VERSION 5.8 ;
BUSBITCHARS "[]" ;
DIVIDERCHAR "/" ;
UNITS
    DATABASE MICRONS 1000 ;
END UNITS

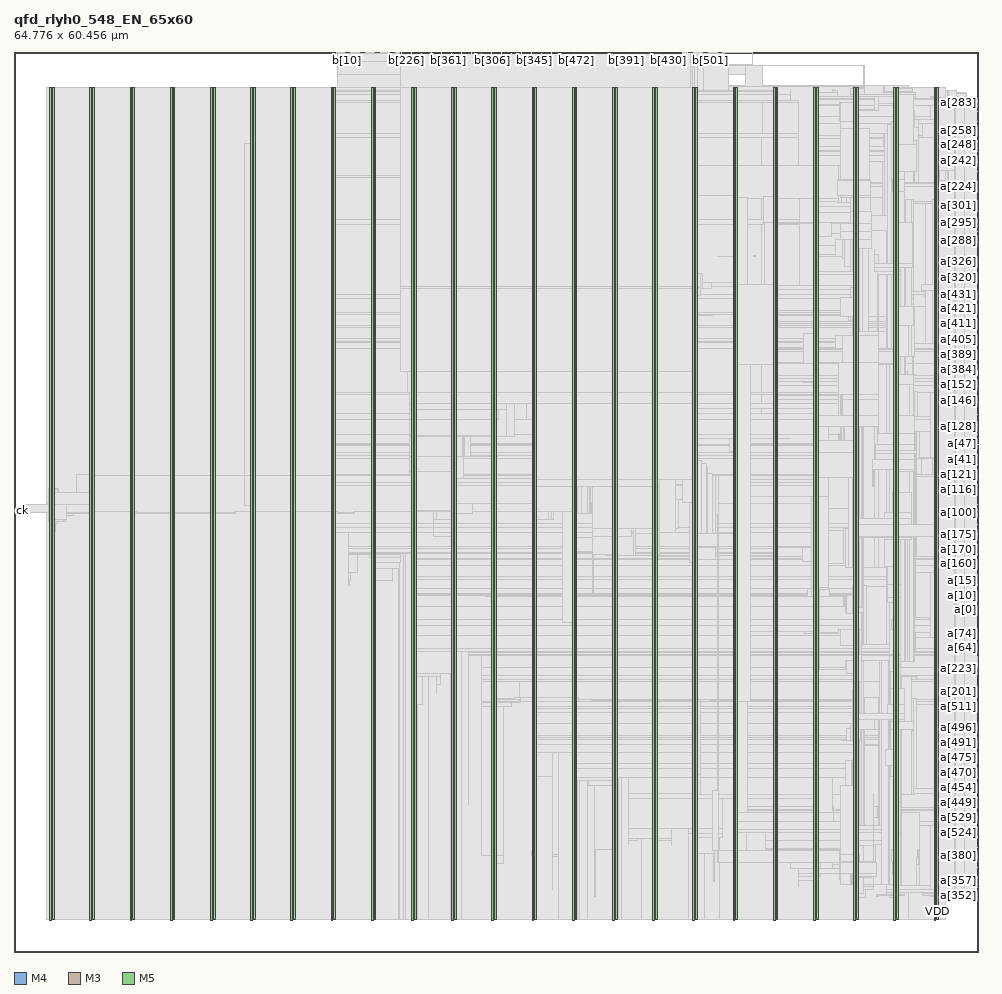
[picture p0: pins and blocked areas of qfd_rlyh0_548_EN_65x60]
MACRO qfd_rlyh0_548_EN_65x60
  FOREIGN qfd_rlyh0_548_EN_65x60 0 0 ;
  CLASS BLOCK ;
  SIZE 64.776 BY 60.456 ;
  PIN a[0]
    DIRECTION INPUT ;
    USE SIGNAL ;
    PORT
      LAYER M4 ;
        RECT  64.692 22.992 64.776 23.016 ;
    END
  END a[0]
  PIN a[100]
    DIRECTION INPUT ;
    USE SIGNAL ;
    PORT
      LAYER M4 ;
        RECT  64.692 29.52 64.776 29.544 ;
    END
  END a[100]
  PIN a[101]
    DIRECTION INPUT ;
    USE SIGNAL ;
    PORT
      LAYER M4 ;
        RECT  64.692 29.616 64.776 29.64 ;
    END
  END a[101]
  PIN a[102]
    DIRECTION INPUT ;
    USE SIGNAL ;
    PORT
      LAYER M4 ;
        RECT  64.692 29.712 64.776 29.736 ;
    END
  END a[102]
  PIN a[103]
    DIRECTION INPUT ;
    USE SIGNAL ;
    PORT
      LAYER M4 ;
        RECT  64.692 29.808 64.776 29.832 ;
    END
  END a[103]
  PIN a[104]
    DIRECTION INPUT ;
    USE SIGNAL ;
    PORT
      LAYER M4 ;
        RECT  64.692 29.904 64.776 29.928 ;
    END
  END a[104]
  PIN a[105]
    DIRECTION INPUT ;
    USE SIGNAL ;
    PORT
      LAYER M4 ;
        RECT  64.692 30 64.776 30.024 ;
    END
  END a[105]
  PIN a[106]
    DIRECTION INPUT ;
    USE SIGNAL ;
    PORT
      LAYER M4 ;
        RECT  64.692 30.096 64.776 30.12 ;
    END
  END a[106]
  PIN a[107]
    DIRECTION INPUT ;
    USE SIGNAL ;
    PORT
      LAYER M4 ;
        RECT  64.692 30.192 64.776 30.216 ;
    END
  END a[107]
  PIN a[108]
    DIRECTION INPUT ;
    USE SIGNAL ;
    PORT
      LAYER M4 ;
        RECT  64.692 30.288 64.776 30.312 ;
    END
  END a[108]
  PIN a[109]
    DIRECTION INPUT ;
    USE SIGNAL ;
    PORT
      LAYER M4 ;
        RECT  64.692 30.384 64.776 30.408 ;
    END
  END a[109]
  PIN a[10]
    DIRECTION INPUT ;
    USE SIGNAL ;
    PORT
      LAYER M4 ;
        RECT  64.692 23.952 64.776 23.976 ;
    END
  END a[10]
  PIN a[110]
    DIRECTION INPUT ;
    USE SIGNAL ;
    PORT
      LAYER M4 ;
        RECT  64.692 30.48 64.776 30.504 ;
    END
  END a[110]
  PIN a[111]
    DIRECTION INPUT ;
    USE SIGNAL ;
    PORT
      LAYER M4 ;
        RECT  64.692 30.576 64.776 30.6 ;
    END
  END a[111]
  PIN a[112]
    DIRECTION INPUT ;
    USE SIGNAL ;
    PORT
      LAYER M4 ;
        RECT  64.692 30.672 64.776 30.696 ;
    END
  END a[112]
  PIN a[113]
    DIRECTION INPUT ;
    USE SIGNAL ;
    PORT
      LAYER M4 ;
        RECT  64.692 30.768 64.776 30.792 ;
    END
  END a[113]
  PIN a[114]
    DIRECTION INPUT ;
    USE SIGNAL ;
    PORT
      LAYER M4 ;
        RECT  64.692 30.864 64.776 30.888 ;
    END
  END a[114]
  PIN a[115]
    DIRECTION INPUT ;
    USE SIGNAL ;
    PORT
      LAYER M4 ;
        RECT  64.692 30.96 64.776 30.984 ;
    END
  END a[115]
  PIN a[116]
    DIRECTION INPUT ;
    USE SIGNAL ;
    PORT
      LAYER M4 ;
        RECT  64.692 31.056 64.776 31.08 ;
    END
  END a[116]
  PIN a[117]
    DIRECTION INPUT ;
    USE SIGNAL ;
    PORT
      LAYER M4 ;
        RECT  64.692 31.152 64.776 31.176 ;
    END
  END a[117]
  PIN a[118]
    DIRECTION INPUT ;
    USE SIGNAL ;
    PORT
      LAYER M4 ;
        RECT  64.692 31.248 64.776 31.272 ;
    END
  END a[118]
  PIN a[119]
    DIRECTION INPUT ;
    USE SIGNAL ;
    PORT
      LAYER M4 ;
        RECT  64.692 31.344 64.776 31.368 ;
    END
  END a[119]
  PIN a[11]
    DIRECTION INPUT ;
    USE SIGNAL ;
    PORT
      LAYER M4 ;
        RECT  64.692 24.048 64.776 24.072 ;
    END
  END a[11]
  PIN a[120]
    DIRECTION INPUT ;
    USE SIGNAL ;
    PORT
      LAYER M4 ;
        RECT  64.692 31.44 64.776 31.464 ;
    END
  END a[120]
  PIN a[121]
    DIRECTION INPUT ;
    USE SIGNAL ;
    PORT
      LAYER M4 ;
        RECT  64.692 31.536 64.776 31.56 ;
    END
  END a[121]
  PIN a[122]
    DIRECTION INPUT ;
    USE SIGNAL ;
    PORT
      LAYER M4 ;
        RECT  64.692 31.632 64.776 31.656 ;
    END
  END a[122]
  PIN a[123]
    DIRECTION INPUT ;
    USE SIGNAL ;
    PORT
      LAYER M4 ;
        RECT  64.692 31.728 64.776 31.752 ;
    END
  END a[123]
  PIN a[124]
    DIRECTION INPUT ;
    USE SIGNAL ;
    PORT
      LAYER M4 ;
        RECT  64.692 31.824 64.776 31.848 ;
    END
  END a[124]
  PIN a[125]
    DIRECTION INPUT ;
    USE SIGNAL ;
    PORT
      LAYER M4 ;
        RECT  64.692 31.92 64.776 31.944 ;
    END
  END a[125]
  PIN a[126]
    DIRECTION INPUT ;
    USE SIGNAL ;
    PORT
      LAYER M4 ;
        RECT  64.692 32.016 64.776 32.04 ;
    END
  END a[126]
  PIN a[127]
    DIRECTION INPUT ;
    USE SIGNAL ;
    PORT
      LAYER M4 ;
        RECT  64.692 32.112 64.776 32.136 ;
    END
  END a[127]
  PIN a[128]
    DIRECTION INPUT ;
    USE SIGNAL ;
    PORT
      LAYER M4 ;
        RECT  64.692 35.28 64.776 35.304 ;
    END
  END a[128]
  PIN a[129]
    DIRECTION INPUT ;
    USE SIGNAL ;
    PORT
      LAYER M4 ;
        RECT  64.692 35.376 64.776 35.4 ;
    END
  END a[129]
  PIN a[12]
    DIRECTION INPUT ;
    USE SIGNAL ;
    PORT
      LAYER M4 ;
        RECT  64.692 24.144 64.776 24.168 ;
    END
  END a[12]
  PIN a[130]
    DIRECTION INPUT ;
    USE SIGNAL ;
    PORT
      LAYER M4 ;
        RECT  64.692 35.472 64.776 35.496 ;
    END
  END a[130]
  PIN a[131]
    DIRECTION INPUT ;
    USE SIGNAL ;
    PORT
      LAYER M4 ;
        RECT  64.692 35.568 64.776 35.592 ;
    END
  END a[131]
  PIN a[132]
    DIRECTION INPUT ;
    USE SIGNAL ;
    PORT
      LAYER M4 ;
        RECT  64.692 35.664 64.776 35.688 ;
    END
  END a[132]
  PIN a[133]
    DIRECTION INPUT ;
    USE SIGNAL ;
    PORT
      LAYER M4 ;
        RECT  64.692 35.76 64.776 35.784 ;
    END
  END a[133]
  PIN a[134]
    DIRECTION INPUT ;
    USE SIGNAL ;
    PORT
      LAYER M4 ;
        RECT  64.692 35.856 64.776 35.88 ;
    END
  END a[134]
  PIN a[135]
    DIRECTION INPUT ;
    USE SIGNAL ;
    PORT
      LAYER M4 ;
        RECT  64.692 35.952 64.776 35.976 ;
    END
  END a[135]
  PIN a[136]
    DIRECTION INPUT ;
    USE SIGNAL ;
    PORT
      LAYER M4 ;
        RECT  64.692 36.048 64.776 36.072 ;
    END
  END a[136]
  PIN a[137]
    DIRECTION INPUT ;
    USE SIGNAL ;
    PORT
      LAYER M4 ;
        RECT  64.692 36.144 64.776 36.168 ;
    END
  END a[137]
  PIN a[138]
    DIRECTION INPUT ;
    USE SIGNAL ;
    PORT
      LAYER M4 ;
        RECT  64.692 36.24 64.776 36.264 ;
    END
  END a[138]
  PIN a[139]
    DIRECTION INPUT ;
    USE SIGNAL ;
    PORT
      LAYER M4 ;
        RECT  64.692 36.336 64.776 36.36 ;
    END
  END a[139]
  PIN a[13]
    DIRECTION INPUT ;
    USE SIGNAL ;
    PORT
      LAYER M4 ;
        RECT  64.692 24.24 64.776 24.264 ;
    END
  END a[13]
  PIN a[140]
    DIRECTION INPUT ;
    USE SIGNAL ;
    PORT
      LAYER M4 ;
        RECT  64.692 36.432 64.776 36.456 ;
    END
  END a[140]
  PIN a[141]
    DIRECTION INPUT ;
    USE SIGNAL ;
    PORT
      LAYER M4 ;
        RECT  64.692 36.528 64.776 36.552 ;
    END
  END a[141]
  PIN a[142]
    DIRECTION INPUT ;
    USE SIGNAL ;
    PORT
      LAYER M4 ;
        RECT  64.692 36.624 64.776 36.648 ;
    END
  END a[142]
  PIN a[143]
    DIRECTION INPUT ;
    USE SIGNAL ;
    PORT
      LAYER M4 ;
        RECT  64.692 36.72 64.776 36.744 ;
    END
  END a[143]
  PIN a[144]
    DIRECTION INPUT ;
    USE SIGNAL ;
    PORT
      LAYER M4 ;
        RECT  64.692 36.816 64.776 36.84 ;
    END
  END a[144]
  PIN a[145]
    DIRECTION INPUT ;
    USE SIGNAL ;
    PORT
      LAYER M4 ;
        RECT  64.692 36.912 64.776 36.936 ;
    END
  END a[145]
  PIN a[146]
    DIRECTION INPUT ;
    USE SIGNAL ;
    PORT
      LAYER M4 ;
        RECT  64.692 37.008 64.776 37.032 ;
    END
  END a[146]
  PIN a[147]
    DIRECTION INPUT ;
    USE SIGNAL ;
    PORT
      LAYER M4 ;
        RECT  64.692 37.104 64.776 37.128 ;
    END
  END a[147]
  PIN a[148]
    DIRECTION INPUT ;
    USE SIGNAL ;
    PORT
      LAYER M4 ;
        RECT  64.692 37.2 64.776 37.224 ;
    END
  END a[148]
  PIN a[149]
    DIRECTION INPUT ;
    USE SIGNAL ;
    PORT
      LAYER M4 ;
        RECT  64.692 37.296 64.776 37.32 ;
    END
  END a[149]
  PIN a[14]
    DIRECTION INPUT ;
    USE SIGNAL ;
    PORT
      LAYER M4 ;
        RECT  64.692 24.336 64.776 24.36 ;
    END
  END a[14]
  PIN a[150]
    DIRECTION INPUT ;
    USE SIGNAL ;
    PORT
      LAYER M4 ;
        RECT  64.692 37.392 64.776 37.416 ;
    END
  END a[150]
  PIN a[151]
    DIRECTION INPUT ;
    USE SIGNAL ;
    PORT
      LAYER M4 ;
        RECT  64.692 37.488 64.776 37.512 ;
    END
  END a[151]
  PIN a[152]
    DIRECTION INPUT ;
    USE SIGNAL ;
    PORT
      LAYER M4 ;
        RECT  64.692 37.584 64.776 37.608 ;
    END
  END a[152]
  PIN a[153]
    DIRECTION INPUT ;
    USE SIGNAL ;
    PORT
      LAYER M4 ;
        RECT  64.692 37.68 64.776 37.704 ;
    END
  END a[153]
  PIN a[154]
    DIRECTION INPUT ;
    USE SIGNAL ;
    PORT
      LAYER M4 ;
        RECT  64.692 37.776 64.776 37.8 ;
    END
  END a[154]
  PIN a[155]
    DIRECTION INPUT ;
    USE SIGNAL ;
    PORT
      LAYER M4 ;
        RECT  64.692 37.872 64.776 37.896 ;
    END
  END a[155]
  PIN a[156]
    DIRECTION INPUT ;
    USE SIGNAL ;
    PORT
      LAYER M4 ;
        RECT  64.692 37.968 64.776 37.992 ;
    END
  END a[156]
  PIN a[157]
    DIRECTION INPUT ;
    USE SIGNAL ;
    PORT
      LAYER M4 ;
        RECT  64.692 38.064 64.776 38.088 ;
    END
  END a[157]
  PIN a[158]
    DIRECTION INPUT ;
    USE SIGNAL ;
    PORT
      LAYER M4 ;
        RECT  64.692 38.16 64.776 38.184 ;
    END
  END a[158]
  PIN a[159]
    DIRECTION INPUT ;
    USE SIGNAL ;
    PORT
      LAYER M4 ;
        RECT  64.692 38.256 64.776 38.28 ;
    END
  END a[159]
  PIN a[15]
    DIRECTION INPUT ;
    USE SIGNAL ;
    PORT
      LAYER M4 ;
        RECT  64.692 24.432 64.776 24.456 ;
    END
  END a[15]
  PIN a[160]
    DIRECTION INPUT ;
    USE SIGNAL ;
    PORT
      LAYER M4 ;
        RECT  64.692 26.064 64.776 26.088 ;
    END
  END a[160]
  PIN a[161]
    DIRECTION INPUT ;
    USE SIGNAL ;
    PORT
      LAYER M4 ;
        RECT  64.692 26.16 64.776 26.184 ;
    END
  END a[161]
  PIN a[162]
    DIRECTION INPUT ;
    USE SIGNAL ;
    PORT
      LAYER M4 ;
        RECT  64.692 26.256 64.776 26.28 ;
    END
  END a[162]
  PIN a[163]
    DIRECTION INPUT ;
    USE SIGNAL ;
    PORT
      LAYER M4 ;
        RECT  64.692 26.352 64.776 26.376 ;
    END
  END a[163]
  PIN a[164]
    DIRECTION INPUT ;
    USE SIGNAL ;
    PORT
      LAYER M4 ;
        RECT  64.692 26.448 64.776 26.472 ;
    END
  END a[164]
  PIN a[165]
    DIRECTION INPUT ;
    USE SIGNAL ;
    PORT
      LAYER M4 ;
        RECT  64.692 26.544 64.776 26.568 ;
    END
  END a[165]
  PIN a[166]
    DIRECTION INPUT ;
    USE SIGNAL ;
    PORT
      LAYER M4 ;
        RECT  64.692 26.64 64.776 26.664 ;
    END
  END a[166]
  PIN a[167]
    DIRECTION INPUT ;
    USE SIGNAL ;
    PORT
      LAYER M4 ;
        RECT  64.692 26.736 64.776 26.76 ;
    END
  END a[167]
  PIN a[168]
    DIRECTION INPUT ;
    USE SIGNAL ;
    PORT
      LAYER M4 ;
        RECT  64.692 26.832 64.776 26.856 ;
    END
  END a[168]
  PIN a[169]
    DIRECTION INPUT ;
    USE SIGNAL ;
    PORT
      LAYER M4 ;
        RECT  64.692 26.928 64.776 26.952 ;
    END
  END a[169]
  PIN a[16]
    DIRECTION INPUT ;
    USE SIGNAL ;
    PORT
      LAYER M4 ;
        RECT  64.692 24.528 64.776 24.552 ;
    END
  END a[16]
  PIN a[170]
    DIRECTION INPUT ;
    USE SIGNAL ;
    PORT
      LAYER M4 ;
        RECT  64.692 27.024 64.776 27.048 ;
    END
  END a[170]
  PIN a[171]
    DIRECTION INPUT ;
    USE SIGNAL ;
    PORT
      LAYER M4 ;
        RECT  64.692 27.12 64.776 27.144 ;
    END
  END a[171]
  PIN a[172]
    DIRECTION INPUT ;
    USE SIGNAL ;
    PORT
      LAYER M4 ;
        RECT  64.692 27.216 64.776 27.24 ;
    END
  END a[172]
  PIN a[173]
    DIRECTION INPUT ;
    USE SIGNAL ;
    PORT
      LAYER M4 ;
        RECT  64.692 27.312 64.776 27.336 ;
    END
  END a[173]
  PIN a[174]
    DIRECTION INPUT ;
    USE SIGNAL ;
    PORT
      LAYER M4 ;
        RECT  64.692 27.408 64.776 27.432 ;
    END
  END a[174]
  PIN a[175]
    DIRECTION INPUT ;
    USE SIGNAL ;
    PORT
      LAYER M4 ;
        RECT  64.692 27.504 64.776 27.528 ;
    END
  END a[175]
  PIN a[176]
    DIRECTION INPUT ;
    USE SIGNAL ;
    PORT
      LAYER M4 ;
        RECT  64.692 27.6 64.776 27.624 ;
    END
  END a[176]
  PIN a[177]
    DIRECTION INPUT ;
    USE SIGNAL ;
    PORT
      LAYER M4 ;
        RECT  64.692 27.696 64.776 27.72 ;
    END
  END a[177]
  PIN a[178]
    DIRECTION INPUT ;
    USE SIGNAL ;
    PORT
      LAYER M4 ;
        RECT  64.692 27.792 64.776 27.816 ;
    END
  END a[178]
  PIN a[179]
    DIRECTION INPUT ;
    USE SIGNAL ;
    PORT
      LAYER M4 ;
        RECT  64.692 27.888 64.776 27.912 ;
    END
  END a[179]
  PIN a[17]
    DIRECTION INPUT ;
    USE SIGNAL ;
    PORT
      LAYER M4 ;
        RECT  64.692 24.624 64.776 24.648 ;
    END
  END a[17]
  PIN a[180]
    DIRECTION INPUT ;
    USE SIGNAL ;
    PORT
      LAYER M4 ;
        RECT  64.692 27.984 64.776 28.008 ;
    END
  END a[180]
  PIN a[181]
    DIRECTION INPUT ;
    USE SIGNAL ;
    PORT
      LAYER M4 ;
        RECT  64.692 28.08 64.776 28.104 ;
    END
  END a[181]
  PIN a[182]
    DIRECTION INPUT ;
    USE SIGNAL ;
    PORT
      LAYER M4 ;
        RECT  64.692 28.176 64.776 28.2 ;
    END
  END a[182]
  PIN a[183]
    DIRECTION INPUT ;
    USE SIGNAL ;
    PORT
      LAYER M4 ;
        RECT  64.692 28.272 64.776 28.296 ;
    END
  END a[183]
  PIN a[184]
    DIRECTION INPUT ;
    USE SIGNAL ;
    PORT
      LAYER M4 ;
        RECT  64.692 28.368 64.776 28.392 ;
    END
  END a[184]
  PIN a[185]
    DIRECTION INPUT ;
    USE SIGNAL ;
    PORT
      LAYER M4 ;
        RECT  64.692 28.464 64.776 28.488 ;
    END
  END a[185]
  PIN a[186]
    DIRECTION INPUT ;
    USE SIGNAL ;
    PORT
      LAYER M4 ;
        RECT  64.692 28.56 64.776 28.584 ;
    END
  END a[186]
  PIN a[187]
    DIRECTION INPUT ;
    USE SIGNAL ;
    PORT
      LAYER M4 ;
        RECT  64.692 28.656 64.776 28.68 ;
    END
  END a[187]
  PIN a[188]
    DIRECTION INPUT ;
    USE SIGNAL ;
    PORT
      LAYER M4 ;
        RECT  64.692 28.752 64.776 28.776 ;
    END
  END a[188]
  PIN a[189]
    DIRECTION INPUT ;
    USE SIGNAL ;
    PORT
      LAYER M4 ;
        RECT  64.692 28.848 64.776 28.872 ;
    END
  END a[189]
  PIN a[18]
    DIRECTION INPUT ;
    USE SIGNAL ;
    PORT
      LAYER M4 ;
        RECT  64.692 24.72 64.776 24.744 ;
    END
  END a[18]
  PIN a[190]
    DIRECTION INPUT ;
    USE SIGNAL ;
    PORT
      LAYER M4 ;
        RECT  64.692 28.944 64.776 28.968 ;
    END
  END a[190]
  PIN a[191]
    DIRECTION INPUT ;
    USE SIGNAL ;
    PORT
      LAYER M4 ;
        RECT  64.692 29.04 64.776 29.064 ;
    END
  END a[191]
  PIN a[192]
    DIRECTION INPUT ;
    USE SIGNAL ;
    PORT
      LAYER M4 ;
        RECT  64.692 16.08 64.776 16.104 ;
    END
  END a[192]
  PIN a[193]
    DIRECTION INPUT ;
    USE SIGNAL ;
    PORT
      LAYER M4 ;
        RECT  64.692 16.176 64.776 16.2 ;
    END
  END a[193]
  PIN a[194]
    DIRECTION INPUT ;
    USE SIGNAL ;
    PORT
      LAYER M4 ;
        RECT  64.692 16.272 64.776 16.296 ;
    END
  END a[194]
  PIN a[195]
    DIRECTION INPUT ;
    USE SIGNAL ;
    PORT
      LAYER M4 ;
        RECT  64.692 16.368 64.776 16.392 ;
    END
  END a[195]
  PIN a[196]
    DIRECTION INPUT ;
    USE SIGNAL ;
    PORT
      LAYER M4 ;
        RECT  64.692 16.464 64.776 16.488 ;
    END
  END a[196]
  PIN a[197]
    DIRECTION INPUT ;
    USE SIGNAL ;
    PORT
      LAYER M4 ;
        RECT  64.692 16.56 64.776 16.584 ;
    END
  END a[197]
  PIN a[198]
    DIRECTION INPUT ;
    USE SIGNAL ;
    PORT
      LAYER M4 ;
        RECT  64.692 16.656 64.776 16.68 ;
    END
  END a[198]
  PIN a[199]
    DIRECTION INPUT ;
    USE SIGNAL ;
    PORT
      LAYER M4 ;
        RECT  64.692 16.752 64.776 16.776 ;
    END
  END a[199]
  PIN a[19]
    DIRECTION INPUT ;
    USE SIGNAL ;
    PORT
      LAYER M4 ;
        RECT  64.692 24.816 64.776 24.84 ;
    END
  END a[19]
  PIN a[1]
    DIRECTION INPUT ;
    USE SIGNAL ;
    PORT
      LAYER M4 ;
        RECT  64.692 23.088 64.776 23.112 ;
    END
  END a[1]
  PIN a[200]
    DIRECTION INPUT ;
    USE SIGNAL ;
    PORT
      LAYER M4 ;
        RECT  64.692 16.848 64.776 16.872 ;
    END
  END a[200]
  PIN a[201]
    DIRECTION INPUT ;
    USE SIGNAL ;
    PORT
      LAYER M4 ;
        RECT  64.692 16.944 64.776 16.968 ;
    END
  END a[201]
  PIN a[202]
    DIRECTION INPUT ;
    USE SIGNAL ;
    PORT
      LAYER M4 ;
        RECT  64.692 17.04 64.776 17.064 ;
    END
  END a[202]
  PIN a[203]
    DIRECTION INPUT ;
    USE SIGNAL ;
    PORT
      LAYER M4 ;
        RECT  64.692 17.136 64.776 17.16 ;
    END
  END a[203]
  PIN a[204]
    DIRECTION INPUT ;
    USE SIGNAL ;
    PORT
      LAYER M4 ;
        RECT  64.692 17.232 64.776 17.256 ;
    END
  END a[204]
  PIN a[205]
    DIRECTION INPUT ;
    USE SIGNAL ;
    PORT
      LAYER M4 ;
        RECT  64.692 17.328 64.776 17.352 ;
    END
  END a[205]
  PIN a[206]
    DIRECTION INPUT ;
    USE SIGNAL ;
    PORT
      LAYER M4 ;
        RECT  64.692 17.424 64.776 17.448 ;
    END
  END a[206]
  PIN a[207]
    DIRECTION INPUT ;
    USE SIGNAL ;
    PORT
      LAYER M4 ;
        RECT  64.692 17.52 64.776 17.544 ;
    END
  END a[207]
  PIN a[208]
    DIRECTION INPUT ;
    USE SIGNAL ;
    PORT
      LAYER M4 ;
        RECT  64.692 17.616 64.776 17.64 ;
    END
  END a[208]
  PIN a[209]
    DIRECTION INPUT ;
    USE SIGNAL ;
    PORT
      LAYER M4 ;
        RECT  64.692 17.712 64.776 17.736 ;
    END
  END a[209]
  PIN a[20]
    DIRECTION INPUT ;
    USE SIGNAL ;
    PORT
      LAYER M4 ;
        RECT  64.692 24.912 64.776 24.936 ;
    END
  END a[20]
  PIN a[210]
    DIRECTION INPUT ;
    USE SIGNAL ;
    PORT
      LAYER M4 ;
        RECT  64.692 17.808 64.776 17.832 ;
    END
  END a[210]
  PIN a[211]
    DIRECTION INPUT ;
    USE SIGNAL ;
    PORT
      LAYER M4 ;
        RECT  64.692 17.904 64.776 17.928 ;
    END
  END a[211]
  PIN a[212]
    DIRECTION INPUT ;
    USE SIGNAL ;
    PORT
      LAYER M4 ;
        RECT  64.692 18 64.776 18.024 ;
    END
  END a[212]
  PIN a[213]
    DIRECTION INPUT ;
    USE SIGNAL ;
    PORT
      LAYER M4 ;
        RECT  64.692 18.096 64.776 18.12 ;
    END
  END a[213]
  PIN a[214]
    DIRECTION INPUT ;
    USE SIGNAL ;
    PORT
      LAYER M4 ;
        RECT  64.692 18.192 64.776 18.216 ;
    END
  END a[214]
  PIN a[215]
    DIRECTION INPUT ;
    USE SIGNAL ;
    PORT
      LAYER M4 ;
        RECT  64.692 18.288 64.776 18.312 ;
    END
  END a[215]
  PIN a[216]
    DIRECTION INPUT ;
    USE SIGNAL ;
    PORT
      LAYER M4 ;
        RECT  64.692 18.384 64.776 18.408 ;
    END
  END a[216]
  PIN a[217]
    DIRECTION INPUT ;
    USE SIGNAL ;
    PORT
      LAYER M4 ;
        RECT  64.692 18.48 64.776 18.504 ;
    END
  END a[217]
  PIN a[218]
    DIRECTION INPUT ;
    USE SIGNAL ;
    PORT
      LAYER M4 ;
        RECT  64.692 18.576 64.776 18.6 ;
    END
  END a[218]
  PIN a[219]
    DIRECTION INPUT ;
    USE SIGNAL ;
    PORT
      LAYER M4 ;
        RECT  64.692 18.672 64.776 18.696 ;
    END
  END a[219]
  PIN a[21]
    DIRECTION INPUT ;
    USE SIGNAL ;
    PORT
      LAYER M4 ;
        RECT  64.692 25.008 64.776 25.032 ;
    END
  END a[21]
  PIN a[220]
    DIRECTION INPUT ;
    USE SIGNAL ;
    PORT
      LAYER M4 ;
        RECT  64.692 18.768 64.776 18.792 ;
    END
  END a[220]
  PIN a[221]
    DIRECTION INPUT ;
    USE SIGNAL ;
    PORT
      LAYER M4 ;
        RECT  64.692 18.864 64.776 18.888 ;
    END
  END a[221]
  PIN a[222]
    DIRECTION INPUT ;
    USE SIGNAL ;
    PORT
      LAYER M4 ;
        RECT  64.692 18.96 64.776 18.984 ;
    END
  END a[222]
  PIN a[223]
    DIRECTION INPUT ;
    USE SIGNAL ;
    PORT
      LAYER M4 ;
        RECT  64.692 19.056 64.776 19.08 ;
    END
  END a[223]
  PIN a[224]
    DIRECTION INPUT ;
    USE SIGNAL ;
    PORT
      LAYER M4 ;
        RECT  64.692 51.408 64.776 51.432 ;
    END
  END a[224]
  PIN a[225]
    DIRECTION INPUT ;
    USE SIGNAL ;
    PORT
      LAYER M4 ;
        RECT  64.692 51.504 64.776 51.528 ;
    END
  END a[225]
  PIN a[226]
    DIRECTION INPUT ;
    USE SIGNAL ;
    PORT
      LAYER M4 ;
        RECT  64.692 51.6 64.776 51.624 ;
    END
  END a[226]
  PIN a[227]
    DIRECTION INPUT ;
    USE SIGNAL ;
    PORT
      LAYER M4 ;
        RECT  64.692 51.696 64.776 51.72 ;
    END
  END a[227]
  PIN a[228]
    DIRECTION INPUT ;
    USE SIGNAL ;
    PORT
      LAYER M4 ;
        RECT  64.692 51.792 64.776 51.816 ;
    END
  END a[228]
  PIN a[229]
    DIRECTION INPUT ;
    USE SIGNAL ;
    PORT
      LAYER M4 ;
        RECT  64.692 51.888 64.776 51.912 ;
    END
  END a[229]
  PIN a[22]
    DIRECTION INPUT ;
    USE SIGNAL ;
    PORT
      LAYER M4 ;
        RECT  64.692 25.104 64.776 25.128 ;
    END
  END a[22]
  PIN a[230]
    DIRECTION INPUT ;
    USE SIGNAL ;
    PORT
      LAYER M4 ;
        RECT  64.692 51.984 64.776 52.008 ;
    END
  END a[230]
  PIN a[231]
    DIRECTION INPUT ;
    USE SIGNAL ;
    PORT
      LAYER M4 ;
        RECT  64.692 52.08 64.776 52.104 ;
    END
  END a[231]
  PIN a[232]
    DIRECTION INPUT ;
    USE SIGNAL ;
    PORT
      LAYER M4 ;
        RECT  64.692 52.176 64.776 52.2 ;
    END
  END a[232]
  PIN a[233]
    DIRECTION INPUT ;
    USE SIGNAL ;
    PORT
      LAYER M4 ;
        RECT  64.692 52.272 64.776 52.296 ;
    END
  END a[233]
  PIN a[234]
    DIRECTION INPUT ;
    USE SIGNAL ;
    PORT
      LAYER M4 ;
        RECT  64.692 52.368 64.776 52.392 ;
    END
  END a[234]
  PIN a[235]
    DIRECTION INPUT ;
    USE SIGNAL ;
    PORT
      LAYER M4 ;
        RECT  64.692 52.464 64.776 52.488 ;
    END
  END a[235]
  PIN a[236]
    DIRECTION INPUT ;
    USE SIGNAL ;
    PORT
      LAYER M4 ;
        RECT  64.692 52.56 64.776 52.584 ;
    END
  END a[236]
  PIN a[237]
    DIRECTION INPUT ;
    USE SIGNAL ;
    PORT
      LAYER M4 ;
        RECT  64.692 52.656 64.776 52.68 ;
    END
  END a[237]
  PIN a[238]
    DIRECTION INPUT ;
    USE SIGNAL ;
    PORT
      LAYER M4 ;
        RECT  64.692 52.752 64.776 52.776 ;
    END
  END a[238]
  PIN a[239]
    DIRECTION INPUT ;
    USE SIGNAL ;
    PORT
      LAYER M4 ;
        RECT  64.692 52.848 64.776 52.872 ;
    END
  END a[239]
  PIN a[23]
    DIRECTION INPUT ;
    USE SIGNAL ;
    PORT
      LAYER M4 ;
        RECT  64.692 25.2 64.776 25.224 ;
    END
  END a[23]
  PIN a[240]
    DIRECTION INPUT ;
    USE SIGNAL ;
    PORT
      LAYER M4 ;
        RECT  64.692 52.944 64.776 52.968 ;
    END
  END a[240]
  PIN a[241]
    DIRECTION INPUT ;
    USE SIGNAL ;
    PORT
      LAYER M4 ;
        RECT  64.692 53.04 64.776 53.064 ;
    END
  END a[241]
  PIN a[242]
    DIRECTION INPUT ;
    USE SIGNAL ;
    PORT
      LAYER M4 ;
        RECT  64.692 53.136 64.776 53.16 ;
    END
  END a[242]
  PIN a[243]
    DIRECTION INPUT ;
    USE SIGNAL ;
    PORT
      LAYER M4 ;
        RECT  64.692 53.232 64.776 53.256 ;
    END
  END a[243]
  PIN a[244]
    DIRECTION INPUT ;
    USE SIGNAL ;
    PORT
      LAYER M4 ;
        RECT  64.692 53.328 64.776 53.352 ;
    END
  END a[244]
  PIN a[245]
    DIRECTION INPUT ;
    USE SIGNAL ;
    PORT
      LAYER M4 ;
        RECT  64.692 53.424 64.776 53.448 ;
    END
  END a[245]
  PIN a[246]
    DIRECTION INPUT ;
    USE SIGNAL ;
    PORT
      LAYER M4 ;
        RECT  64.692 53.52 64.776 53.544 ;
    END
  END a[246]
  PIN a[247]
    DIRECTION INPUT ;
    USE SIGNAL ;
    PORT
      LAYER M4 ;
        RECT  64.692 53.616 64.776 53.64 ;
    END
  END a[247]
  PIN a[248]
    DIRECTION INPUT ;
    USE SIGNAL ;
    PORT
      LAYER M4 ;
        RECT  64.692 53.712 64.776 53.736 ;
    END
  END a[248]
  PIN a[249]
    DIRECTION INPUT ;
    USE SIGNAL ;
    PORT
      LAYER M4 ;
        RECT  64.692 53.808 64.776 53.832 ;
    END
  END a[249]
  PIN a[24]
    DIRECTION INPUT ;
    USE SIGNAL ;
    PORT
      LAYER M4 ;
        RECT  64.692 25.296 64.776 25.32 ;
    END
  END a[24]
  PIN a[250]
    DIRECTION INPUT ;
    USE SIGNAL ;
    PORT
      LAYER M4 ;
        RECT  64.692 53.904 64.776 53.928 ;
    END
  END a[250]
  PIN a[251]
    DIRECTION INPUT ;
    USE SIGNAL ;
    PORT
      LAYER M4 ;
        RECT  64.692 54 64.776 54.024 ;
    END
  END a[251]
  PIN a[252]
    DIRECTION INPUT ;
    USE SIGNAL ;
    PORT
      LAYER M4 ;
        RECT  64.692 54.096 64.776 54.12 ;
    END
  END a[252]
  PIN a[253]
    DIRECTION INPUT ;
    USE SIGNAL ;
    PORT
      LAYER M4 ;
        RECT  64.692 54.192 64.776 54.216 ;
    END
  END a[253]
  PIN a[254]
    DIRECTION INPUT ;
    USE SIGNAL ;
    PORT
      LAYER M4 ;
        RECT  64.692 54.288 64.776 54.312 ;
    END
  END a[254]
  PIN a[255]
    DIRECTION INPUT ;
    USE SIGNAL ;
    PORT
      LAYER M4 ;
        RECT  64.692 54.384 64.776 54.408 ;
    END
  END a[255]
  PIN a[256]
    DIRECTION INPUT ;
    USE SIGNAL ;
    PORT
      LAYER M4 ;
        RECT  64.692 54.48 64.776 54.504 ;
    END
  END a[256]
  PIN a[257]
    DIRECTION INPUT ;
    USE SIGNAL ;
    PORT
      LAYER M4 ;
        RECT  64.692 54.576 64.776 54.6 ;
    END
  END a[257]
  PIN a[258]
    DIRECTION INPUT ;
    USE SIGNAL ;
    PORT
      LAYER M4 ;
        RECT  64.692 54.672 64.776 54.696 ;
    END
  END a[258]
  PIN a[259]
    DIRECTION INPUT ;
    USE SIGNAL ;
    PORT
      LAYER M4 ;
        RECT  64.692 54.768 64.776 54.792 ;
    END
  END a[259]
  PIN a[25]
    DIRECTION INPUT ;
    USE SIGNAL ;
    PORT
      LAYER M4 ;
        RECT  64.692 25.392 64.776 25.416 ;
    END
  END a[25]
  PIN a[260]
    DIRECTION INPUT ;
    USE SIGNAL ;
    PORT
      LAYER M4 ;
        RECT  64.692 54.864 64.776 54.888 ;
    END
  END a[260]
  PIN a[261]
    DIRECTION INPUT ;
    USE SIGNAL ;
    PORT
      LAYER M4 ;
        RECT  64.692 54.96 64.776 54.984 ;
    END
  END a[261]
  PIN a[262]
    DIRECTION INPUT ;
    USE SIGNAL ;
    PORT
      LAYER M4 ;
        RECT  64.692 55.056 64.776 55.08 ;
    END
  END a[262]
  PIN a[263]
    DIRECTION INPUT ;
    USE SIGNAL ;
    PORT
      LAYER M4 ;
        RECT  64.692 55.152 64.776 55.176 ;
    END
  END a[263]
  PIN a[264]
    DIRECTION INPUT ;
    USE SIGNAL ;
    PORT
      LAYER M4 ;
        RECT  64.692 55.248 64.776 55.272 ;
    END
  END a[264]
  PIN a[265]
    DIRECTION INPUT ;
    USE SIGNAL ;
    PORT
      LAYER M4 ;
        RECT  64.692 55.344 64.776 55.368 ;
    END
  END a[265]
  PIN a[266]
    DIRECTION INPUT ;
    USE SIGNAL ;
    PORT
      LAYER M4 ;
        RECT  64.692 55.44 64.776 55.464 ;
    END
  END a[266]
  PIN a[267]
    DIRECTION INPUT ;
    USE SIGNAL ;
    PORT
      LAYER M4 ;
        RECT  64.692 55.536 64.776 55.56 ;
    END
  END a[267]
  PIN a[268]
    DIRECTION INPUT ;
    USE SIGNAL ;
    PORT
      LAYER M4 ;
        RECT  64.692 55.632 64.776 55.656 ;
    END
  END a[268]
  PIN a[269]
    DIRECTION INPUT ;
    USE SIGNAL ;
    PORT
      LAYER M4 ;
        RECT  64.692 55.728 64.776 55.752 ;
    END
  END a[269]
  PIN a[26]
    DIRECTION INPUT ;
    USE SIGNAL ;
    PORT
      LAYER M4 ;
        RECT  64.692 25.488 64.776 25.512 ;
    END
  END a[26]
  PIN a[270]
    DIRECTION INPUT ;
    USE SIGNAL ;
    PORT
      LAYER M4 ;
        RECT  64.692 55.824 64.776 55.848 ;
    END
  END a[270]
  PIN a[271]
    DIRECTION INPUT ;
    USE SIGNAL ;
    PORT
      LAYER M4 ;
        RECT  64.692 55.92 64.776 55.944 ;
    END
  END a[271]
  PIN a[272]
    DIRECTION INPUT ;
    USE SIGNAL ;
    PORT
      LAYER M4 ;
        RECT  64.692 56.016 64.776 56.04 ;
    END
  END a[272]
  PIN a[273]
    DIRECTION INPUT ;
    USE SIGNAL ;
    PORT
      LAYER M4 ;
        RECT  64.692 56.112 64.776 56.136 ;
    END
  END a[273]
  PIN a[274]
    DIRECTION INPUT ;
    USE SIGNAL ;
    PORT
      LAYER M4 ;
        RECT  64.692 56.208 64.776 56.232 ;
    END
  END a[274]
  PIN a[275]
    DIRECTION INPUT ;
    USE SIGNAL ;
    PORT
      LAYER M4 ;
        RECT  64.692 56.304 64.776 56.328 ;
    END
  END a[275]
  PIN a[276]
    DIRECTION INPUT ;
    USE SIGNAL ;
    PORT
      LAYER M4 ;
        RECT  64.692 56.4 64.776 56.424 ;
    END
  END a[276]
  PIN a[277]
    DIRECTION INPUT ;
    USE SIGNAL ;
    PORT
      LAYER M4 ;
        RECT  64.692 56.496 64.776 56.52 ;
    END
  END a[277]
  PIN a[278]
    DIRECTION INPUT ;
    USE SIGNAL ;
    PORT
      LAYER M4 ;
        RECT  64.692 56.592 64.776 56.616 ;
    END
  END a[278]
  PIN a[279]
    DIRECTION INPUT ;
    USE SIGNAL ;
    PORT
      LAYER M4 ;
        RECT  64.692 56.688 64.776 56.712 ;
    END
  END a[279]
  PIN a[27]
    DIRECTION INPUT ;
    USE SIGNAL ;
    PORT
      LAYER M4 ;
        RECT  64.692 25.584 64.776 25.608 ;
    END
  END a[27]
  PIN a[280]
    DIRECTION INPUT ;
    USE SIGNAL ;
    PORT
      LAYER M4 ;
        RECT  64.692 56.784 64.776 56.808 ;
    END
  END a[280]
  PIN a[281]
    DIRECTION INPUT ;
    USE SIGNAL ;
    PORT
      LAYER M4 ;
        RECT  64.692 56.88 64.776 56.904 ;
    END
  END a[281]
  PIN a[282]
    DIRECTION INPUT ;
    USE SIGNAL ;
    PORT
      LAYER M4 ;
        RECT  64.692 56.976 64.776 57 ;
    END
  END a[282]
  PIN a[283]
    DIRECTION INPUT ;
    USE SIGNAL ;
    PORT
      LAYER M4 ;
        RECT  64.692 57.072 64.776 57.096 ;
    END
  END a[283]
  PIN a[284]
    DIRECTION INPUT ;
    USE SIGNAL ;
    PORT
      LAYER M4 ;
        RECT  64.692 57.168 64.776 57.192 ;
    END
  END a[284]
  PIN a[285]
    DIRECTION INPUT ;
    USE SIGNAL ;
    PORT
      LAYER M4 ;
        RECT  64.692 57.264 64.776 57.288 ;
    END
  END a[285]
  PIN a[286]
    DIRECTION INPUT ;
    USE SIGNAL ;
    PORT
      LAYER M4 ;
        RECT  64.692 57.36 64.776 57.384 ;
    END
  END a[286]
  PIN a[287]
    DIRECTION INPUT ;
    USE SIGNAL ;
    PORT
      LAYER M4 ;
        RECT  64.692 57.456 64.776 57.48 ;
    END
  END a[287]
  PIN a[288]
    DIRECTION INPUT ;
    USE SIGNAL ;
    PORT
      LAYER M4 ;
        RECT  64.692 48.336 64.776 48.36 ;
    END
  END a[288]
  PIN a[289]
    DIRECTION INPUT ;
    USE SIGNAL ;
    PORT
      LAYER M4 ;
        RECT  64.692 48.432 64.776 48.456 ;
    END
  END a[289]
  PIN a[28]
    DIRECTION INPUT ;
    USE SIGNAL ;
    PORT
      LAYER M4 ;
        RECT  64.692 25.68 64.776 25.704 ;
    END
  END a[28]
  PIN a[290]
    DIRECTION INPUT ;
    USE SIGNAL ;
    PORT
      LAYER M4 ;
        RECT  64.692 48.528 64.776 48.552 ;
    END
  END a[290]
  PIN a[291]
    DIRECTION INPUT ;
    USE SIGNAL ;
    PORT
      LAYER M4 ;
        RECT  64.692 48.624 64.776 48.648 ;
    END
  END a[291]
  PIN a[292]
    DIRECTION INPUT ;
    USE SIGNAL ;
    PORT
      LAYER M4 ;
        RECT  64.692 48.72 64.776 48.744 ;
    END
  END a[292]
  PIN a[293]
    DIRECTION INPUT ;
    USE SIGNAL ;
    PORT
      LAYER M4 ;
        RECT  64.692 48.816 64.776 48.84 ;
    END
  END a[293]
  PIN a[294]
    DIRECTION INPUT ;
    USE SIGNAL ;
    PORT
      LAYER M4 ;
        RECT  64.692 48.912 64.776 48.936 ;
    END
  END a[294]
  PIN a[295]
    DIRECTION INPUT ;
    USE SIGNAL ;
    PORT
      LAYER M4 ;
        RECT  64.692 49.008 64.776 49.032 ;
    END
  END a[295]
  PIN a[296]
    DIRECTION INPUT ;
    USE SIGNAL ;
    PORT
      LAYER M4 ;
        RECT  64.692 49.104 64.776 49.128 ;
    END
  END a[296]
  PIN a[297]
    DIRECTION INPUT ;
    USE SIGNAL ;
    PORT
      LAYER M4 ;
        RECT  64.692 49.2 64.776 49.224 ;
    END
  END a[297]
  PIN a[298]
    DIRECTION INPUT ;
    USE SIGNAL ;
    PORT
      LAYER M4 ;
        RECT  64.692 49.296 64.776 49.32 ;
    END
  END a[298]
  PIN a[299]
    DIRECTION INPUT ;
    USE SIGNAL ;
    PORT
      LAYER M4 ;
        RECT  64.692 49.392 64.776 49.416 ;
    END
  END a[299]
  PIN a[29]
    DIRECTION INPUT ;
    USE SIGNAL ;
    PORT
      LAYER M4 ;
        RECT  64.692 25.776 64.776 25.8 ;
    END
  END a[29]
  PIN a[2]
    DIRECTION INPUT ;
    USE SIGNAL ;
    PORT
      LAYER M4 ;
        RECT  64.692 23.184 64.776 23.208 ;
    END
  END a[2]
  PIN a[300]
    DIRECTION INPUT ;
    USE SIGNAL ;
    PORT
      LAYER M4 ;
        RECT  64.692 49.488 64.776 49.512 ;
    END
  END a[300]
  PIN a[301]
    DIRECTION INPUT ;
    USE SIGNAL ;
    PORT
      LAYER M4 ;
        RECT  64.692 49.584 64.776 49.608 ;
    END
  END a[301]
  PIN a[302]
    DIRECTION INPUT ;
    USE SIGNAL ;
    PORT
      LAYER M4 ;
        RECT  64.692 49.68 64.776 49.704 ;
    END
  END a[302]
  PIN a[303]
    DIRECTION INPUT ;
    USE SIGNAL ;
    PORT
      LAYER M4 ;
        RECT  64.692 49.776 64.776 49.8 ;
    END
  END a[303]
  PIN a[304]
    DIRECTION INPUT ;
    USE SIGNAL ;
    PORT
      LAYER M4 ;
        RECT  64.692 49.872 64.776 49.896 ;
    END
  END a[304]
  PIN a[305]
    DIRECTION INPUT ;
    USE SIGNAL ;
    PORT
      LAYER M4 ;
        RECT  64.692 49.968 64.776 49.992 ;
    END
  END a[305]
  PIN a[306]
    DIRECTION INPUT ;
    USE SIGNAL ;
    PORT
      LAYER M4 ;
        RECT  64.692 50.064 64.776 50.088 ;
    END
  END a[306]
  PIN a[307]
    DIRECTION INPUT ;
    USE SIGNAL ;
    PORT
      LAYER M4 ;
        RECT  64.692 50.16 64.776 50.184 ;
    END
  END a[307]
  PIN a[308]
    DIRECTION INPUT ;
    USE SIGNAL ;
    PORT
      LAYER M4 ;
        RECT  64.692 50.256 64.776 50.28 ;
    END
  END a[308]
  PIN a[309]
    DIRECTION INPUT ;
    USE SIGNAL ;
    PORT
      LAYER M4 ;
        RECT  64.692 50.352 64.776 50.376 ;
    END
  END a[309]
  PIN a[30]
    DIRECTION INPUT ;
    USE SIGNAL ;
    PORT
      LAYER M4 ;
        RECT  64.692 25.872 64.776 25.896 ;
    END
  END a[30]
  PIN a[310]
    DIRECTION INPUT ;
    USE SIGNAL ;
    PORT
      LAYER M4 ;
        RECT  64.692 50.448 64.776 50.472 ;
    END
  END a[310]
  PIN a[311]
    DIRECTION INPUT ;
    USE SIGNAL ;
    PORT
      LAYER M4 ;
        RECT  64.692 50.544 64.776 50.568 ;
    END
  END a[311]
  PIN a[312]
    DIRECTION INPUT ;
    USE SIGNAL ;
    PORT
      LAYER M4 ;
        RECT  64.692 50.64 64.776 50.664 ;
    END
  END a[312]
  PIN a[313]
    DIRECTION INPUT ;
    USE SIGNAL ;
    PORT
      LAYER M4 ;
        RECT  64.692 50.736 64.776 50.76 ;
    END
  END a[313]
  PIN a[314]
    DIRECTION INPUT ;
    USE SIGNAL ;
    PORT
      LAYER M4 ;
        RECT  64.692 50.832 64.776 50.856 ;
    END
  END a[314]
  PIN a[315]
    DIRECTION INPUT ;
    USE SIGNAL ;
    PORT
      LAYER M4 ;
        RECT  64.692 50.928 64.776 50.952 ;
    END
  END a[315]
  PIN a[316]
    DIRECTION INPUT ;
    USE SIGNAL ;
    PORT
      LAYER M4 ;
        RECT  64.692 51.024 64.776 51.048 ;
    END
  END a[316]
  PIN a[317]
    DIRECTION INPUT ;
    USE SIGNAL ;
    PORT
      LAYER M4 ;
        RECT  64.692 51.12 64.776 51.144 ;
    END
  END a[317]
  PIN a[318]
    DIRECTION INPUT ;
    USE SIGNAL ;
    PORT
      LAYER M4 ;
        RECT  64.692 51.216 64.776 51.24 ;
    END
  END a[318]
  PIN a[319]
    DIRECTION INPUT ;
    USE SIGNAL ;
    PORT
      LAYER M4 ;
        RECT  64.692 51.312 64.776 51.336 ;
    END
  END a[319]
  PIN a[31]
    DIRECTION INPUT ;
    USE SIGNAL ;
    PORT
      LAYER M4 ;
        RECT  64.692 25.968 64.776 25.992 ;
    END
  END a[31]
  PIN a[320]
    DIRECTION INPUT ;
    USE SIGNAL ;
    PORT
      LAYER M4 ;
        RECT  64.692 45.264 64.776 45.288 ;
    END
  END a[320]
  PIN a[321]
    DIRECTION INPUT ;
    USE SIGNAL ;
    PORT
      LAYER M4 ;
        RECT  64.692 45.36 64.776 45.384 ;
    END
  END a[321]
  PIN a[322]
    DIRECTION INPUT ;
    USE SIGNAL ;
    PORT
      LAYER M4 ;
        RECT  64.692 45.456 64.776 45.48 ;
    END
  END a[322]
  PIN a[323]
    DIRECTION INPUT ;
    USE SIGNAL ;
    PORT
      LAYER M4 ;
        RECT  64.692 45.552 64.776 45.576 ;
    END
  END a[323]
  PIN a[324]
    DIRECTION INPUT ;
    USE SIGNAL ;
    PORT
      LAYER M4 ;
        RECT  64.692 45.648 64.776 45.672 ;
    END
  END a[324]
  PIN a[325]
    DIRECTION INPUT ;
    USE SIGNAL ;
    PORT
      LAYER M4 ;
        RECT  64.692 45.744 64.776 45.768 ;
    END
  END a[325]
  PIN a[326]
    DIRECTION INPUT ;
    USE SIGNAL ;
    PORT
      LAYER M4 ;
        RECT  64.692 45.84 64.776 45.864 ;
    END
  END a[326]
  PIN a[327]
    DIRECTION INPUT ;
    USE SIGNAL ;
    PORT
      LAYER M4 ;
        RECT  64.692 45.936 64.776 45.96 ;
    END
  END a[327]
  PIN a[328]
    DIRECTION INPUT ;
    USE SIGNAL ;
    PORT
      LAYER M4 ;
        RECT  64.692 46.032 64.776 46.056 ;
    END
  END a[328]
  PIN a[329]
    DIRECTION INPUT ;
    USE SIGNAL ;
    PORT
      LAYER M4 ;
        RECT  64.692 46.128 64.776 46.152 ;
    END
  END a[329]
  PIN a[32]
    DIRECTION INPUT ;
    USE SIGNAL ;
    PORT
      LAYER M4 ;
        RECT  64.692 32.208 64.776 32.232 ;
    END
  END a[32]
  PIN a[330]
    DIRECTION INPUT ;
    USE SIGNAL ;
    PORT
      LAYER M4 ;
        RECT  64.692 46.224 64.776 46.248 ;
    END
  END a[330]
  PIN a[331]
    DIRECTION INPUT ;
    USE SIGNAL ;
    PORT
      LAYER M4 ;
        RECT  64.692 46.32 64.776 46.344 ;
    END
  END a[331]
  PIN a[332]
    DIRECTION INPUT ;
    USE SIGNAL ;
    PORT
      LAYER M4 ;
        RECT  64.692 46.416 64.776 46.44 ;
    END
  END a[332]
  PIN a[333]
    DIRECTION INPUT ;
    USE SIGNAL ;
    PORT
      LAYER M4 ;
        RECT  64.692 46.512 64.776 46.536 ;
    END
  END a[333]
  PIN a[334]
    DIRECTION INPUT ;
    USE SIGNAL ;
    PORT
      LAYER M4 ;
        RECT  64.692 46.608 64.776 46.632 ;
    END
  END a[334]
  PIN a[335]
    DIRECTION INPUT ;
    USE SIGNAL ;
    PORT
      LAYER M4 ;
        RECT  64.692 46.704 64.776 46.728 ;
    END
  END a[335]
  PIN a[336]
    DIRECTION INPUT ;
    USE SIGNAL ;
    PORT
      LAYER M4 ;
        RECT  64.692 46.8 64.776 46.824 ;
    END
  END a[336]
  PIN a[337]
    DIRECTION INPUT ;
    USE SIGNAL ;
    PORT
      LAYER M4 ;
        RECT  64.692 46.896 64.776 46.92 ;
    END
  END a[337]
  PIN a[338]
    DIRECTION INPUT ;
    USE SIGNAL ;
    PORT
      LAYER M4 ;
        RECT  64.692 46.992 64.776 47.016 ;
    END
  END a[338]
  PIN a[339]
    DIRECTION INPUT ;
    USE SIGNAL ;
    PORT
      LAYER M4 ;
        RECT  64.692 47.088 64.776 47.112 ;
    END
  END a[339]
  PIN a[33]
    DIRECTION INPUT ;
    USE SIGNAL ;
    PORT
      LAYER M4 ;
        RECT  64.692 32.304 64.776 32.328 ;
    END
  END a[33]
  PIN a[340]
    DIRECTION INPUT ;
    USE SIGNAL ;
    PORT
      LAYER M4 ;
        RECT  64.692 47.184 64.776 47.208 ;
    END
  END a[340]
  PIN a[341]
    DIRECTION INPUT ;
    USE SIGNAL ;
    PORT
      LAYER M4 ;
        RECT  64.692 47.28 64.776 47.304 ;
    END
  END a[341]
  PIN a[342]
    DIRECTION INPUT ;
    USE SIGNAL ;
    PORT
      LAYER M4 ;
        RECT  64.692 47.376 64.776 47.4 ;
    END
  END a[342]
  PIN a[343]
    DIRECTION INPUT ;
    USE SIGNAL ;
    PORT
      LAYER M4 ;
        RECT  64.692 47.472 64.776 47.496 ;
    END
  END a[343]
  PIN a[344]
    DIRECTION INPUT ;
    USE SIGNAL ;
    PORT
      LAYER M4 ;
        RECT  64.692 47.568 64.776 47.592 ;
    END
  END a[344]
  PIN a[345]
    DIRECTION INPUT ;
    USE SIGNAL ;
    PORT
      LAYER M4 ;
        RECT  64.692 47.664 64.776 47.688 ;
    END
  END a[345]
  PIN a[346]
    DIRECTION INPUT ;
    USE SIGNAL ;
    PORT
      LAYER M4 ;
        RECT  64.692 47.76 64.776 47.784 ;
    END
  END a[346]
  PIN a[347]
    DIRECTION INPUT ;
    USE SIGNAL ;
    PORT
      LAYER M4 ;
        RECT  64.692 47.856 64.776 47.88 ;
    END
  END a[347]
  PIN a[348]
    DIRECTION INPUT ;
    USE SIGNAL ;
    PORT
      LAYER M4 ;
        RECT  64.692 47.952 64.776 47.976 ;
    END
  END a[348]
  PIN a[349]
    DIRECTION INPUT ;
    USE SIGNAL ;
    PORT
      LAYER M4 ;
        RECT  64.692 48.048 64.776 48.072 ;
    END
  END a[349]
  PIN a[34]
    DIRECTION INPUT ;
    USE SIGNAL ;
    PORT
      LAYER M4 ;
        RECT  64.692 32.4 64.776 32.424 ;
    END
  END a[34]
  PIN a[350]
    DIRECTION INPUT ;
    USE SIGNAL ;
    PORT
      LAYER M4 ;
        RECT  64.692 48.144 64.776 48.168 ;
    END
  END a[350]
  PIN a[351]
    DIRECTION INPUT ;
    USE SIGNAL ;
    PORT
      LAYER M4 ;
        RECT  64.692 48.24 64.776 48.264 ;
    END
  END a[351]
  PIN a[352]
    DIRECTION INPUT ;
    USE SIGNAL ;
    PORT
      LAYER M4 ;
        RECT  64.692 3.792 64.776 3.816 ;
    END
  END a[352]
  PIN a[353]
    DIRECTION INPUT ;
    USE SIGNAL ;
    PORT
      LAYER M4 ;
        RECT  64.692 3.888 64.776 3.912 ;
    END
  END a[353]
  PIN a[354]
    DIRECTION INPUT ;
    USE SIGNAL ;
    PORT
      LAYER M4 ;
        RECT  64.692 3.984 64.776 4.008 ;
    END
  END a[354]
  PIN a[355]
    DIRECTION INPUT ;
    USE SIGNAL ;
    PORT
      LAYER M4 ;
        RECT  64.692 4.08 64.776 4.104 ;
    END
  END a[355]
  PIN a[356]
    DIRECTION INPUT ;
    USE SIGNAL ;
    PORT
      LAYER M4 ;
        RECT  64.692 4.176 64.776 4.2 ;
    END
  END a[356]
  PIN a[357]
    DIRECTION INPUT ;
    USE SIGNAL ;
    PORT
      LAYER M4 ;
        RECT  64.692 4.272 64.776 4.296 ;
    END
  END a[357]
  PIN a[358]
    DIRECTION INPUT ;
    USE SIGNAL ;
    PORT
      LAYER M4 ;
        RECT  64.692 4.368 64.776 4.392 ;
    END
  END a[358]
  PIN a[359]
    DIRECTION INPUT ;
    USE SIGNAL ;
    PORT
      LAYER M4 ;
        RECT  64.692 4.464 64.776 4.488 ;
    END
  END a[359]
  PIN a[35]
    DIRECTION INPUT ;
    USE SIGNAL ;
    PORT
      LAYER M4 ;
        RECT  64.692 32.496 64.776 32.52 ;
    END
  END a[35]
  PIN a[360]
    DIRECTION INPUT ;
    USE SIGNAL ;
    PORT
      LAYER M4 ;
        RECT  64.692 4.56 64.776 4.584 ;
    END
  END a[360]
  PIN a[361]
    DIRECTION INPUT ;
    USE SIGNAL ;
    PORT
      LAYER M4 ;
        RECT  64.692 4.656 64.776 4.68 ;
    END
  END a[361]
  PIN a[362]
    DIRECTION INPUT ;
    USE SIGNAL ;
    PORT
      LAYER M4 ;
        RECT  64.692 4.752 64.776 4.776 ;
    END
  END a[362]
  PIN a[363]
    DIRECTION INPUT ;
    USE SIGNAL ;
    PORT
      LAYER M4 ;
        RECT  64.692 4.848 64.776 4.872 ;
    END
  END a[363]
  PIN a[364]
    DIRECTION INPUT ;
    USE SIGNAL ;
    PORT
      LAYER M4 ;
        RECT  64.692 4.944 64.776 4.968 ;
    END
  END a[364]
  PIN a[365]
    DIRECTION INPUT ;
    USE SIGNAL ;
    PORT
      LAYER M4 ;
        RECT  64.692 5.04 64.776 5.064 ;
    END
  END a[365]
  PIN a[366]
    DIRECTION INPUT ;
    USE SIGNAL ;
    PORT
      LAYER M4 ;
        RECT  64.692 5.136 64.776 5.16 ;
    END
  END a[366]
  PIN a[367]
    DIRECTION INPUT ;
    USE SIGNAL ;
    PORT
      LAYER M4 ;
        RECT  64.692 5.232 64.776 5.256 ;
    END
  END a[367]
  PIN a[368]
    DIRECTION INPUT ;
    USE SIGNAL ;
    PORT
      LAYER M4 ;
        RECT  64.692 5.328 64.776 5.352 ;
    END
  END a[368]
  PIN a[369]
    DIRECTION INPUT ;
    USE SIGNAL ;
    PORT
      LAYER M4 ;
        RECT  64.692 5.424 64.776 5.448 ;
    END
  END a[369]
  PIN a[36]
    DIRECTION INPUT ;
    USE SIGNAL ;
    PORT
      LAYER M4 ;
        RECT  64.692 32.592 64.776 32.616 ;
    END
  END a[36]
  PIN a[370]
    DIRECTION INPUT ;
    USE SIGNAL ;
    PORT
      LAYER M4 ;
        RECT  64.692 5.52 64.776 5.544 ;
    END
  END a[370]
  PIN a[371]
    DIRECTION INPUT ;
    USE SIGNAL ;
    PORT
      LAYER M4 ;
        RECT  64.692 5.616 64.776 5.64 ;
    END
  END a[371]
  PIN a[372]
    DIRECTION INPUT ;
    USE SIGNAL ;
    PORT
      LAYER M4 ;
        RECT  64.692 5.712 64.776 5.736 ;
    END
  END a[372]
  PIN a[373]
    DIRECTION INPUT ;
    USE SIGNAL ;
    PORT
      LAYER M4 ;
        RECT  64.692 5.808 64.776 5.832 ;
    END
  END a[373]
  PIN a[374]
    DIRECTION INPUT ;
    USE SIGNAL ;
    PORT
      LAYER M4 ;
        RECT  64.692 5.904 64.776 5.928 ;
    END
  END a[374]
  PIN a[375]
    DIRECTION INPUT ;
    USE SIGNAL ;
    PORT
      LAYER M4 ;
        RECT  64.692 6 64.776 6.024 ;
    END
  END a[375]
  PIN a[376]
    DIRECTION INPUT ;
    USE SIGNAL ;
    PORT
      LAYER M4 ;
        RECT  64.692 6.096 64.776 6.12 ;
    END
  END a[376]
  PIN a[377]
    DIRECTION INPUT ;
    USE SIGNAL ;
    PORT
      LAYER M4 ;
        RECT  64.692 6.192 64.776 6.216 ;
    END
  END a[377]
  PIN a[378]
    DIRECTION INPUT ;
    USE SIGNAL ;
    PORT
      LAYER M4 ;
        RECT  64.692 6.288 64.776 6.312 ;
    END
  END a[378]
  PIN a[379]
    DIRECTION INPUT ;
    USE SIGNAL ;
    PORT
      LAYER M4 ;
        RECT  64.692 6.384 64.776 6.408 ;
    END
  END a[379]
  PIN a[37]
    DIRECTION INPUT ;
    USE SIGNAL ;
    PORT
      LAYER M4 ;
        RECT  64.692 32.688 64.776 32.712 ;
    END
  END a[37]
  PIN a[380]
    DIRECTION INPUT ;
    USE SIGNAL ;
    PORT
      LAYER M4 ;
        RECT  64.692 6.48 64.776 6.504 ;
    END
  END a[380]
  PIN a[381]
    DIRECTION INPUT ;
    USE SIGNAL ;
    PORT
      LAYER M4 ;
        RECT  64.692 6.576 64.776 6.6 ;
    END
  END a[381]
  PIN a[382]
    DIRECTION INPUT ;
    USE SIGNAL ;
    PORT
      LAYER M4 ;
        RECT  64.692 6.672 64.776 6.696 ;
    END
  END a[382]
  PIN a[383]
    DIRECTION INPUT ;
    USE SIGNAL ;
    PORT
      LAYER M4 ;
        RECT  64.692 6.768 64.776 6.792 ;
    END
  END a[383]
  PIN a[384]
    DIRECTION INPUT ;
    USE SIGNAL ;
    PORT
      LAYER M4 ;
        RECT  64.692 39.12 64.776 39.144 ;
    END
  END a[384]
  PIN a[385]
    DIRECTION INPUT ;
    USE SIGNAL ;
    PORT
      LAYER M4 ;
        RECT  64.692 39.216 64.776 39.24 ;
    END
  END a[385]
  PIN a[386]
    DIRECTION INPUT ;
    USE SIGNAL ;
    PORT
      LAYER M4 ;
        RECT  64.692 39.312 64.776 39.336 ;
    END
  END a[386]
  PIN a[387]
    DIRECTION INPUT ;
    USE SIGNAL ;
    PORT
      LAYER M4 ;
        RECT  64.692 39.408 64.776 39.432 ;
    END
  END a[387]
  PIN a[388]
    DIRECTION INPUT ;
    USE SIGNAL ;
    PORT
      LAYER M4 ;
        RECT  64.692 39.504 64.776 39.528 ;
    END
  END a[388]
  PIN a[389]
    DIRECTION INPUT ;
    USE SIGNAL ;
    PORT
      LAYER M4 ;
        RECT  64.692 39.6 64.776 39.624 ;
    END
  END a[389]
  PIN a[38]
    DIRECTION INPUT ;
    USE SIGNAL ;
    PORT
      LAYER M4 ;
        RECT  64.692 32.784 64.776 32.808 ;
    END
  END a[38]
  PIN a[390]
    DIRECTION INPUT ;
    USE SIGNAL ;
    PORT
      LAYER M4 ;
        RECT  64.692 39.696 64.776 39.72 ;
    END
  END a[390]
  PIN a[391]
    DIRECTION INPUT ;
    USE SIGNAL ;
    PORT
      LAYER M4 ;
        RECT  64.692 39.792 64.776 39.816 ;
    END
  END a[391]
  PIN a[392]
    DIRECTION INPUT ;
    USE SIGNAL ;
    PORT
      LAYER M4 ;
        RECT  64.692 39.888 64.776 39.912 ;
    END
  END a[392]
  PIN a[393]
    DIRECTION INPUT ;
    USE SIGNAL ;
    PORT
      LAYER M4 ;
        RECT  64.692 39.984 64.776 40.008 ;
    END
  END a[393]
  PIN a[394]
    DIRECTION INPUT ;
    USE SIGNAL ;
    PORT
      LAYER M4 ;
        RECT  64.692 40.08 64.776 40.104 ;
    END
  END a[394]
  PIN a[395]
    DIRECTION INPUT ;
    USE SIGNAL ;
    PORT
      LAYER M4 ;
        RECT  64.692 40.176 64.776 40.2 ;
    END
  END a[395]
  PIN a[396]
    DIRECTION INPUT ;
    USE SIGNAL ;
    PORT
      LAYER M4 ;
        RECT  64.692 40.272 64.776 40.296 ;
    END
  END a[396]
  PIN a[397]
    DIRECTION INPUT ;
    USE SIGNAL ;
    PORT
      LAYER M4 ;
        RECT  64.692 40.368 64.776 40.392 ;
    END
  END a[397]
  PIN a[398]
    DIRECTION INPUT ;
    USE SIGNAL ;
    PORT
      LAYER M4 ;
        RECT  64.692 40.464 64.776 40.488 ;
    END
  END a[398]
  PIN a[399]
    DIRECTION INPUT ;
    USE SIGNAL ;
    PORT
      LAYER M4 ;
        RECT  64.692 40.56 64.776 40.584 ;
    END
  END a[399]
  PIN a[39]
    DIRECTION INPUT ;
    USE SIGNAL ;
    PORT
      LAYER M4 ;
        RECT  64.692 32.88 64.776 32.904 ;
    END
  END a[39]
  PIN a[3]
    DIRECTION INPUT ;
    USE SIGNAL ;
    PORT
      LAYER M4 ;
        RECT  64.692 23.28 64.776 23.304 ;
    END
  END a[3]
  PIN a[400]
    DIRECTION INPUT ;
    USE SIGNAL ;
    PORT
      LAYER M4 ;
        RECT  64.692 40.656 64.776 40.68 ;
    END
  END a[400]
  PIN a[401]
    DIRECTION INPUT ;
    USE SIGNAL ;
    PORT
      LAYER M4 ;
        RECT  64.692 40.752 64.776 40.776 ;
    END
  END a[401]
  PIN a[402]
    DIRECTION INPUT ;
    USE SIGNAL ;
    PORT
      LAYER M4 ;
        RECT  64.692 40.848 64.776 40.872 ;
    END
  END a[402]
  PIN a[403]
    DIRECTION INPUT ;
    USE SIGNAL ;
    PORT
      LAYER M4 ;
        RECT  64.692 40.944 64.776 40.968 ;
    END
  END a[403]
  PIN a[404]
    DIRECTION INPUT ;
    USE SIGNAL ;
    PORT
      LAYER M4 ;
        RECT  64.692 41.04 64.776 41.064 ;
    END
  END a[404]
  PIN a[405]
    DIRECTION INPUT ;
    USE SIGNAL ;
    PORT
      LAYER M4 ;
        RECT  64.692 41.136 64.776 41.16 ;
    END
  END a[405]
  PIN a[406]
    DIRECTION INPUT ;
    USE SIGNAL ;
    PORT
      LAYER M4 ;
        RECT  64.692 41.232 64.776 41.256 ;
    END
  END a[406]
  PIN a[407]
    DIRECTION INPUT ;
    USE SIGNAL ;
    PORT
      LAYER M4 ;
        RECT  64.692 41.328 64.776 41.352 ;
    END
  END a[407]
  PIN a[408]
    DIRECTION INPUT ;
    USE SIGNAL ;
    PORT
      LAYER M4 ;
        RECT  64.692 41.424 64.776 41.448 ;
    END
  END a[408]
  PIN a[409]
    DIRECTION INPUT ;
    USE SIGNAL ;
    PORT
      LAYER M4 ;
        RECT  64.692 41.52 64.776 41.544 ;
    END
  END a[409]
  PIN a[40]
    DIRECTION INPUT ;
    USE SIGNAL ;
    PORT
      LAYER M4 ;
        RECT  64.692 32.976 64.776 33 ;
    END
  END a[40]
  PIN a[410]
    DIRECTION INPUT ;
    USE SIGNAL ;
    PORT
      LAYER M4 ;
        RECT  64.692 41.616 64.776 41.64 ;
    END
  END a[410]
  PIN a[411]
    DIRECTION INPUT ;
    USE SIGNAL ;
    PORT
      LAYER M4 ;
        RECT  64.692 41.712 64.776 41.736 ;
    END
  END a[411]
  PIN a[412]
    DIRECTION INPUT ;
    USE SIGNAL ;
    PORT
      LAYER M4 ;
        RECT  64.692 41.808 64.776 41.832 ;
    END
  END a[412]
  PIN a[413]
    DIRECTION INPUT ;
    USE SIGNAL ;
    PORT
      LAYER M4 ;
        RECT  64.692 41.904 64.776 41.928 ;
    END
  END a[413]
  PIN a[414]
    DIRECTION INPUT ;
    USE SIGNAL ;
    PORT
      LAYER M4 ;
        RECT  64.692 42 64.776 42.024 ;
    END
  END a[414]
  PIN a[415]
    DIRECTION INPUT ;
    USE SIGNAL ;
    PORT
      LAYER M4 ;
        RECT  64.692 42.096 64.776 42.12 ;
    END
  END a[415]
  PIN a[416]
    DIRECTION INPUT ;
    USE SIGNAL ;
    PORT
      LAYER M4 ;
        RECT  64.692 42.192 64.776 42.216 ;
    END
  END a[416]
  PIN a[417]
    DIRECTION INPUT ;
    USE SIGNAL ;
    PORT
      LAYER M4 ;
        RECT  64.692 42.288 64.776 42.312 ;
    END
  END a[417]
  PIN a[418]
    DIRECTION INPUT ;
    USE SIGNAL ;
    PORT
      LAYER M4 ;
        RECT  64.692 42.384 64.776 42.408 ;
    END
  END a[418]
  PIN a[419]
    DIRECTION INPUT ;
    USE SIGNAL ;
    PORT
      LAYER M4 ;
        RECT  64.692 42.48 64.776 42.504 ;
    END
  END a[419]
  PIN a[41]
    DIRECTION INPUT ;
    USE SIGNAL ;
    PORT
      LAYER M4 ;
        RECT  64.692 33.072 64.776 33.096 ;
    END
  END a[41]
  PIN a[420]
    DIRECTION INPUT ;
    USE SIGNAL ;
    PORT
      LAYER M4 ;
        RECT  64.692 42.576 64.776 42.6 ;
    END
  END a[420]
  PIN a[421]
    DIRECTION INPUT ;
    USE SIGNAL ;
    PORT
      LAYER M4 ;
        RECT  64.692 42.672 64.776 42.696 ;
    END
  END a[421]
  PIN a[422]
    DIRECTION INPUT ;
    USE SIGNAL ;
    PORT
      LAYER M4 ;
        RECT  64.692 42.768 64.776 42.792 ;
    END
  END a[422]
  PIN a[423]
    DIRECTION INPUT ;
    USE SIGNAL ;
    PORT
      LAYER M4 ;
        RECT  64.692 42.864 64.776 42.888 ;
    END
  END a[423]
  PIN a[424]
    DIRECTION INPUT ;
    USE SIGNAL ;
    PORT
      LAYER M4 ;
        RECT  64.692 42.96 64.776 42.984 ;
    END
  END a[424]
  PIN a[425]
    DIRECTION INPUT ;
    USE SIGNAL ;
    PORT
      LAYER M4 ;
        RECT  64.692 43.056 64.776 43.08 ;
    END
  END a[425]
  PIN a[426]
    DIRECTION INPUT ;
    USE SIGNAL ;
    PORT
      LAYER M4 ;
        RECT  64.692 43.152 64.776 43.176 ;
    END
  END a[426]
  PIN a[427]
    DIRECTION INPUT ;
    USE SIGNAL ;
    PORT
      LAYER M4 ;
        RECT  64.692 43.248 64.776 43.272 ;
    END
  END a[427]
  PIN a[428]
    DIRECTION INPUT ;
    USE SIGNAL ;
    PORT
      LAYER M4 ;
        RECT  64.692 43.344 64.776 43.368 ;
    END
  END a[428]
  PIN a[429]
    DIRECTION INPUT ;
    USE SIGNAL ;
    PORT
      LAYER M4 ;
        RECT  64.692 43.44 64.776 43.464 ;
    END
  END a[429]
  PIN a[42]
    DIRECTION INPUT ;
    USE SIGNAL ;
    PORT
      LAYER M4 ;
        RECT  64.692 33.168 64.776 33.192 ;
    END
  END a[42]
  PIN a[430]
    DIRECTION INPUT ;
    USE SIGNAL ;
    PORT
      LAYER M4 ;
        RECT  64.692 43.536 64.776 43.56 ;
    END
  END a[430]
  PIN a[431]
    DIRECTION INPUT ;
    USE SIGNAL ;
    PORT
      LAYER M4 ;
        RECT  64.692 43.632 64.776 43.656 ;
    END
  END a[431]
  PIN a[432]
    DIRECTION INPUT ;
    USE SIGNAL ;
    PORT
      LAYER M4 ;
        RECT  64.692 43.728 64.776 43.752 ;
    END
  END a[432]
  PIN a[433]
    DIRECTION INPUT ;
    USE SIGNAL ;
    PORT
      LAYER M4 ;
        RECT  64.692 43.824 64.776 43.848 ;
    END
  END a[433]
  PIN a[434]
    DIRECTION INPUT ;
    USE SIGNAL ;
    PORT
      LAYER M4 ;
        RECT  64.692 43.92 64.776 43.944 ;
    END
  END a[434]
  PIN a[435]
    DIRECTION INPUT ;
    USE SIGNAL ;
    PORT
      LAYER M4 ;
        RECT  64.692 44.016 64.776 44.04 ;
    END
  END a[435]
  PIN a[436]
    DIRECTION INPUT ;
    USE SIGNAL ;
    PORT
      LAYER M4 ;
        RECT  64.692 44.112 64.776 44.136 ;
    END
  END a[436]
  PIN a[437]
    DIRECTION INPUT ;
    USE SIGNAL ;
    PORT
      LAYER M4 ;
        RECT  64.692 44.208 64.776 44.232 ;
    END
  END a[437]
  PIN a[438]
    DIRECTION INPUT ;
    USE SIGNAL ;
    PORT
      LAYER M4 ;
        RECT  64.692 44.304 64.776 44.328 ;
    END
  END a[438]
  PIN a[439]
    DIRECTION INPUT ;
    USE SIGNAL ;
    PORT
      LAYER M4 ;
        RECT  64.692 44.4 64.776 44.424 ;
    END
  END a[439]
  PIN a[43]
    DIRECTION INPUT ;
    USE SIGNAL ;
    PORT
      LAYER M4 ;
        RECT  64.692 33.264 64.776 33.288 ;
    END
  END a[43]
  PIN a[440]
    DIRECTION INPUT ;
    USE SIGNAL ;
    PORT
      LAYER M4 ;
        RECT  64.692 44.496 64.776 44.52 ;
    END
  END a[440]
  PIN a[441]
    DIRECTION INPUT ;
    USE SIGNAL ;
    PORT
      LAYER M4 ;
        RECT  64.692 44.592 64.776 44.616 ;
    END
  END a[441]
  PIN a[442]
    DIRECTION INPUT ;
    USE SIGNAL ;
    PORT
      LAYER M4 ;
        RECT  64.692 44.688 64.776 44.712 ;
    END
  END a[442]
  PIN a[443]
    DIRECTION INPUT ;
    USE SIGNAL ;
    PORT
      LAYER M4 ;
        RECT  64.692 44.784 64.776 44.808 ;
    END
  END a[443]
  PIN a[444]
    DIRECTION INPUT ;
    USE SIGNAL ;
    PORT
      LAYER M4 ;
        RECT  64.692 44.88 64.776 44.904 ;
    END
  END a[444]
  PIN a[445]
    DIRECTION INPUT ;
    USE SIGNAL ;
    PORT
      LAYER M4 ;
        RECT  64.692 44.976 64.776 45 ;
    END
  END a[445]
  PIN a[446]
    DIRECTION INPUT ;
    USE SIGNAL ;
    PORT
      LAYER M4 ;
        RECT  64.692 45.072 64.776 45.096 ;
    END
  END a[446]
  PIN a[447]
    DIRECTION INPUT ;
    USE SIGNAL ;
    PORT
      LAYER M4 ;
        RECT  64.692 45.168 64.776 45.192 ;
    END
  END a[447]
  PIN a[448]
    DIRECTION INPUT ;
    USE SIGNAL ;
    PORT
      LAYER M4 ;
        RECT  64.692 9.936 64.776 9.96 ;
    END
  END a[448]
  PIN a[449]
    DIRECTION INPUT ;
    USE SIGNAL ;
    PORT
      LAYER M4 ;
        RECT  64.692 10.032 64.776 10.056 ;
    END
  END a[449]
  PIN a[44]
    DIRECTION INPUT ;
    USE SIGNAL ;
    PORT
      LAYER M4 ;
        RECT  64.692 33.36 64.776 33.384 ;
    END
  END a[44]
  PIN a[450]
    DIRECTION INPUT ;
    USE SIGNAL ;
    PORT
      LAYER M4 ;
        RECT  64.692 10.128 64.776 10.152 ;
    END
  END a[450]
  PIN a[451]
    DIRECTION INPUT ;
    USE SIGNAL ;
    PORT
      LAYER M4 ;
        RECT  64.692 10.224 64.776 10.248 ;
    END
  END a[451]
  PIN a[452]
    DIRECTION INPUT ;
    USE SIGNAL ;
    PORT
      LAYER M4 ;
        RECT  64.692 10.32 64.776 10.344 ;
    END
  END a[452]
  PIN a[453]
    DIRECTION INPUT ;
    USE SIGNAL ;
    PORT
      LAYER M4 ;
        RECT  64.692 10.416 64.776 10.44 ;
    END
  END a[453]
  PIN a[454]
    DIRECTION INPUT ;
    USE SIGNAL ;
    PORT
      LAYER M4 ;
        RECT  64.692 10.512 64.776 10.536 ;
    END
  END a[454]
  PIN a[455]
    DIRECTION INPUT ;
    USE SIGNAL ;
    PORT
      LAYER M4 ;
        RECT  64.692 10.608 64.776 10.632 ;
    END
  END a[455]
  PIN a[456]
    DIRECTION INPUT ;
    USE SIGNAL ;
    PORT
      LAYER M4 ;
        RECT  64.692 10.704 64.776 10.728 ;
    END
  END a[456]
  PIN a[457]
    DIRECTION INPUT ;
    USE SIGNAL ;
    PORT
      LAYER M4 ;
        RECT  64.692 10.8 64.776 10.824 ;
    END
  END a[457]
  PIN a[458]
    DIRECTION INPUT ;
    USE SIGNAL ;
    PORT
      LAYER M4 ;
        RECT  64.692 10.896 64.776 10.92 ;
    END
  END a[458]
  PIN a[459]
    DIRECTION INPUT ;
    USE SIGNAL ;
    PORT
      LAYER M4 ;
        RECT  64.692 10.992 64.776 11.016 ;
    END
  END a[459]
  PIN a[45]
    DIRECTION INPUT ;
    USE SIGNAL ;
    PORT
      LAYER M4 ;
        RECT  64.692 33.456 64.776 33.48 ;
    END
  END a[45]
  PIN a[460]
    DIRECTION INPUT ;
    USE SIGNAL ;
    PORT
      LAYER M4 ;
        RECT  64.692 11.088 64.776 11.112 ;
    END
  END a[460]
  PIN a[461]
    DIRECTION INPUT ;
    USE SIGNAL ;
    PORT
      LAYER M4 ;
        RECT  64.692 11.184 64.776 11.208 ;
    END
  END a[461]
  PIN a[462]
    DIRECTION INPUT ;
    USE SIGNAL ;
    PORT
      LAYER M4 ;
        RECT  64.692 11.28 64.776 11.304 ;
    END
  END a[462]
  PIN a[463]
    DIRECTION INPUT ;
    USE SIGNAL ;
    PORT
      LAYER M4 ;
        RECT  64.692 11.376 64.776 11.4 ;
    END
  END a[463]
  PIN a[464]
    DIRECTION INPUT ;
    USE SIGNAL ;
    PORT
      LAYER M4 ;
        RECT  64.692 11.472 64.776 11.496 ;
    END
  END a[464]
  PIN a[465]
    DIRECTION INPUT ;
    USE SIGNAL ;
    PORT
      LAYER M4 ;
        RECT  64.692 11.568 64.776 11.592 ;
    END
  END a[465]
  PIN a[466]
    DIRECTION INPUT ;
    USE SIGNAL ;
    PORT
      LAYER M4 ;
        RECT  64.692 11.664 64.776 11.688 ;
    END
  END a[466]
  PIN a[467]
    DIRECTION INPUT ;
    USE SIGNAL ;
    PORT
      LAYER M4 ;
        RECT  64.692 11.76 64.776 11.784 ;
    END
  END a[467]
  PIN a[468]
    DIRECTION INPUT ;
    USE SIGNAL ;
    PORT
      LAYER M4 ;
        RECT  64.692 11.856 64.776 11.88 ;
    END
  END a[468]
  PIN a[469]
    DIRECTION INPUT ;
    USE SIGNAL ;
    PORT
      LAYER M4 ;
        RECT  64.692 11.952 64.776 11.976 ;
    END
  END a[469]
  PIN a[46]
    DIRECTION INPUT ;
    USE SIGNAL ;
    PORT
      LAYER M4 ;
        RECT  64.692 33.552 64.776 33.576 ;
    END
  END a[46]
  PIN a[470]
    DIRECTION INPUT ;
    USE SIGNAL ;
    PORT
      LAYER M4 ;
        RECT  64.692 12.048 64.776 12.072 ;
    END
  END a[470]
  PIN a[471]
    DIRECTION INPUT ;
    USE SIGNAL ;
    PORT
      LAYER M4 ;
        RECT  64.692 12.144 64.776 12.168 ;
    END
  END a[471]
  PIN a[472]
    DIRECTION INPUT ;
    USE SIGNAL ;
    PORT
      LAYER M4 ;
        RECT  64.692 12.24 64.776 12.264 ;
    END
  END a[472]
  PIN a[473]
    DIRECTION INPUT ;
    USE SIGNAL ;
    PORT
      LAYER M4 ;
        RECT  64.692 12.336 64.776 12.36 ;
    END
  END a[473]
  PIN a[474]
    DIRECTION INPUT ;
    USE SIGNAL ;
    PORT
      LAYER M4 ;
        RECT  64.692 12.432 64.776 12.456 ;
    END
  END a[474]
  PIN a[475]
    DIRECTION INPUT ;
    USE SIGNAL ;
    PORT
      LAYER M4 ;
        RECT  64.692 12.528 64.776 12.552 ;
    END
  END a[475]
  PIN a[476]
    DIRECTION INPUT ;
    USE SIGNAL ;
    PORT
      LAYER M4 ;
        RECT  64.692 12.624 64.776 12.648 ;
    END
  END a[476]
  PIN a[477]
    DIRECTION INPUT ;
    USE SIGNAL ;
    PORT
      LAYER M4 ;
        RECT  64.692 12.72 64.776 12.744 ;
    END
  END a[477]
  PIN a[478]
    DIRECTION INPUT ;
    USE SIGNAL ;
    PORT
      LAYER M4 ;
        RECT  64.692 12.816 64.776 12.84 ;
    END
  END a[478]
  PIN a[479]
    DIRECTION INPUT ;
    USE SIGNAL ;
    PORT
      LAYER M4 ;
        RECT  64.692 12.912 64.776 12.936 ;
    END
  END a[479]
  PIN a[47]
    DIRECTION INPUT ;
    USE SIGNAL ;
    PORT
      LAYER M4 ;
        RECT  64.692 33.648 64.776 33.672 ;
    END
  END a[47]
  PIN a[480]
    DIRECTION INPUT ;
    USE SIGNAL ;
    PORT
      LAYER M4 ;
        RECT  64.692 13.008 64.776 13.032 ;
    END
  END a[480]
  PIN a[481]
    DIRECTION INPUT ;
    USE SIGNAL ;
    PORT
      LAYER M4 ;
        RECT  64.692 13.104 64.776 13.128 ;
    END
  END a[481]
  PIN a[482]
    DIRECTION INPUT ;
    USE SIGNAL ;
    PORT
      LAYER M4 ;
        RECT  64.692 13.2 64.776 13.224 ;
    END
  END a[482]
  PIN a[483]
    DIRECTION INPUT ;
    USE SIGNAL ;
    PORT
      LAYER M4 ;
        RECT  64.692 13.296 64.776 13.32 ;
    END
  END a[483]
  PIN a[484]
    DIRECTION INPUT ;
    USE SIGNAL ;
    PORT
      LAYER M4 ;
        RECT  64.692 13.392 64.776 13.416 ;
    END
  END a[484]
  PIN a[485]
    DIRECTION INPUT ;
    USE SIGNAL ;
    PORT
      LAYER M4 ;
        RECT  64.692 13.488 64.776 13.512 ;
    END
  END a[485]
  PIN a[486]
    DIRECTION INPUT ;
    USE SIGNAL ;
    PORT
      LAYER M4 ;
        RECT  64.692 13.584 64.776 13.608 ;
    END
  END a[486]
  PIN a[487]
    DIRECTION INPUT ;
    USE SIGNAL ;
    PORT
      LAYER M4 ;
        RECT  64.692 13.68 64.776 13.704 ;
    END
  END a[487]
  PIN a[488]
    DIRECTION INPUT ;
    USE SIGNAL ;
    PORT
      LAYER M4 ;
        RECT  64.692 13.776 64.776 13.8 ;
    END
  END a[488]
  PIN a[489]
    DIRECTION INPUT ;
    USE SIGNAL ;
    PORT
      LAYER M4 ;
        RECT  64.692 13.872 64.776 13.896 ;
    END
  END a[489]
  PIN a[48]
    DIRECTION INPUT ;
    USE SIGNAL ;
    PORT
      LAYER M4 ;
        RECT  64.692 33.744 64.776 33.768 ;
    END
  END a[48]
  PIN a[490]
    DIRECTION INPUT ;
    USE SIGNAL ;
    PORT
      LAYER M4 ;
        RECT  64.692 13.968 64.776 13.992 ;
    END
  END a[490]
  PIN a[491]
    DIRECTION INPUT ;
    USE SIGNAL ;
    PORT
      LAYER M4 ;
        RECT  64.692 14.064 64.776 14.088 ;
    END
  END a[491]
  PIN a[492]
    DIRECTION INPUT ;
    USE SIGNAL ;
    PORT
      LAYER M4 ;
        RECT  64.692 14.16 64.776 14.184 ;
    END
  END a[492]
  PIN a[493]
    DIRECTION INPUT ;
    USE SIGNAL ;
    PORT
      LAYER M4 ;
        RECT  64.692 14.256 64.776 14.28 ;
    END
  END a[493]
  PIN a[494]
    DIRECTION INPUT ;
    USE SIGNAL ;
    PORT
      LAYER M4 ;
        RECT  64.692 14.352 64.776 14.376 ;
    END
  END a[494]
  PIN a[495]
    DIRECTION INPUT ;
    USE SIGNAL ;
    PORT
      LAYER M4 ;
        RECT  64.692 14.448 64.776 14.472 ;
    END
  END a[495]
  PIN a[496]
    DIRECTION INPUT ;
    USE SIGNAL ;
    PORT
      LAYER M4 ;
        RECT  64.692 14.544 64.776 14.568 ;
    END
  END a[496]
  PIN a[497]
    DIRECTION INPUT ;
    USE SIGNAL ;
    PORT
      LAYER M4 ;
        RECT  64.692 14.64 64.776 14.664 ;
    END
  END a[497]
  PIN a[498]
    DIRECTION INPUT ;
    USE SIGNAL ;
    PORT
      LAYER M4 ;
        RECT  64.692 14.736 64.776 14.76 ;
    END
  END a[498]
  PIN a[499]
    DIRECTION INPUT ;
    USE SIGNAL ;
    PORT
      LAYER M4 ;
        RECT  64.692 14.832 64.776 14.856 ;
    END
  END a[499]
  PIN a[49]
    DIRECTION INPUT ;
    USE SIGNAL ;
    PORT
      LAYER M4 ;
        RECT  64.692 33.84 64.776 33.864 ;
    END
  END a[49]
  PIN a[4]
    DIRECTION INPUT ;
    USE SIGNAL ;
    PORT
      LAYER M4 ;
        RECT  64.692 23.376 64.776 23.4 ;
    END
  END a[4]
  PIN a[500]
    DIRECTION INPUT ;
    USE SIGNAL ;
    PORT
      LAYER M4 ;
        RECT  64.692 14.928 64.776 14.952 ;
    END
  END a[500]
  PIN a[501]
    DIRECTION INPUT ;
    USE SIGNAL ;
    PORT
      LAYER M4 ;
        RECT  64.692 15.024 64.776 15.048 ;
    END
  END a[501]
  PIN a[502]
    DIRECTION INPUT ;
    USE SIGNAL ;
    PORT
      LAYER M4 ;
        RECT  64.692 15.12 64.776 15.144 ;
    END
  END a[502]
  PIN a[503]
    DIRECTION INPUT ;
    USE SIGNAL ;
    PORT
      LAYER M4 ;
        RECT  64.692 15.216 64.776 15.24 ;
    END
  END a[503]
  PIN a[504]
    DIRECTION INPUT ;
    USE SIGNAL ;
    PORT
      LAYER M4 ;
        RECT  64.692 15.312 64.776 15.336 ;
    END
  END a[504]
  PIN a[505]
    DIRECTION INPUT ;
    USE SIGNAL ;
    PORT
      LAYER M4 ;
        RECT  64.692 15.408 64.776 15.432 ;
    END
  END a[505]
  PIN a[506]
    DIRECTION INPUT ;
    USE SIGNAL ;
    PORT
      LAYER M4 ;
        RECT  64.692 15.504 64.776 15.528 ;
    END
  END a[506]
  PIN a[507]
    DIRECTION INPUT ;
    USE SIGNAL ;
    PORT
      LAYER M4 ;
        RECT  64.692 15.6 64.776 15.624 ;
    END
  END a[507]
  PIN a[508]
    DIRECTION INPUT ;
    USE SIGNAL ;
    PORT
      LAYER M4 ;
        RECT  64.692 15.696 64.776 15.72 ;
    END
  END a[508]
  PIN a[509]
    DIRECTION INPUT ;
    USE SIGNAL ;
    PORT
      LAYER M4 ;
        RECT  64.692 15.792 64.776 15.816 ;
    END
  END a[509]
  PIN a[50]
    DIRECTION INPUT ;
    USE SIGNAL ;
    PORT
      LAYER M4 ;
        RECT  64.692 33.936 64.776 33.96 ;
    END
  END a[50]
  PIN a[510]
    DIRECTION INPUT ;
    USE SIGNAL ;
    PORT
      LAYER M4 ;
        RECT  64.692 15.888 64.776 15.912 ;
    END
  END a[510]
  PIN a[511]
    DIRECTION INPUT ;
    USE SIGNAL ;
    PORT
      LAYER M4 ;
        RECT  64.692 15.984 64.776 16.008 ;
    END
  END a[511]
  PIN a[512]
    DIRECTION INPUT ;
    USE SIGNAL ;
    PORT
      LAYER M4 ;
        RECT  64.692 6.864 64.776 6.888 ;
    END
  END a[512]
  PIN a[513]
    DIRECTION INPUT ;
    USE SIGNAL ;
    PORT
      LAYER M4 ;
        RECT  64.692 6.96 64.776 6.984 ;
    END
  END a[513]
  PIN a[514]
    DIRECTION INPUT ;
    USE SIGNAL ;
    PORT
      LAYER M4 ;
        RECT  64.692 7.056 64.776 7.08 ;
    END
  END a[514]
  PIN a[515]
    DIRECTION INPUT ;
    USE SIGNAL ;
    PORT
      LAYER M4 ;
        RECT  64.692 7.152 64.776 7.176 ;
    END
  END a[515]
  PIN a[516]
    DIRECTION INPUT ;
    USE SIGNAL ;
    PORT
      LAYER M4 ;
        RECT  64.692 7.248 64.776 7.272 ;
    END
  END a[516]
  PIN a[517]
    DIRECTION INPUT ;
    USE SIGNAL ;
    PORT
      LAYER M4 ;
        RECT  64.692 7.344 64.776 7.368 ;
    END
  END a[517]
  PIN a[518]
    DIRECTION INPUT ;
    USE SIGNAL ;
    PORT
      LAYER M4 ;
        RECT  64.692 7.44 64.776 7.464 ;
    END
  END a[518]
  PIN a[519]
    DIRECTION INPUT ;
    USE SIGNAL ;
    PORT
      LAYER M4 ;
        RECT  64.692 7.536 64.776 7.56 ;
    END
  END a[519]
  PIN a[51]
    DIRECTION INPUT ;
    USE SIGNAL ;
    PORT
      LAYER M4 ;
        RECT  64.692 34.032 64.776 34.056 ;
    END
  END a[51]
  PIN a[520]
    DIRECTION INPUT ;
    USE SIGNAL ;
    PORT
      LAYER M4 ;
        RECT  64.692 7.632 64.776 7.656 ;
    END
  END a[520]
  PIN a[521]
    DIRECTION INPUT ;
    USE SIGNAL ;
    PORT
      LAYER M4 ;
        RECT  64.692 7.728 64.776 7.752 ;
    END
  END a[521]
  PIN a[522]
    DIRECTION INPUT ;
    USE SIGNAL ;
    PORT
      LAYER M4 ;
        RECT  64.692 7.824 64.776 7.848 ;
    END
  END a[522]
  PIN a[523]
    DIRECTION INPUT ;
    USE SIGNAL ;
    PORT
      LAYER M4 ;
        RECT  64.692 7.92 64.776 7.944 ;
    END
  END a[523]
  PIN a[524]
    DIRECTION INPUT ;
    USE SIGNAL ;
    PORT
      LAYER M4 ;
        RECT  64.692 8.016 64.776 8.04 ;
    END
  END a[524]
  PIN a[525]
    DIRECTION INPUT ;
    USE SIGNAL ;
    PORT
      LAYER M4 ;
        RECT  64.692 8.112 64.776 8.136 ;
    END
  END a[525]
  PIN a[526]
    DIRECTION INPUT ;
    USE SIGNAL ;
    PORT
      LAYER M4 ;
        RECT  64.692 8.208 64.776 8.232 ;
    END
  END a[526]
  PIN a[527]
    DIRECTION INPUT ;
    USE SIGNAL ;
    PORT
      LAYER M4 ;
        RECT  64.692 8.304 64.776 8.328 ;
    END
  END a[527]
  PIN a[528]
    DIRECTION INPUT ;
    USE SIGNAL ;
    PORT
      LAYER M4 ;
        RECT  64.692 8.4 64.776 8.424 ;
    END
  END a[528]
  PIN a[529]
    DIRECTION INPUT ;
    USE SIGNAL ;
    PORT
      LAYER M4 ;
        RECT  64.692 8.496 64.776 8.52 ;
    END
  END a[529]
  PIN a[52]
    DIRECTION INPUT ;
    USE SIGNAL ;
    PORT
      LAYER M4 ;
        RECT  64.692 34.128 64.776 34.152 ;
    END
  END a[52]
  PIN a[530]
    DIRECTION INPUT ;
    USE SIGNAL ;
    PORT
      LAYER M4 ;
        RECT  64.692 8.592 64.776 8.616 ;
    END
  END a[530]
  PIN a[531]
    DIRECTION INPUT ;
    USE SIGNAL ;
    PORT
      LAYER M4 ;
        RECT  64.692 8.688 64.776 8.712 ;
    END
  END a[531]
  PIN a[532]
    DIRECTION INPUT ;
    USE SIGNAL ;
    PORT
      LAYER M4 ;
        RECT  64.692 8.784 64.776 8.808 ;
    END
  END a[532]
  PIN a[533]
    DIRECTION INPUT ;
    USE SIGNAL ;
    PORT
      LAYER M4 ;
        RECT  64.692 8.88 64.776 8.904 ;
    END
  END a[533]
  PIN a[534]
    DIRECTION INPUT ;
    USE SIGNAL ;
    PORT
      LAYER M4 ;
        RECT  64.692 8.976 64.776 9 ;
    END
  END a[534]
  PIN a[535]
    DIRECTION INPUT ;
    USE SIGNAL ;
    PORT
      LAYER M4 ;
        RECT  64.692 9.072 64.776 9.096 ;
    END
  END a[535]
  PIN a[536]
    DIRECTION INPUT ;
    USE SIGNAL ;
    PORT
      LAYER M4 ;
        RECT  64.692 9.168 64.776 9.192 ;
    END
  END a[536]
  PIN a[537]
    DIRECTION INPUT ;
    USE SIGNAL ;
    PORT
      LAYER M4 ;
        RECT  64.692 9.264 64.776 9.288 ;
    END
  END a[537]
  PIN a[538]
    DIRECTION INPUT ;
    USE SIGNAL ;
    PORT
      LAYER M4 ;
        RECT  64.692 9.36 64.776 9.384 ;
    END
  END a[538]
  PIN a[539]
    DIRECTION INPUT ;
    USE SIGNAL ;
    PORT
      LAYER M4 ;
        RECT  64.692 9.456 64.776 9.48 ;
    END
  END a[539]
  PIN a[53]
    DIRECTION INPUT ;
    USE SIGNAL ;
    PORT
      LAYER M4 ;
        RECT  64.692 34.224 64.776 34.248 ;
    END
  END a[53]
  PIN a[540]
    DIRECTION INPUT ;
    USE SIGNAL ;
    PORT
      LAYER M4 ;
        RECT  64.692 9.552 64.776 9.576 ;
    END
  END a[540]
  PIN a[541]
    DIRECTION INPUT ;
    USE SIGNAL ;
    PORT
      LAYER M4 ;
        RECT  64.692 9.648 64.776 9.672 ;
    END
  END a[541]
  PIN a[542]
    DIRECTION INPUT ;
    USE SIGNAL ;
    PORT
      LAYER M4 ;
        RECT  64.692 9.744 64.776 9.768 ;
    END
  END a[542]
  PIN a[543]
    DIRECTION INPUT ;
    USE SIGNAL ;
    PORT
      LAYER M4 ;
        RECT  64.692 9.84 64.776 9.864 ;
    END
  END a[543]
  PIN a[544]
    DIRECTION INPUT ;
    USE SIGNAL ;
    PORT
      LAYER M4 ;
        RECT  64.692 38.352 64.776 38.376 ;
    END
  END a[544]
  PIN a[545]
    DIRECTION INPUT ;
    USE SIGNAL ;
    PORT
      LAYER M4 ;
        RECT  64.692 38.448 64.776 38.472 ;
    END
  END a[545]
  PIN a[546]
    DIRECTION INPUT ;
    USE SIGNAL ;
    PORT
      LAYER M4 ;
        RECT  64.692 38.544 64.776 38.568 ;
    END
  END a[546]
  PIN a[547]
    DIRECTION INPUT ;
    USE SIGNAL ;
    PORT
      LAYER M4 ;
        RECT  64.692 38.64 64.776 38.664 ;
    END
  END a[547]
  PIN a[54]
    DIRECTION INPUT ;
    USE SIGNAL ;
    PORT
      LAYER M4 ;
        RECT  64.692 34.32 64.776 34.344 ;
    END
  END a[54]
  PIN a[55]
    DIRECTION INPUT ;
    USE SIGNAL ;
    PORT
      LAYER M4 ;
        RECT  64.692 34.416 64.776 34.44 ;
    END
  END a[55]
  PIN a[56]
    DIRECTION INPUT ;
    USE SIGNAL ;
    PORT
      LAYER M4 ;
        RECT  64.692 34.512 64.776 34.536 ;
    END
  END a[56]
  PIN a[57]
    DIRECTION INPUT ;
    USE SIGNAL ;
    PORT
      LAYER M4 ;
        RECT  64.692 34.608 64.776 34.632 ;
    END
  END a[57]
  PIN a[58]
    DIRECTION INPUT ;
    USE SIGNAL ;
    PORT
      LAYER M4 ;
        RECT  64.692 34.704 64.776 34.728 ;
    END
  END a[58]
  PIN a[59]
    DIRECTION INPUT ;
    USE SIGNAL ;
    PORT
      LAYER M4 ;
        RECT  64.692 34.8 64.776 34.824 ;
    END
  END a[59]
  PIN a[5]
    DIRECTION INPUT ;
    USE SIGNAL ;
    PORT
      LAYER M4 ;
        RECT  64.692 23.472 64.776 23.496 ;
    END
  END a[5]
  PIN a[60]
    DIRECTION INPUT ;
    USE SIGNAL ;
    PORT
      LAYER M4 ;
        RECT  64.692 34.896 64.776 34.92 ;
    END
  END a[60]
  PIN a[61]
    DIRECTION INPUT ;
    USE SIGNAL ;
    PORT
      LAYER M4 ;
        RECT  64.692 34.992 64.776 35.016 ;
    END
  END a[61]
  PIN a[62]
    DIRECTION INPUT ;
    USE SIGNAL ;
    PORT
      LAYER M4 ;
        RECT  64.692 35.088 64.776 35.112 ;
    END
  END a[62]
  PIN a[63]
    DIRECTION INPUT ;
    USE SIGNAL ;
    PORT
      LAYER M4 ;
        RECT  64.692 35.184 64.776 35.208 ;
    END
  END a[63]
  PIN a[64]
    DIRECTION INPUT ;
    USE SIGNAL ;
    PORT
      LAYER M4 ;
        RECT  64.692 19.92 64.776 19.944 ;
    END
  END a[64]
  PIN a[65]
    DIRECTION INPUT ;
    USE SIGNAL ;
    PORT
      LAYER M4 ;
        RECT  64.692 20.016 64.776 20.04 ;
    END
  END a[65]
  PIN a[66]
    DIRECTION INPUT ;
    USE SIGNAL ;
    PORT
      LAYER M4 ;
        RECT  64.692 20.112 64.776 20.136 ;
    END
  END a[66]
  PIN a[67]
    DIRECTION INPUT ;
    USE SIGNAL ;
    PORT
      LAYER M4 ;
        RECT  64.692 20.208 64.776 20.232 ;
    END
  END a[67]
  PIN a[68]
    DIRECTION INPUT ;
    USE SIGNAL ;
    PORT
      LAYER M4 ;
        RECT  64.692 20.304 64.776 20.328 ;
    END
  END a[68]
  PIN a[69]
    DIRECTION INPUT ;
    USE SIGNAL ;
    PORT
      LAYER M4 ;
        RECT  64.692 20.4 64.776 20.424 ;
    END
  END a[69]
  PIN a[6]
    DIRECTION INPUT ;
    USE SIGNAL ;
    PORT
      LAYER M4 ;
        RECT  64.692 23.568 64.776 23.592 ;
    END
  END a[6]
  PIN a[70]
    DIRECTION INPUT ;
    USE SIGNAL ;
    PORT
      LAYER M4 ;
        RECT  64.692 20.496 64.776 20.52 ;
    END
  END a[70]
  PIN a[71]
    DIRECTION INPUT ;
    USE SIGNAL ;
    PORT
      LAYER M4 ;
        RECT  64.692 20.592 64.776 20.616 ;
    END
  END a[71]
  PIN a[72]
    DIRECTION INPUT ;
    USE SIGNAL ;
    PORT
      LAYER M4 ;
        RECT  64.692 20.688 64.776 20.712 ;
    END
  END a[72]
  PIN a[73]
    DIRECTION INPUT ;
    USE SIGNAL ;
    PORT
      LAYER M4 ;
        RECT  64.692 20.784 64.776 20.808 ;
    END
  END a[73]
  PIN a[74]
    DIRECTION INPUT ;
    USE SIGNAL ;
    PORT
      LAYER M4 ;
        RECT  64.692 20.88 64.776 20.904 ;
    END
  END a[74]
  PIN a[75]
    DIRECTION INPUT ;
    USE SIGNAL ;
    PORT
      LAYER M4 ;
        RECT  64.692 20.976 64.776 21 ;
    END
  END a[75]
  PIN a[76]
    DIRECTION INPUT ;
    USE SIGNAL ;
    PORT
      LAYER M4 ;
        RECT  64.692 21.072 64.776 21.096 ;
    END
  END a[76]
  PIN a[77]
    DIRECTION INPUT ;
    USE SIGNAL ;
    PORT
      LAYER M4 ;
        RECT  64.692 21.168 64.776 21.192 ;
    END
  END a[77]
  PIN a[78]
    DIRECTION INPUT ;
    USE SIGNAL ;
    PORT
      LAYER M4 ;
        RECT  64.692 21.264 64.776 21.288 ;
    END
  END a[78]
  PIN a[79]
    DIRECTION INPUT ;
    USE SIGNAL ;
    PORT
      LAYER M4 ;
        RECT  64.692 21.36 64.776 21.384 ;
    END
  END a[79]
  PIN a[7]
    DIRECTION INPUT ;
    USE SIGNAL ;
    PORT
      LAYER M4 ;
        RECT  64.692 23.664 64.776 23.688 ;
    END
  END a[7]
  PIN a[80]
    DIRECTION INPUT ;
    USE SIGNAL ;
    PORT
      LAYER M4 ;
        RECT  64.692 21.456 64.776 21.48 ;
    END
  END a[80]
  PIN a[81]
    DIRECTION INPUT ;
    USE SIGNAL ;
    PORT
      LAYER M4 ;
        RECT  64.692 21.552 64.776 21.576 ;
    END
  END a[81]
  PIN a[82]
    DIRECTION INPUT ;
    USE SIGNAL ;
    PORT
      LAYER M4 ;
        RECT  64.692 21.648 64.776 21.672 ;
    END
  END a[82]
  PIN a[83]
    DIRECTION INPUT ;
    USE SIGNAL ;
    PORT
      LAYER M4 ;
        RECT  64.692 21.744 64.776 21.768 ;
    END
  END a[83]
  PIN a[84]
    DIRECTION INPUT ;
    USE SIGNAL ;
    PORT
      LAYER M4 ;
        RECT  64.692 21.84 64.776 21.864 ;
    END
  END a[84]
  PIN a[85]
    DIRECTION INPUT ;
    USE SIGNAL ;
    PORT
      LAYER M4 ;
        RECT  64.692 21.936 64.776 21.96 ;
    END
  END a[85]
  PIN a[86]
    DIRECTION INPUT ;
    USE SIGNAL ;
    PORT
      LAYER M4 ;
        RECT  64.692 22.032 64.776 22.056 ;
    END
  END a[86]
  PIN a[87]
    DIRECTION INPUT ;
    USE SIGNAL ;
    PORT
      LAYER M4 ;
        RECT  64.692 22.128 64.776 22.152 ;
    END
  END a[87]
  PIN a[88]
    DIRECTION INPUT ;
    USE SIGNAL ;
    PORT
      LAYER M4 ;
        RECT  64.692 22.224 64.776 22.248 ;
    END
  END a[88]
  PIN a[89]
    DIRECTION INPUT ;
    USE SIGNAL ;
    PORT
      LAYER M4 ;
        RECT  64.692 22.32 64.776 22.344 ;
    END
  END a[89]
  PIN a[8]
    DIRECTION INPUT ;
    USE SIGNAL ;
    PORT
      LAYER M4 ;
        RECT  64.692 23.76 64.776 23.784 ;
    END
  END a[8]
  PIN a[90]
    DIRECTION INPUT ;
    USE SIGNAL ;
    PORT
      LAYER M4 ;
        RECT  64.692 22.416 64.776 22.44 ;
    END
  END a[90]
  PIN a[91]
    DIRECTION INPUT ;
    USE SIGNAL ;
    PORT
      LAYER M4 ;
        RECT  64.692 22.512 64.776 22.536 ;
    END
  END a[91]
  PIN a[92]
    DIRECTION INPUT ;
    USE SIGNAL ;
    PORT
      LAYER M4 ;
        RECT  64.692 22.608 64.776 22.632 ;
    END
  END a[92]
  PIN a[93]
    DIRECTION INPUT ;
    USE SIGNAL ;
    PORT
      LAYER M4 ;
        RECT  64.692 22.704 64.776 22.728 ;
    END
  END a[93]
  PIN a[94]
    DIRECTION INPUT ;
    USE SIGNAL ;
    PORT
      LAYER M4 ;
        RECT  64.692 22.8 64.776 22.824 ;
    END
  END a[94]
  PIN a[95]
    DIRECTION INPUT ;
    USE SIGNAL ;
    PORT
      LAYER M4 ;
        RECT  64.692 22.896 64.776 22.92 ;
    END
  END a[95]
  PIN a[96]
    DIRECTION INPUT ;
    USE SIGNAL ;
    PORT
      LAYER M4 ;
        RECT  64.692 29.136 64.776 29.16 ;
    END
  END a[96]
  PIN a[97]
    DIRECTION INPUT ;
    USE SIGNAL ;
    PORT
      LAYER M4 ;
        RECT  64.692 29.232 64.776 29.256 ;
    END
  END a[97]
  PIN a[98]
    DIRECTION INPUT ;
    USE SIGNAL ;
    PORT
      LAYER M4 ;
        RECT  64.692 29.328 64.776 29.352 ;
    END
  END a[98]
  PIN a[99]
    DIRECTION INPUT ;
    USE SIGNAL ;
    PORT
      LAYER M4 ;
        RECT  64.692 29.424 64.776 29.448 ;
    END
  END a[99]
  PIN a[9]
    DIRECTION INPUT ;
    USE SIGNAL ;
    PORT
      LAYER M4 ;
        RECT  64.692 23.856 64.776 23.88 ;
    END
  END a[9]
  PIN b[0]
    DIRECTION OUTPUT ;
    USE SIGNAL ;
    PORT
      LAYER M3 ;
        RECT  21.636 60.419 21.654 60.456 ;
    END
  END b[0]
  PIN b[100]
    DIRECTION OUTPUT ;
    USE SIGNAL ;
    PORT
      LAYER M5 ;
        RECT  42.192 60.372 42.216 60.456 ;
    END
  END b[100]
  PIN b[101]
    DIRECTION OUTPUT ;
    USE SIGNAL ;
    PORT
      LAYER M5 ;
        RECT  42.288 60.372 42.312 60.456 ;
    END
  END b[101]
  PIN b[102]
    DIRECTION OUTPUT ;
    USE SIGNAL ;
    PORT
      LAYER M5 ;
        RECT  42.384 60.372 42.408 60.456 ;
    END
  END b[102]
  PIN b[103]
    DIRECTION OUTPUT ;
    USE SIGNAL ;
    PORT
      LAYER M5 ;
        RECT  42.48 60.372 42.504 60.456 ;
    END
  END b[103]
  PIN b[104]
    DIRECTION OUTPUT ;
    USE SIGNAL ;
    PORT
      LAYER M5 ;
        RECT  42.576 60.372 42.6 60.456 ;
    END
  END b[104]
  PIN b[105]
    DIRECTION OUTPUT ;
    USE SIGNAL ;
    PORT
      LAYER M5 ;
        RECT  42.672 60.372 42.696 60.456 ;
    END
  END b[105]
  PIN b[106]
    DIRECTION OUTPUT ;
    USE SIGNAL ;
    PORT
      LAYER M5 ;
        RECT  42.768 60.372 42.792 60.456 ;
    END
  END b[106]
  PIN b[107]
    DIRECTION OUTPUT ;
    USE SIGNAL ;
    PORT
      LAYER M5 ;
        RECT  42.864 60.372 42.888 60.456 ;
    END
  END b[107]
  PIN b[108]
    DIRECTION OUTPUT ;
    USE SIGNAL ;
    PORT
      LAYER M5 ;
        RECT  42.96 60.372 42.984 60.456 ;
    END
  END b[108]
  PIN b[109]
    DIRECTION OUTPUT ;
    USE SIGNAL ;
    PORT
      LAYER M5 ;
        RECT  43.056 60.372 43.08 60.456 ;
    END
  END b[109]
  PIN b[10]
    DIRECTION OUTPUT ;
    USE SIGNAL ;
    PORT
      LAYER M3 ;
        RECT  22.356 60.419 22.374 60.456 ;
    END
  END b[10]
  PIN b[110]
    DIRECTION OUTPUT ;
    USE SIGNAL ;
    PORT
      LAYER M5 ;
        RECT  43.152 60.372 43.176 60.456 ;
    END
  END b[110]
  PIN b[111]
    DIRECTION OUTPUT ;
    USE SIGNAL ;
    PORT
      LAYER M5 ;
        RECT  43.248 60.372 43.272 60.456 ;
    END
  END b[111]
  PIN b[112]
    DIRECTION OUTPUT ;
    USE SIGNAL ;
    PORT
      LAYER M5 ;
        RECT  43.344 60.372 43.368 60.456 ;
    END
  END b[112]
  PIN b[113]
    DIRECTION OUTPUT ;
    USE SIGNAL ;
    PORT
      LAYER M5 ;
        RECT  43.44 60.372 43.464 60.456 ;
    END
  END b[113]
  PIN b[114]
    DIRECTION OUTPUT ;
    USE SIGNAL ;
    PORT
      LAYER M5 ;
        RECT  43.536 60.372 43.56 60.456 ;
    END
  END b[114]
  PIN b[115]
    DIRECTION OUTPUT ;
    USE SIGNAL ;
    PORT
      LAYER M5 ;
        RECT  43.632 60.372 43.656 60.456 ;
    END
  END b[115]
  PIN b[116]
    DIRECTION OUTPUT ;
    USE SIGNAL ;
    PORT
      LAYER M5 ;
        RECT  43.728 60.372 43.752 60.456 ;
    END
  END b[116]
  PIN b[117]
    DIRECTION OUTPUT ;
    USE SIGNAL ;
    PORT
      LAYER M5 ;
        RECT  43.824 60.372 43.848 60.456 ;
    END
  END b[117]
  PIN b[118]
    DIRECTION OUTPUT ;
    USE SIGNAL ;
    PORT
      LAYER M5 ;
        RECT  43.92 60.372 43.944 60.456 ;
    END
  END b[118]
  PIN b[119]
    DIRECTION OUTPUT ;
    USE SIGNAL ;
    PORT
      LAYER M5 ;
        RECT  44.016 60.372 44.04 60.456 ;
    END
  END b[119]
  PIN b[11]
    DIRECTION OUTPUT ;
    USE SIGNAL ;
    PORT
      LAYER M3 ;
        RECT  22.428 60.419 22.446 60.456 ;
    END
  END b[11]
  PIN b[120]
    DIRECTION OUTPUT ;
    USE SIGNAL ;
    PORT
      LAYER M5 ;
        RECT  44.112 60.372 44.136 60.456 ;
    END
  END b[120]
  PIN b[121]
    DIRECTION OUTPUT ;
    USE SIGNAL ;
    PORT
      LAYER M5 ;
        RECT  44.208 60.372 44.232 60.456 ;
    END
  END b[121]
  PIN b[122]
    DIRECTION OUTPUT ;
    USE SIGNAL ;
    PORT
      LAYER M5 ;
        RECT  44.304 60.372 44.328 60.456 ;
    END
  END b[122]
  PIN b[123]
    DIRECTION OUTPUT ;
    USE SIGNAL ;
    PORT
      LAYER M5 ;
        RECT  44.4 60.372 44.424 60.456 ;
    END
  END b[123]
  PIN b[124]
    DIRECTION OUTPUT ;
    USE SIGNAL ;
    PORT
      LAYER M5 ;
        RECT  44.496 60.372 44.52 60.456 ;
    END
  END b[124]
  PIN b[125]
    DIRECTION OUTPUT ;
    USE SIGNAL ;
    PORT
      LAYER M5 ;
        RECT  44.592 60.372 44.616 60.456 ;
    END
  END b[125]
  PIN b[126]
    DIRECTION OUTPUT ;
    USE SIGNAL ;
    PORT
      LAYER M5 ;
        RECT  44.688 60.372 44.712 60.456 ;
    END
  END b[126]
  PIN b[127]
    DIRECTION OUTPUT ;
    USE SIGNAL ;
    PORT
      LAYER M5 ;
        RECT  44.784 60.372 44.808 60.456 ;
    END
  END b[127]
  PIN b[128]
    DIRECTION OUTPUT ;
    USE SIGNAL ;
    PORT
      LAYER M5 ;
        RECT  32.592 60.372 32.616 60.456 ;
    END
  END b[128]
  PIN b[129]
    DIRECTION OUTPUT ;
    USE SIGNAL ;
    PORT
      LAYER M5 ;
        RECT  32.688 60.372 32.712 60.456 ;
    END
  END b[129]
  PIN b[12]
    DIRECTION OUTPUT ;
    USE SIGNAL ;
    PORT
      LAYER M3 ;
        RECT  22.5 60.419 22.518 60.456 ;
    END
  END b[12]
  PIN b[130]
    DIRECTION OUTPUT ;
    USE SIGNAL ;
    PORT
      LAYER M5 ;
        RECT  32.784 60.372 32.808 60.456 ;
    END
  END b[130]
  PIN b[131]
    DIRECTION OUTPUT ;
    USE SIGNAL ;
    PORT
      LAYER M5 ;
        RECT  32.88 60.372 32.904 60.456 ;
    END
  END b[131]
  PIN b[132]
    DIRECTION OUTPUT ;
    USE SIGNAL ;
    PORT
      LAYER M5 ;
        RECT  32.976 60.372 33 60.456 ;
    END
  END b[132]
  PIN b[133]
    DIRECTION OUTPUT ;
    USE SIGNAL ;
    PORT
      LAYER M5 ;
        RECT  33.072 60.372 33.096 60.456 ;
    END
  END b[133]
  PIN b[134]
    DIRECTION OUTPUT ;
    USE SIGNAL ;
    PORT
      LAYER M5 ;
        RECT  33.168 60.372 33.192 60.456 ;
    END
  END b[134]
  PIN b[135]
    DIRECTION OUTPUT ;
    USE SIGNAL ;
    PORT
      LAYER M5 ;
        RECT  33.264 60.372 33.288 60.456 ;
    END
  END b[135]
  PIN b[136]
    DIRECTION OUTPUT ;
    USE SIGNAL ;
    PORT
      LAYER M5 ;
        RECT  33.36 60.372 33.384 60.456 ;
    END
  END b[136]
  PIN b[137]
    DIRECTION OUTPUT ;
    USE SIGNAL ;
    PORT
      LAYER M5 ;
        RECT  33.456 60.372 33.48 60.456 ;
    END
  END b[137]
  PIN b[138]
    DIRECTION OUTPUT ;
    USE SIGNAL ;
    PORT
      LAYER M5 ;
        RECT  33.552 60.372 33.576 60.456 ;
    END
  END b[138]
  PIN b[139]
    DIRECTION OUTPUT ;
    USE SIGNAL ;
    PORT
      LAYER M5 ;
        RECT  33.648 60.372 33.672 60.456 ;
    END
  END b[139]
  PIN b[13]
    DIRECTION OUTPUT ;
    USE SIGNAL ;
    PORT
      LAYER M3 ;
        RECT  22.572 60.419 22.59 60.456 ;
    END
  END b[13]
  PIN b[140]
    DIRECTION OUTPUT ;
    USE SIGNAL ;
    PORT
      LAYER M5 ;
        RECT  33.744 60.372 33.768 60.456 ;
    END
  END b[140]
  PIN b[141]
    DIRECTION OUTPUT ;
    USE SIGNAL ;
    PORT
      LAYER M5 ;
        RECT  33.84 60.372 33.864 60.456 ;
    END
  END b[141]
  PIN b[142]
    DIRECTION OUTPUT ;
    USE SIGNAL ;
    PORT
      LAYER M5 ;
        RECT  33.936 60.372 33.96 60.456 ;
    END
  END b[142]
  PIN b[143]
    DIRECTION OUTPUT ;
    USE SIGNAL ;
    PORT
      LAYER M5 ;
        RECT  34.032 60.372 34.056 60.456 ;
    END
  END b[143]
  PIN b[144]
    DIRECTION OUTPUT ;
    USE SIGNAL ;
    PORT
      LAYER M5 ;
        RECT  34.128 60.372 34.152 60.456 ;
    END
  END b[144]
  PIN b[145]
    DIRECTION OUTPUT ;
    USE SIGNAL ;
    PORT
      LAYER M5 ;
        RECT  34.224 60.372 34.248 60.456 ;
    END
  END b[145]
  PIN b[146]
    DIRECTION OUTPUT ;
    USE SIGNAL ;
    PORT
      LAYER M5 ;
        RECT  34.32 60.372 34.344 60.456 ;
    END
  END b[146]
  PIN b[147]
    DIRECTION OUTPUT ;
    USE SIGNAL ;
    PORT
      LAYER M5 ;
        RECT  34.416 60.372 34.44 60.456 ;
    END
  END b[147]
  PIN b[148]
    DIRECTION OUTPUT ;
    USE SIGNAL ;
    PORT
      LAYER M5 ;
        RECT  34.512 60.372 34.536 60.456 ;
    END
  END b[148]
  PIN b[149]
    DIRECTION OUTPUT ;
    USE SIGNAL ;
    PORT
      LAYER M5 ;
        RECT  34.608 60.372 34.632 60.456 ;
    END
  END b[149]
  PIN b[14]
    DIRECTION OUTPUT ;
    USE SIGNAL ;
    PORT
      LAYER M3 ;
        RECT  22.644 60.419 22.662 60.456 ;
    END
  END b[14]
  PIN b[150]
    DIRECTION OUTPUT ;
    USE SIGNAL ;
    PORT
      LAYER M5 ;
        RECT  34.704 60.372 34.728 60.456 ;
    END
  END b[150]
  PIN b[151]
    DIRECTION OUTPUT ;
    USE SIGNAL ;
    PORT
      LAYER M5 ;
        RECT  34.8 60.372 34.824 60.456 ;
    END
  END b[151]
  PIN b[152]
    DIRECTION OUTPUT ;
    USE SIGNAL ;
    PORT
      LAYER M5 ;
        RECT  34.896 60.372 34.92 60.456 ;
    END
  END b[152]
  PIN b[153]
    DIRECTION OUTPUT ;
    USE SIGNAL ;
    PORT
      LAYER M5 ;
        RECT  34.992 60.372 35.016 60.456 ;
    END
  END b[153]
  PIN b[154]
    DIRECTION OUTPUT ;
    USE SIGNAL ;
    PORT
      LAYER M5 ;
        RECT  35.088 60.372 35.112 60.456 ;
    END
  END b[154]
  PIN b[155]
    DIRECTION OUTPUT ;
    USE SIGNAL ;
    PORT
      LAYER M5 ;
        RECT  35.184 60.372 35.208 60.456 ;
    END
  END b[155]
  PIN b[156]
    DIRECTION OUTPUT ;
    USE SIGNAL ;
    PORT
      LAYER M5 ;
        RECT  35.28 60.372 35.304 60.456 ;
    END
  END b[156]
  PIN b[157]
    DIRECTION OUTPUT ;
    USE SIGNAL ;
    PORT
      LAYER M5 ;
        RECT  35.376 60.372 35.4 60.456 ;
    END
  END b[157]
  PIN b[158]
    DIRECTION OUTPUT ;
    USE SIGNAL ;
    PORT
      LAYER M5 ;
        RECT  35.472 60.372 35.496 60.456 ;
    END
  END b[158]
  PIN b[159]
    DIRECTION OUTPUT ;
    USE SIGNAL ;
    PORT
      LAYER M5 ;
        RECT  35.568 60.372 35.592 60.456 ;
    END
  END b[159]
  PIN b[15]
    DIRECTION OUTPUT ;
    USE SIGNAL ;
    PORT
      LAYER M3 ;
        RECT  22.716 60.419 22.734 60.456 ;
    END
  END b[15]
  PIN b[160]
    DIRECTION OUTPUT ;
    USE SIGNAL ;
    PORT
      LAYER M5 ;
        RECT  38.736 60.372 38.76 60.456 ;
    END
  END b[160]
  PIN b[161]
    DIRECTION OUTPUT ;
    USE SIGNAL ;
    PORT
      LAYER M5 ;
        RECT  38.832 60.372 38.856 60.456 ;
    END
  END b[161]
  PIN b[162]
    DIRECTION OUTPUT ;
    USE SIGNAL ;
    PORT
      LAYER M5 ;
        RECT  38.928 60.372 38.952 60.456 ;
    END
  END b[162]
  PIN b[163]
    DIRECTION OUTPUT ;
    USE SIGNAL ;
    PORT
      LAYER M5 ;
        RECT  39.024 60.372 39.048 60.456 ;
    END
  END b[163]
  PIN b[164]
    DIRECTION OUTPUT ;
    USE SIGNAL ;
    PORT
      LAYER M5 ;
        RECT  39.12 60.372 39.144 60.456 ;
    END
  END b[164]
  PIN b[165]
    DIRECTION OUTPUT ;
    USE SIGNAL ;
    PORT
      LAYER M5 ;
        RECT  39.216 60.372 39.24 60.456 ;
    END
  END b[165]
  PIN b[166]
    DIRECTION OUTPUT ;
    USE SIGNAL ;
    PORT
      LAYER M5 ;
        RECT  39.312 60.372 39.336 60.456 ;
    END
  END b[166]
  PIN b[167]
    DIRECTION OUTPUT ;
    USE SIGNAL ;
    PORT
      LAYER M5 ;
        RECT  39.408 60.372 39.432 60.456 ;
    END
  END b[167]
  PIN b[168]
    DIRECTION OUTPUT ;
    USE SIGNAL ;
    PORT
      LAYER M5 ;
        RECT  39.504 60.372 39.528 60.456 ;
    END
  END b[168]
  PIN b[169]
    DIRECTION OUTPUT ;
    USE SIGNAL ;
    PORT
      LAYER M5 ;
        RECT  39.6 60.372 39.624 60.456 ;
    END
  END b[169]
  PIN b[16]
    DIRECTION OUTPUT ;
    USE SIGNAL ;
    PORT
      LAYER M3 ;
        RECT  22.788 60.419 22.806 60.456 ;
    END
  END b[16]
  PIN b[170]
    DIRECTION OUTPUT ;
    USE SIGNAL ;
    PORT
      LAYER M5 ;
        RECT  39.696 60.372 39.72 60.456 ;
    END
  END b[170]
  PIN b[171]
    DIRECTION OUTPUT ;
    USE SIGNAL ;
    PORT
      LAYER M5 ;
        RECT  39.792 60.372 39.816 60.456 ;
    END
  END b[171]
  PIN b[172]
    DIRECTION OUTPUT ;
    USE SIGNAL ;
    PORT
      LAYER M5 ;
        RECT  39.888 60.372 39.912 60.456 ;
    END
  END b[172]
  PIN b[173]
    DIRECTION OUTPUT ;
    USE SIGNAL ;
    PORT
      LAYER M5 ;
        RECT  39.984 60.372 40.008 60.456 ;
    END
  END b[173]
  PIN b[174]
    DIRECTION OUTPUT ;
    USE SIGNAL ;
    PORT
      LAYER M5 ;
        RECT  40.08 60.372 40.104 60.456 ;
    END
  END b[174]
  PIN b[175]
    DIRECTION OUTPUT ;
    USE SIGNAL ;
    PORT
      LAYER M5 ;
        RECT  40.176 60.372 40.2 60.456 ;
    END
  END b[175]
  PIN b[176]
    DIRECTION OUTPUT ;
    USE SIGNAL ;
    PORT
      LAYER M5 ;
        RECT  40.272 60.372 40.296 60.456 ;
    END
  END b[176]
  PIN b[177]
    DIRECTION OUTPUT ;
    USE SIGNAL ;
    PORT
      LAYER M5 ;
        RECT  40.368 60.372 40.392 60.456 ;
    END
  END b[177]
  PIN b[178]
    DIRECTION OUTPUT ;
    USE SIGNAL ;
    PORT
      LAYER M5 ;
        RECT  40.464 60.372 40.488 60.456 ;
    END
  END b[178]
  PIN b[179]
    DIRECTION OUTPUT ;
    USE SIGNAL ;
    PORT
      LAYER M5 ;
        RECT  40.56 60.372 40.584 60.456 ;
    END
  END b[179]
  PIN b[17]
    DIRECTION OUTPUT ;
    USE SIGNAL ;
    PORT
      LAYER M3 ;
        RECT  22.86 60.419 22.878 60.456 ;
    END
  END b[17]
  PIN b[180]
    DIRECTION OUTPUT ;
    USE SIGNAL ;
    PORT
      LAYER M5 ;
        RECT  40.656 60.372 40.68 60.456 ;
    END
  END b[180]
  PIN b[181]
    DIRECTION OUTPUT ;
    USE SIGNAL ;
    PORT
      LAYER M5 ;
        RECT  40.752 60.372 40.776 60.456 ;
    END
  END b[181]
  PIN b[182]
    DIRECTION OUTPUT ;
    USE SIGNAL ;
    PORT
      LAYER M5 ;
        RECT  40.848 60.372 40.872 60.456 ;
    END
  END b[182]
  PIN b[183]
    DIRECTION OUTPUT ;
    USE SIGNAL ;
    PORT
      LAYER M5 ;
        RECT  40.944 60.372 40.968 60.456 ;
    END
  END b[183]
  PIN b[184]
    DIRECTION OUTPUT ;
    USE SIGNAL ;
    PORT
      LAYER M5 ;
        RECT  41.04 60.372 41.064 60.456 ;
    END
  END b[184]
  PIN b[185]
    DIRECTION OUTPUT ;
    USE SIGNAL ;
    PORT
      LAYER M5 ;
        RECT  41.136 60.372 41.16 60.456 ;
    END
  END b[185]
  PIN b[186]
    DIRECTION OUTPUT ;
    USE SIGNAL ;
    PORT
      LAYER M5 ;
        RECT  41.232 60.372 41.256 60.456 ;
    END
  END b[186]
  PIN b[187]
    DIRECTION OUTPUT ;
    USE SIGNAL ;
    PORT
      LAYER M5 ;
        RECT  41.328 60.372 41.352 60.456 ;
    END
  END b[187]
  PIN b[188]
    DIRECTION OUTPUT ;
    USE SIGNAL ;
    PORT
      LAYER M5 ;
        RECT  41.424 60.372 41.448 60.456 ;
    END
  END b[188]
  PIN b[189]
    DIRECTION OUTPUT ;
    USE SIGNAL ;
    PORT
      LAYER M5 ;
        RECT  41.52 60.372 41.544 60.456 ;
    END
  END b[189]
  PIN b[18]
    DIRECTION OUTPUT ;
    USE SIGNAL ;
    PORT
      LAYER M3 ;
        RECT  22.932 60.419 22.95 60.456 ;
    END
  END b[18]
  PIN b[190]
    DIRECTION OUTPUT ;
    USE SIGNAL ;
    PORT
      LAYER M5 ;
        RECT  41.616 60.372 41.64 60.456 ;
    END
  END b[190]
  PIN b[191]
    DIRECTION OUTPUT ;
    USE SIGNAL ;
    PORT
      LAYER M5 ;
        RECT  41.712 60.372 41.736 60.456 ;
    END
  END b[191]
  PIN b[192]
    DIRECTION OUTPUT ;
    USE SIGNAL ;
    PORT
      LAYER M5 ;
        RECT  26.448 60.372 26.472 60.456 ;
    END
  END b[192]
  PIN b[193]
    DIRECTION OUTPUT ;
    USE SIGNAL ;
    PORT
      LAYER M5 ;
        RECT  26.544 60.372 26.568 60.456 ;
    END
  END b[193]
  PIN b[194]
    DIRECTION OUTPUT ;
    USE SIGNAL ;
    PORT
      LAYER M5 ;
        RECT  26.64 60.372 26.664 60.456 ;
    END
  END b[194]
  PIN b[195]
    DIRECTION OUTPUT ;
    USE SIGNAL ;
    PORT
      LAYER M5 ;
        RECT  26.736 60.372 26.76 60.456 ;
    END
  END b[195]
  PIN b[196]
    DIRECTION OUTPUT ;
    USE SIGNAL ;
    PORT
      LAYER M5 ;
        RECT  26.832 60.372 26.856 60.456 ;
    END
  END b[196]
  PIN b[197]
    DIRECTION OUTPUT ;
    USE SIGNAL ;
    PORT
      LAYER M5 ;
        RECT  26.928 60.372 26.952 60.456 ;
    END
  END b[197]
  PIN b[198]
    DIRECTION OUTPUT ;
    USE SIGNAL ;
    PORT
      LAYER M5 ;
        RECT  27.024 60.372 27.048 60.456 ;
    END
  END b[198]
  PIN b[199]
    DIRECTION OUTPUT ;
    USE SIGNAL ;
    PORT
      LAYER M5 ;
        RECT  27.12 60.372 27.144 60.456 ;
    END
  END b[199]
  PIN b[19]
    DIRECTION OUTPUT ;
    USE SIGNAL ;
    PORT
      LAYER M3 ;
        RECT  23.004 60.419 23.022 60.456 ;
    END
  END b[19]
  PIN b[1]
    DIRECTION OUTPUT ;
    USE SIGNAL ;
    PORT
      LAYER M3 ;
        RECT  21.708 60.419 21.726 60.456 ;
    END
  END b[1]
  PIN b[200]
    DIRECTION OUTPUT ;
    USE SIGNAL ;
    PORT
      LAYER M5 ;
        RECT  27.216 60.372 27.24 60.456 ;
    END
  END b[200]
  PIN b[201]
    DIRECTION OUTPUT ;
    USE SIGNAL ;
    PORT
      LAYER M5 ;
        RECT  27.312 60.372 27.336 60.456 ;
    END
  END b[201]
  PIN b[202]
    DIRECTION OUTPUT ;
    USE SIGNAL ;
    PORT
      LAYER M5 ;
        RECT  27.408 60.372 27.432 60.456 ;
    END
  END b[202]
  PIN b[203]
    DIRECTION OUTPUT ;
    USE SIGNAL ;
    PORT
      LAYER M5 ;
        RECT  27.504 60.372 27.528 60.456 ;
    END
  END b[203]
  PIN b[204]
    DIRECTION OUTPUT ;
    USE SIGNAL ;
    PORT
      LAYER M5 ;
        RECT  27.6 60.372 27.624 60.456 ;
    END
  END b[204]
  PIN b[205]
    DIRECTION OUTPUT ;
    USE SIGNAL ;
    PORT
      LAYER M5 ;
        RECT  27.696 60.372 27.72 60.456 ;
    END
  END b[205]
  PIN b[206]
    DIRECTION OUTPUT ;
    USE SIGNAL ;
    PORT
      LAYER M5 ;
        RECT  27.792 60.372 27.816 60.456 ;
    END
  END b[206]
  PIN b[207]
    DIRECTION OUTPUT ;
    USE SIGNAL ;
    PORT
      LAYER M5 ;
        RECT  27.888 60.372 27.912 60.456 ;
    END
  END b[207]
  PIN b[208]
    DIRECTION OUTPUT ;
    USE SIGNAL ;
    PORT
      LAYER M5 ;
        RECT  27.984 60.372 28.008 60.456 ;
    END
  END b[208]
  PIN b[209]
    DIRECTION OUTPUT ;
    USE SIGNAL ;
    PORT
      LAYER M5 ;
        RECT  28.08 60.372 28.104 60.456 ;
    END
  END b[209]
  PIN b[20]
    DIRECTION OUTPUT ;
    USE SIGNAL ;
    PORT
      LAYER M3 ;
        RECT  23.076 60.419 23.094 60.456 ;
    END
  END b[20]
  PIN b[210]
    DIRECTION OUTPUT ;
    USE SIGNAL ;
    PORT
      LAYER M5 ;
        RECT  28.176 60.372 28.2 60.456 ;
    END
  END b[210]
  PIN b[211]
    DIRECTION OUTPUT ;
    USE SIGNAL ;
    PORT
      LAYER M5 ;
        RECT  28.272 60.372 28.296 60.456 ;
    END
  END b[211]
  PIN b[212]
    DIRECTION OUTPUT ;
    USE SIGNAL ;
    PORT
      LAYER M5 ;
        RECT  28.368 60.372 28.392 60.456 ;
    END
  END b[212]
  PIN b[213]
    DIRECTION OUTPUT ;
    USE SIGNAL ;
    PORT
      LAYER M5 ;
        RECT  28.464 60.372 28.488 60.456 ;
    END
  END b[213]
  PIN b[214]
    DIRECTION OUTPUT ;
    USE SIGNAL ;
    PORT
      LAYER M5 ;
        RECT  28.56 60.372 28.584 60.456 ;
    END
  END b[214]
  PIN b[215]
    DIRECTION OUTPUT ;
    USE SIGNAL ;
    PORT
      LAYER M5 ;
        RECT  28.656 60.372 28.68 60.456 ;
    END
  END b[215]
  PIN b[216]
    DIRECTION OUTPUT ;
    USE SIGNAL ;
    PORT
      LAYER M5 ;
        RECT  28.752 60.372 28.776 60.456 ;
    END
  END b[216]
  PIN b[217]
    DIRECTION OUTPUT ;
    USE SIGNAL ;
    PORT
      LAYER M5 ;
        RECT  28.848 60.372 28.872 60.456 ;
    END
  END b[217]
  PIN b[218]
    DIRECTION OUTPUT ;
    USE SIGNAL ;
    PORT
      LAYER M5 ;
        RECT  28.944 60.372 28.968 60.456 ;
    END
  END b[218]
  PIN b[219]
    DIRECTION OUTPUT ;
    USE SIGNAL ;
    PORT
      LAYER M5 ;
        RECT  29.04 60.372 29.064 60.456 ;
    END
  END b[219]
  PIN b[21]
    DIRECTION OUTPUT ;
    USE SIGNAL ;
    PORT
      LAYER M3 ;
        RECT  23.148 60.419 23.166 60.456 ;
    END
  END b[21]
  PIN b[220]
    DIRECTION OUTPUT ;
    USE SIGNAL ;
    PORT
      LAYER M5 ;
        RECT  29.136 60.372 29.16 60.456 ;
    END
  END b[220]
  PIN b[221]
    DIRECTION OUTPUT ;
    USE SIGNAL ;
    PORT
      LAYER M5 ;
        RECT  29.232 60.372 29.256 60.456 ;
    END
  END b[221]
  PIN b[222]
    DIRECTION OUTPUT ;
    USE SIGNAL ;
    PORT
      LAYER M5 ;
        RECT  29.328 60.372 29.352 60.456 ;
    END
  END b[222]
  PIN b[223]
    DIRECTION OUTPUT ;
    USE SIGNAL ;
    PORT
      LAYER M5 ;
        RECT  29.424 60.372 29.448 60.456 ;
    END
  END b[223]
  PIN b[224]
    DIRECTION OUTPUT ;
    USE SIGNAL ;
    PORT
      LAYER M3 ;
        RECT  26.244 60.419 26.262 60.456 ;
    END
  END b[224]
  PIN b[225]
    DIRECTION OUTPUT ;
    USE SIGNAL ;
    PORT
      LAYER M3 ;
        RECT  26.316 60.419 26.334 60.456 ;
    END
  END b[225]
  PIN b[226]
    DIRECTION OUTPUT ;
    USE SIGNAL ;
    PORT
      LAYER M3 ;
        RECT  26.388 60.419 26.406 60.456 ;
    END
  END b[226]
  PIN b[227]
    DIRECTION OUTPUT ;
    USE SIGNAL ;
    PORT
      LAYER M3 ;
        RECT  26.46 60.419 26.478 60.456 ;
    END
  END b[227]
  PIN b[228]
    DIRECTION OUTPUT ;
    USE SIGNAL ;
    PORT
      LAYER M3 ;
        RECT  26.532 60.419 26.55 60.456 ;
    END
  END b[228]
  PIN b[229]
    DIRECTION OUTPUT ;
    USE SIGNAL ;
    PORT
      LAYER M3 ;
        RECT  26.604 60.419 26.622 60.456 ;
    END
  END b[229]
  PIN b[22]
    DIRECTION OUTPUT ;
    USE SIGNAL ;
    PORT
      LAYER M3 ;
        RECT  23.22 60.419 23.238 60.456 ;
    END
  END b[22]
  PIN b[230]
    DIRECTION OUTPUT ;
    USE SIGNAL ;
    PORT
      LAYER M3 ;
        RECT  26.676 60.419 26.694 60.456 ;
    END
  END b[230]
  PIN b[231]
    DIRECTION OUTPUT ;
    USE SIGNAL ;
    PORT
      LAYER M3 ;
        RECT  26.748 60.419 26.766 60.456 ;
    END
  END b[231]
  PIN b[232]
    DIRECTION OUTPUT ;
    USE SIGNAL ;
    PORT
      LAYER M3 ;
        RECT  26.82 60.419 26.838 60.456 ;
    END
  END b[232]
  PIN b[233]
    DIRECTION OUTPUT ;
    USE SIGNAL ;
    PORT
      LAYER M3 ;
        RECT  26.892 60.419 26.91 60.456 ;
    END
  END b[233]
  PIN b[234]
    DIRECTION OUTPUT ;
    USE SIGNAL ;
    PORT
      LAYER M3 ;
        RECT  26.964 60.419 26.982 60.456 ;
    END
  END b[234]
  PIN b[235]
    DIRECTION OUTPUT ;
    USE SIGNAL ;
    PORT
      LAYER M3 ;
        RECT  27.036 60.419 27.054 60.456 ;
    END
  END b[235]
  PIN b[236]
    DIRECTION OUTPUT ;
    USE SIGNAL ;
    PORT
      LAYER M3 ;
        RECT  27.108 60.419 27.126 60.456 ;
    END
  END b[236]
  PIN b[237]
    DIRECTION OUTPUT ;
    USE SIGNAL ;
    PORT
      LAYER M3 ;
        RECT  27.18 60.419 27.198 60.456 ;
    END
  END b[237]
  PIN b[238]
    DIRECTION OUTPUT ;
    USE SIGNAL ;
    PORT
      LAYER M3 ;
        RECT  27.252 60.419 27.27 60.456 ;
    END
  END b[238]
  PIN b[239]
    DIRECTION OUTPUT ;
    USE SIGNAL ;
    PORT
      LAYER M3 ;
        RECT  27.324 60.419 27.342 60.456 ;
    END
  END b[239]
  PIN b[23]
    DIRECTION OUTPUT ;
    USE SIGNAL ;
    PORT
      LAYER M3 ;
        RECT  23.292 60.419 23.31 60.456 ;
    END
  END b[23]
  PIN b[240]
    DIRECTION OUTPUT ;
    USE SIGNAL ;
    PORT
      LAYER M3 ;
        RECT  27.396 60.419 27.414 60.456 ;
    END
  END b[240]
  PIN b[241]
    DIRECTION OUTPUT ;
    USE SIGNAL ;
    PORT
      LAYER M3 ;
        RECT  27.468 60.419 27.486 60.456 ;
    END
  END b[241]
  PIN b[242]
    DIRECTION OUTPUT ;
    USE SIGNAL ;
    PORT
      LAYER M3 ;
        RECT  27.54 60.419 27.558 60.456 ;
    END
  END b[242]
  PIN b[243]
    DIRECTION OUTPUT ;
    USE SIGNAL ;
    PORT
      LAYER M3 ;
        RECT  27.612 60.419 27.63 60.456 ;
    END
  END b[243]
  PIN b[244]
    DIRECTION OUTPUT ;
    USE SIGNAL ;
    PORT
      LAYER M3 ;
        RECT  27.684 60.419 27.702 60.456 ;
    END
  END b[244]
  PIN b[245]
    DIRECTION OUTPUT ;
    USE SIGNAL ;
    PORT
      LAYER M3 ;
        RECT  27.756 60.419 27.774 60.456 ;
    END
  END b[245]
  PIN b[246]
    DIRECTION OUTPUT ;
    USE SIGNAL ;
    PORT
      LAYER M3 ;
        RECT  27.828 60.419 27.846 60.456 ;
    END
  END b[246]
  PIN b[247]
    DIRECTION OUTPUT ;
    USE SIGNAL ;
    PORT
      LAYER M3 ;
        RECT  27.9 60.419 27.918 60.456 ;
    END
  END b[247]
  PIN b[248]
    DIRECTION OUTPUT ;
    USE SIGNAL ;
    PORT
      LAYER M3 ;
        RECT  27.972 60.419 27.99 60.456 ;
    END
  END b[248]
  PIN b[249]
    DIRECTION OUTPUT ;
    USE SIGNAL ;
    PORT
      LAYER M3 ;
        RECT  28.044 60.419 28.062 60.456 ;
    END
  END b[249]
  PIN b[24]
    DIRECTION OUTPUT ;
    USE SIGNAL ;
    PORT
      LAYER M3 ;
        RECT  23.364 60.419 23.382 60.456 ;
    END
  END b[24]
  PIN b[250]
    DIRECTION OUTPUT ;
    USE SIGNAL ;
    PORT
      LAYER M3 ;
        RECT  28.116 60.419 28.134 60.456 ;
    END
  END b[250]
  PIN b[251]
    DIRECTION OUTPUT ;
    USE SIGNAL ;
    PORT
      LAYER M3 ;
        RECT  28.188 60.419 28.206 60.456 ;
    END
  END b[251]
  PIN b[252]
    DIRECTION OUTPUT ;
    USE SIGNAL ;
    PORT
      LAYER M3 ;
        RECT  28.26 60.419 28.278 60.456 ;
    END
  END b[252]
  PIN b[253]
    DIRECTION OUTPUT ;
    USE SIGNAL ;
    PORT
      LAYER M3 ;
        RECT  28.332 60.419 28.35 60.456 ;
    END
  END b[253]
  PIN b[254]
    DIRECTION OUTPUT ;
    USE SIGNAL ;
    PORT
      LAYER M3 ;
        RECT  28.404 60.419 28.422 60.456 ;
    END
  END b[254]
  PIN b[255]
    DIRECTION OUTPUT ;
    USE SIGNAL ;
    PORT
      LAYER M3 ;
        RECT  28.476 60.419 28.494 60.456 ;
    END
  END b[255]
  PIN b[256]
    DIRECTION OUTPUT ;
    USE SIGNAL ;
    PORT
      LAYER M3 ;
        RECT  23.94 60.419 23.958 60.456 ;
    END
  END b[256]
  PIN b[257]
    DIRECTION OUTPUT ;
    USE SIGNAL ;
    PORT
      LAYER M3 ;
        RECT  24.012 60.419 24.03 60.456 ;
    END
  END b[257]
  PIN b[258]
    DIRECTION OUTPUT ;
    USE SIGNAL ;
    PORT
      LAYER M3 ;
        RECT  24.084 60.419 24.102 60.456 ;
    END
  END b[258]
  PIN b[259]
    DIRECTION OUTPUT ;
    USE SIGNAL ;
    PORT
      LAYER M3 ;
        RECT  24.156 60.419 24.174 60.456 ;
    END
  END b[259]
  PIN b[25]
    DIRECTION OUTPUT ;
    USE SIGNAL ;
    PORT
      LAYER M3 ;
        RECT  23.436 60.419 23.454 60.456 ;
    END
  END b[25]
  PIN b[260]
    DIRECTION OUTPUT ;
    USE SIGNAL ;
    PORT
      LAYER M3 ;
        RECT  24.228 60.419 24.246 60.456 ;
    END
  END b[260]
  PIN b[261]
    DIRECTION OUTPUT ;
    USE SIGNAL ;
    PORT
      LAYER M3 ;
        RECT  24.3 60.419 24.318 60.456 ;
    END
  END b[261]
  PIN b[262]
    DIRECTION OUTPUT ;
    USE SIGNAL ;
    PORT
      LAYER M3 ;
        RECT  24.372 60.419 24.39 60.456 ;
    END
  END b[262]
  PIN b[263]
    DIRECTION OUTPUT ;
    USE SIGNAL ;
    PORT
      LAYER M3 ;
        RECT  24.444 60.419 24.462 60.456 ;
    END
  END b[263]
  PIN b[264]
    DIRECTION OUTPUT ;
    USE SIGNAL ;
    PORT
      LAYER M3 ;
        RECT  24.516 60.419 24.534 60.456 ;
    END
  END b[264]
  PIN b[265]
    DIRECTION OUTPUT ;
    USE SIGNAL ;
    PORT
      LAYER M3 ;
        RECT  24.588 60.419 24.606 60.456 ;
    END
  END b[265]
  PIN b[266]
    DIRECTION OUTPUT ;
    USE SIGNAL ;
    PORT
      LAYER M3 ;
        RECT  24.66 60.419 24.678 60.456 ;
    END
  END b[266]
  PIN b[267]
    DIRECTION OUTPUT ;
    USE SIGNAL ;
    PORT
      LAYER M3 ;
        RECT  24.732 60.419 24.75 60.456 ;
    END
  END b[267]
  PIN b[268]
    DIRECTION OUTPUT ;
    USE SIGNAL ;
    PORT
      LAYER M3 ;
        RECT  24.804 60.419 24.822 60.456 ;
    END
  END b[268]
  PIN b[269]
    DIRECTION OUTPUT ;
    USE SIGNAL ;
    PORT
      LAYER M3 ;
        RECT  24.876 60.419 24.894 60.456 ;
    END
  END b[269]
  PIN b[26]
    DIRECTION OUTPUT ;
    USE SIGNAL ;
    PORT
      LAYER M3 ;
        RECT  23.508 60.419 23.526 60.456 ;
    END
  END b[26]
  PIN b[270]
    DIRECTION OUTPUT ;
    USE SIGNAL ;
    PORT
      LAYER M3 ;
        RECT  24.948 60.419 24.966 60.456 ;
    END
  END b[270]
  PIN b[271]
    DIRECTION OUTPUT ;
    USE SIGNAL ;
    PORT
      LAYER M3 ;
        RECT  25.02 60.419 25.038 60.456 ;
    END
  END b[271]
  PIN b[272]
    DIRECTION OUTPUT ;
    USE SIGNAL ;
    PORT
      LAYER M3 ;
        RECT  25.092 60.419 25.11 60.456 ;
    END
  END b[272]
  PIN b[273]
    DIRECTION OUTPUT ;
    USE SIGNAL ;
    PORT
      LAYER M3 ;
        RECT  25.164 60.419 25.182 60.456 ;
    END
  END b[273]
  PIN b[274]
    DIRECTION OUTPUT ;
    USE SIGNAL ;
    PORT
      LAYER M3 ;
        RECT  25.236 60.419 25.254 60.456 ;
    END
  END b[274]
  PIN b[275]
    DIRECTION OUTPUT ;
    USE SIGNAL ;
    PORT
      LAYER M3 ;
        RECT  25.308 60.419 25.326 60.456 ;
    END
  END b[275]
  PIN b[276]
    DIRECTION OUTPUT ;
    USE SIGNAL ;
    PORT
      LAYER M3 ;
        RECT  25.38 60.419 25.398 60.456 ;
    END
  END b[276]
  PIN b[277]
    DIRECTION OUTPUT ;
    USE SIGNAL ;
    PORT
      LAYER M3 ;
        RECT  25.452 60.419 25.47 60.456 ;
    END
  END b[277]
  PIN b[278]
    DIRECTION OUTPUT ;
    USE SIGNAL ;
    PORT
      LAYER M3 ;
        RECT  25.524 60.419 25.542 60.456 ;
    END
  END b[278]
  PIN b[279]
    DIRECTION OUTPUT ;
    USE SIGNAL ;
    PORT
      LAYER M3 ;
        RECT  25.596 60.419 25.614 60.456 ;
    END
  END b[279]
  PIN b[27]
    DIRECTION OUTPUT ;
    USE SIGNAL ;
    PORT
      LAYER M3 ;
        RECT  23.58 60.419 23.598 60.456 ;
    END
  END b[27]
  PIN b[280]
    DIRECTION OUTPUT ;
    USE SIGNAL ;
    PORT
      LAYER M3 ;
        RECT  25.668 60.419 25.686 60.456 ;
    END
  END b[280]
  PIN b[281]
    DIRECTION OUTPUT ;
    USE SIGNAL ;
    PORT
      LAYER M3 ;
        RECT  25.74 60.419 25.758 60.456 ;
    END
  END b[281]
  PIN b[282]
    DIRECTION OUTPUT ;
    USE SIGNAL ;
    PORT
      LAYER M3 ;
        RECT  25.812 60.419 25.83 60.456 ;
    END
  END b[282]
  PIN b[283]
    DIRECTION OUTPUT ;
    USE SIGNAL ;
    PORT
      LAYER M3 ;
        RECT  25.884 60.419 25.902 60.456 ;
    END
  END b[283]
  PIN b[284]
    DIRECTION OUTPUT ;
    USE SIGNAL ;
    PORT
      LAYER M3 ;
        RECT  25.956 60.419 25.974 60.456 ;
    END
  END b[284]
  PIN b[285]
    DIRECTION OUTPUT ;
    USE SIGNAL ;
    PORT
      LAYER M3 ;
        RECT  26.028 60.419 26.046 60.456 ;
    END
  END b[285]
  PIN b[286]
    DIRECTION OUTPUT ;
    USE SIGNAL ;
    PORT
      LAYER M3 ;
        RECT  26.1 60.419 26.118 60.456 ;
    END
  END b[286]
  PIN b[287]
    DIRECTION OUTPUT ;
    USE SIGNAL ;
    PORT
      LAYER M3 ;
        RECT  26.172 60.419 26.19 60.456 ;
    END
  END b[287]
  PIN b[288]
    DIRECTION OUTPUT ;
    USE SIGNAL ;
    PORT
      LAYER M3 ;
        RECT  30.852 60.419 30.87 60.456 ;
    END
  END b[288]
  PIN b[289]
    DIRECTION OUTPUT ;
    USE SIGNAL ;
    PORT
      LAYER M3 ;
        RECT  30.924 60.419 30.942 60.456 ;
    END
  END b[289]
  PIN b[28]
    DIRECTION OUTPUT ;
    USE SIGNAL ;
    PORT
      LAYER M3 ;
        RECT  23.652 60.419 23.67 60.456 ;
    END
  END b[28]
  PIN b[290]
    DIRECTION OUTPUT ;
    USE SIGNAL ;
    PORT
      LAYER M3 ;
        RECT  30.996 60.419 31.014 60.456 ;
    END
  END b[290]
  PIN b[291]
    DIRECTION OUTPUT ;
    USE SIGNAL ;
    PORT
      LAYER M3 ;
        RECT  31.068 60.419 31.086 60.456 ;
    END
  END b[291]
  PIN b[292]
    DIRECTION OUTPUT ;
    USE SIGNAL ;
    PORT
      LAYER M3 ;
        RECT  31.14 60.419 31.158 60.456 ;
    END
  END b[292]
  PIN b[293]
    DIRECTION OUTPUT ;
    USE SIGNAL ;
    PORT
      LAYER M3 ;
        RECT  31.212 60.419 31.23 60.456 ;
    END
  END b[293]
  PIN b[294]
    DIRECTION OUTPUT ;
    USE SIGNAL ;
    PORT
      LAYER M3 ;
        RECT  31.284 60.419 31.302 60.456 ;
    END
  END b[294]
  PIN b[295]
    DIRECTION OUTPUT ;
    USE SIGNAL ;
    PORT
      LAYER M3 ;
        RECT  31.356 60.419 31.374 60.456 ;
    END
  END b[295]
  PIN b[296]
    DIRECTION OUTPUT ;
    USE SIGNAL ;
    PORT
      LAYER M3 ;
        RECT  31.428 60.419 31.446 60.456 ;
    END
  END b[296]
  PIN b[297]
    DIRECTION OUTPUT ;
    USE SIGNAL ;
    PORT
      LAYER M3 ;
        RECT  31.5 60.419 31.518 60.456 ;
    END
  END b[297]
  PIN b[298]
    DIRECTION OUTPUT ;
    USE SIGNAL ;
    PORT
      LAYER M3 ;
        RECT  31.572 60.419 31.59 60.456 ;
    END
  END b[298]
  PIN b[299]
    DIRECTION OUTPUT ;
    USE SIGNAL ;
    PORT
      LAYER M3 ;
        RECT  31.644 60.419 31.662 60.456 ;
    END
  END b[299]
  PIN b[29]
    DIRECTION OUTPUT ;
    USE SIGNAL ;
    PORT
      LAYER M3 ;
        RECT  23.724 60.419 23.742 60.456 ;
    END
  END b[29]
  PIN b[2]
    DIRECTION OUTPUT ;
    USE SIGNAL ;
    PORT
      LAYER M3 ;
        RECT  21.78 60.419 21.798 60.456 ;
    END
  END b[2]
  PIN b[300]
    DIRECTION OUTPUT ;
    USE SIGNAL ;
    PORT
      LAYER M3 ;
        RECT  31.716 60.419 31.734 60.456 ;
    END
  END b[300]
  PIN b[301]
    DIRECTION OUTPUT ;
    USE SIGNAL ;
    PORT
      LAYER M3 ;
        RECT  31.788 60.419 31.806 60.456 ;
    END
  END b[301]
  PIN b[302]
    DIRECTION OUTPUT ;
    USE SIGNAL ;
    PORT
      LAYER M3 ;
        RECT  31.86 60.419 31.878 60.456 ;
    END
  END b[302]
  PIN b[303]
    DIRECTION OUTPUT ;
    USE SIGNAL ;
    PORT
      LAYER M3 ;
        RECT  31.932 60.419 31.95 60.456 ;
    END
  END b[303]
  PIN b[304]
    DIRECTION OUTPUT ;
    USE SIGNAL ;
    PORT
      LAYER M3 ;
        RECT  32.004 60.419 32.022 60.456 ;
    END
  END b[304]
  PIN b[305]
    DIRECTION OUTPUT ;
    USE SIGNAL ;
    PORT
      LAYER M3 ;
        RECT  32.076 60.419 32.094 60.456 ;
    END
  END b[305]
  PIN b[306]
    DIRECTION OUTPUT ;
    USE SIGNAL ;
    PORT
      LAYER M3 ;
        RECT  32.148 60.419 32.166 60.456 ;
    END
  END b[306]
  PIN b[307]
    DIRECTION OUTPUT ;
    USE SIGNAL ;
    PORT
      LAYER M3 ;
        RECT  32.22 60.419 32.238 60.456 ;
    END
  END b[307]
  PIN b[308]
    DIRECTION OUTPUT ;
    USE SIGNAL ;
    PORT
      LAYER M3 ;
        RECT  32.292 60.419 32.31 60.456 ;
    END
  END b[308]
  PIN b[309]
    DIRECTION OUTPUT ;
    USE SIGNAL ;
    PORT
      LAYER M3 ;
        RECT  32.364 60.419 32.382 60.456 ;
    END
  END b[309]
  PIN b[30]
    DIRECTION OUTPUT ;
    USE SIGNAL ;
    PORT
      LAYER M3 ;
        RECT  23.796 60.419 23.814 60.456 ;
    END
  END b[30]
  PIN b[310]
    DIRECTION OUTPUT ;
    USE SIGNAL ;
    PORT
      LAYER M3 ;
        RECT  32.436 60.419 32.454 60.456 ;
    END
  END b[310]
  PIN b[311]
    DIRECTION OUTPUT ;
    USE SIGNAL ;
    PORT
      LAYER M3 ;
        RECT  32.508 60.419 32.526 60.456 ;
    END
  END b[311]
  PIN b[312]
    DIRECTION OUTPUT ;
    USE SIGNAL ;
    PORT
      LAYER M3 ;
        RECT  32.58 60.419 32.598 60.456 ;
    END
  END b[312]
  PIN b[313]
    DIRECTION OUTPUT ;
    USE SIGNAL ;
    PORT
      LAYER M3 ;
        RECT  32.652 60.419 32.67 60.456 ;
    END
  END b[313]
  PIN b[314]
    DIRECTION OUTPUT ;
    USE SIGNAL ;
    PORT
      LAYER M3 ;
        RECT  32.724 60.419 32.742 60.456 ;
    END
  END b[314]
  PIN b[315]
    DIRECTION OUTPUT ;
    USE SIGNAL ;
    PORT
      LAYER M3 ;
        RECT  32.796 60.419 32.814 60.456 ;
    END
  END b[315]
  PIN b[316]
    DIRECTION OUTPUT ;
    USE SIGNAL ;
    PORT
      LAYER M3 ;
        RECT  32.868 60.419 32.886 60.456 ;
    END
  END b[316]
  PIN b[317]
    DIRECTION OUTPUT ;
    USE SIGNAL ;
    PORT
      LAYER M3 ;
        RECT  32.94 60.419 32.958 60.456 ;
    END
  END b[317]
  PIN b[318]
    DIRECTION OUTPUT ;
    USE SIGNAL ;
    PORT
      LAYER M3 ;
        RECT  33.012 60.419 33.03 60.456 ;
    END
  END b[318]
  PIN b[319]
    DIRECTION OUTPUT ;
    USE SIGNAL ;
    PORT
      LAYER M3 ;
        RECT  33.084 60.419 33.102 60.456 ;
    END
  END b[319]
  PIN b[31]
    DIRECTION OUTPUT ;
    USE SIGNAL ;
    PORT
      LAYER M3 ;
        RECT  23.868 60.419 23.886 60.456 ;
    END
  END b[31]
  PIN b[320]
    DIRECTION OUTPUT ;
    USE SIGNAL ;
    PORT
      LAYER M3 ;
        RECT  33.156 60.419 33.174 60.456 ;
    END
  END b[320]
  PIN b[321]
    DIRECTION OUTPUT ;
    USE SIGNAL ;
    PORT
      LAYER M3 ;
        RECT  33.228 60.419 33.246 60.456 ;
    END
  END b[321]
  PIN b[322]
    DIRECTION OUTPUT ;
    USE SIGNAL ;
    PORT
      LAYER M3 ;
        RECT  33.3 60.419 33.318 60.456 ;
    END
  END b[322]
  PIN b[323]
    DIRECTION OUTPUT ;
    USE SIGNAL ;
    PORT
      LAYER M3 ;
        RECT  33.372 60.419 33.39 60.456 ;
    END
  END b[323]
  PIN b[324]
    DIRECTION OUTPUT ;
    USE SIGNAL ;
    PORT
      LAYER M3 ;
        RECT  33.444 60.419 33.462 60.456 ;
    END
  END b[324]
  PIN b[325]
    DIRECTION OUTPUT ;
    USE SIGNAL ;
    PORT
      LAYER M3 ;
        RECT  33.516 60.419 33.534 60.456 ;
    END
  END b[325]
  PIN b[326]
    DIRECTION OUTPUT ;
    USE SIGNAL ;
    PORT
      LAYER M3 ;
        RECT  33.588 60.419 33.606 60.456 ;
    END
  END b[326]
  PIN b[327]
    DIRECTION OUTPUT ;
    USE SIGNAL ;
    PORT
      LAYER M3 ;
        RECT  33.66 60.419 33.678 60.456 ;
    END
  END b[327]
  PIN b[328]
    DIRECTION OUTPUT ;
    USE SIGNAL ;
    PORT
      LAYER M3 ;
        RECT  33.732 60.419 33.75 60.456 ;
    END
  END b[328]
  PIN b[329]
    DIRECTION OUTPUT ;
    USE SIGNAL ;
    PORT
      LAYER M3 ;
        RECT  33.804 60.419 33.822 60.456 ;
    END
  END b[329]
  PIN b[32]
    DIRECTION OUTPUT ;
    USE SIGNAL ;
    PORT
      LAYER M5 ;
        RECT  29.52 60.372 29.544 60.456 ;
    END
  END b[32]
  PIN b[330]
    DIRECTION OUTPUT ;
    USE SIGNAL ;
    PORT
      LAYER M3 ;
        RECT  33.876 60.419 33.894 60.456 ;
    END
  END b[330]
  PIN b[331]
    DIRECTION OUTPUT ;
    USE SIGNAL ;
    PORT
      LAYER M3 ;
        RECT  33.948 60.419 33.966 60.456 ;
    END
  END b[331]
  PIN b[332]
    DIRECTION OUTPUT ;
    USE SIGNAL ;
    PORT
      LAYER M3 ;
        RECT  34.02 60.419 34.038 60.456 ;
    END
  END b[332]
  PIN b[333]
    DIRECTION OUTPUT ;
    USE SIGNAL ;
    PORT
      LAYER M3 ;
        RECT  34.092 60.419 34.11 60.456 ;
    END
  END b[333]
  PIN b[334]
    DIRECTION OUTPUT ;
    USE SIGNAL ;
    PORT
      LAYER M3 ;
        RECT  34.164 60.419 34.182 60.456 ;
    END
  END b[334]
  PIN b[335]
    DIRECTION OUTPUT ;
    USE SIGNAL ;
    PORT
      LAYER M3 ;
        RECT  34.236 60.419 34.254 60.456 ;
    END
  END b[335]
  PIN b[336]
    DIRECTION OUTPUT ;
    USE SIGNAL ;
    PORT
      LAYER M3 ;
        RECT  34.308 60.419 34.326 60.456 ;
    END
  END b[336]
  PIN b[337]
    DIRECTION OUTPUT ;
    USE SIGNAL ;
    PORT
      LAYER M3 ;
        RECT  34.38 60.419 34.398 60.456 ;
    END
  END b[337]
  PIN b[338]
    DIRECTION OUTPUT ;
    USE SIGNAL ;
    PORT
      LAYER M3 ;
        RECT  34.452 60.419 34.47 60.456 ;
    END
  END b[338]
  PIN b[339]
    DIRECTION OUTPUT ;
    USE SIGNAL ;
    PORT
      LAYER M3 ;
        RECT  34.524 60.419 34.542 60.456 ;
    END
  END b[339]
  PIN b[33]
    DIRECTION OUTPUT ;
    USE SIGNAL ;
    PORT
      LAYER M5 ;
        RECT  29.616 60.372 29.64 60.456 ;
    END
  END b[33]
  PIN b[340]
    DIRECTION OUTPUT ;
    USE SIGNAL ;
    PORT
      LAYER M3 ;
        RECT  34.596 60.419 34.614 60.456 ;
    END
  END b[340]
  PIN b[341]
    DIRECTION OUTPUT ;
    USE SIGNAL ;
    PORT
      LAYER M3 ;
        RECT  34.668 60.419 34.686 60.456 ;
    END
  END b[341]
  PIN b[342]
    DIRECTION OUTPUT ;
    USE SIGNAL ;
    PORT
      LAYER M3 ;
        RECT  34.74 60.419 34.758 60.456 ;
    END
  END b[342]
  PIN b[343]
    DIRECTION OUTPUT ;
    USE SIGNAL ;
    PORT
      LAYER M3 ;
        RECT  34.812 60.419 34.83 60.456 ;
    END
  END b[343]
  PIN b[344]
    DIRECTION OUTPUT ;
    USE SIGNAL ;
    PORT
      LAYER M3 ;
        RECT  34.884 60.419 34.902 60.456 ;
    END
  END b[344]
  PIN b[345]
    DIRECTION OUTPUT ;
    USE SIGNAL ;
    PORT
      LAYER M3 ;
        RECT  34.956 60.419 34.974 60.456 ;
    END
  END b[345]
  PIN b[346]
    DIRECTION OUTPUT ;
    USE SIGNAL ;
    PORT
      LAYER M3 ;
        RECT  35.028 60.419 35.046 60.456 ;
    END
  END b[346]
  PIN b[347]
    DIRECTION OUTPUT ;
    USE SIGNAL ;
    PORT
      LAYER M3 ;
        RECT  35.1 60.419 35.118 60.456 ;
    END
  END b[347]
  PIN b[348]
    DIRECTION OUTPUT ;
    USE SIGNAL ;
    PORT
      LAYER M3 ;
        RECT  35.172 60.419 35.19 60.456 ;
    END
  END b[348]
  PIN b[349]
    DIRECTION OUTPUT ;
    USE SIGNAL ;
    PORT
      LAYER M3 ;
        RECT  35.244 60.419 35.262 60.456 ;
    END
  END b[349]
  PIN b[34]
    DIRECTION OUTPUT ;
    USE SIGNAL ;
    PORT
      LAYER M5 ;
        RECT  29.712 60.372 29.736 60.456 ;
    END
  END b[34]
  PIN b[350]
    DIRECTION OUTPUT ;
    USE SIGNAL ;
    PORT
      LAYER M3 ;
        RECT  35.316 60.419 35.334 60.456 ;
    END
  END b[350]
  PIN b[351]
    DIRECTION OUTPUT ;
    USE SIGNAL ;
    PORT
      LAYER M3 ;
        RECT  35.388 60.419 35.406 60.456 ;
    END
  END b[351]
  PIN b[352]
    DIRECTION OUTPUT ;
    USE SIGNAL ;
    PORT
      LAYER M3 ;
        RECT  28.548 60.419 28.566 60.456 ;
    END
  END b[352]
  PIN b[353]
    DIRECTION OUTPUT ;
    USE SIGNAL ;
    PORT
      LAYER M3 ;
        RECT  28.62 60.419 28.638 60.456 ;
    END
  END b[353]
  PIN b[354]
    DIRECTION OUTPUT ;
    USE SIGNAL ;
    PORT
      LAYER M3 ;
        RECT  28.692 60.419 28.71 60.456 ;
    END
  END b[354]
  PIN b[355]
    DIRECTION OUTPUT ;
    USE SIGNAL ;
    PORT
      LAYER M3 ;
        RECT  28.764 60.419 28.782 60.456 ;
    END
  END b[355]
  PIN b[356]
    DIRECTION OUTPUT ;
    USE SIGNAL ;
    PORT
      LAYER M3 ;
        RECT  28.836 60.419 28.854 60.456 ;
    END
  END b[356]
  PIN b[357]
    DIRECTION OUTPUT ;
    USE SIGNAL ;
    PORT
      LAYER M3 ;
        RECT  28.908 60.419 28.926 60.456 ;
    END
  END b[357]
  PIN b[358]
    DIRECTION OUTPUT ;
    USE SIGNAL ;
    PORT
      LAYER M3 ;
        RECT  28.98 60.419 28.998 60.456 ;
    END
  END b[358]
  PIN b[359]
    DIRECTION OUTPUT ;
    USE SIGNAL ;
    PORT
      LAYER M3 ;
        RECT  29.052 60.419 29.07 60.456 ;
    END
  END b[359]
  PIN b[35]
    DIRECTION OUTPUT ;
    USE SIGNAL ;
    PORT
      LAYER M5 ;
        RECT  29.808 60.372 29.832 60.456 ;
    END
  END b[35]
  PIN b[360]
    DIRECTION OUTPUT ;
    USE SIGNAL ;
    PORT
      LAYER M3 ;
        RECT  29.124 60.419 29.142 60.456 ;
    END
  END b[360]
  PIN b[361]
    DIRECTION OUTPUT ;
    USE SIGNAL ;
    PORT
      LAYER M3 ;
        RECT  29.196 60.419 29.214 60.456 ;
    END
  END b[361]
  PIN b[362]
    DIRECTION OUTPUT ;
    USE SIGNAL ;
    PORT
      LAYER M3 ;
        RECT  29.268 60.419 29.286 60.456 ;
    END
  END b[362]
  PIN b[363]
    DIRECTION OUTPUT ;
    USE SIGNAL ;
    PORT
      LAYER M3 ;
        RECT  29.34 60.419 29.358 60.456 ;
    END
  END b[363]
  PIN b[364]
    DIRECTION OUTPUT ;
    USE SIGNAL ;
    PORT
      LAYER M3 ;
        RECT  29.412 60.419 29.43 60.456 ;
    END
  END b[364]
  PIN b[365]
    DIRECTION OUTPUT ;
    USE SIGNAL ;
    PORT
      LAYER M3 ;
        RECT  29.484 60.419 29.502 60.456 ;
    END
  END b[365]
  PIN b[366]
    DIRECTION OUTPUT ;
    USE SIGNAL ;
    PORT
      LAYER M3 ;
        RECT  29.556 60.419 29.574 60.456 ;
    END
  END b[366]
  PIN b[367]
    DIRECTION OUTPUT ;
    USE SIGNAL ;
    PORT
      LAYER M3 ;
        RECT  29.628 60.419 29.646 60.456 ;
    END
  END b[367]
  PIN b[368]
    DIRECTION OUTPUT ;
    USE SIGNAL ;
    PORT
      LAYER M3 ;
        RECT  29.7 60.419 29.718 60.456 ;
    END
  END b[368]
  PIN b[369]
    DIRECTION OUTPUT ;
    USE SIGNAL ;
    PORT
      LAYER M3 ;
        RECT  29.772 60.419 29.79 60.456 ;
    END
  END b[369]
  PIN b[36]
    DIRECTION OUTPUT ;
    USE SIGNAL ;
    PORT
      LAYER M5 ;
        RECT  29.904 60.372 29.928 60.456 ;
    END
  END b[36]
  PIN b[370]
    DIRECTION OUTPUT ;
    USE SIGNAL ;
    PORT
      LAYER M3 ;
        RECT  29.844 60.419 29.862 60.456 ;
    END
  END b[370]
  PIN b[371]
    DIRECTION OUTPUT ;
    USE SIGNAL ;
    PORT
      LAYER M3 ;
        RECT  29.916 60.419 29.934 60.456 ;
    END
  END b[371]
  PIN b[372]
    DIRECTION OUTPUT ;
    USE SIGNAL ;
    PORT
      LAYER M3 ;
        RECT  29.988 60.419 30.006 60.456 ;
    END
  END b[372]
  PIN b[373]
    DIRECTION OUTPUT ;
    USE SIGNAL ;
    PORT
      LAYER M3 ;
        RECT  30.06 60.419 30.078 60.456 ;
    END
  END b[373]
  PIN b[374]
    DIRECTION OUTPUT ;
    USE SIGNAL ;
    PORT
      LAYER M3 ;
        RECT  30.132 60.419 30.15 60.456 ;
    END
  END b[374]
  PIN b[375]
    DIRECTION OUTPUT ;
    USE SIGNAL ;
    PORT
      LAYER M3 ;
        RECT  30.204 60.419 30.222 60.456 ;
    END
  END b[375]
  PIN b[376]
    DIRECTION OUTPUT ;
    USE SIGNAL ;
    PORT
      LAYER M3 ;
        RECT  30.276 60.419 30.294 60.456 ;
    END
  END b[376]
  PIN b[377]
    DIRECTION OUTPUT ;
    USE SIGNAL ;
    PORT
      LAYER M3 ;
        RECT  30.348 60.419 30.366 60.456 ;
    END
  END b[377]
  PIN b[378]
    DIRECTION OUTPUT ;
    USE SIGNAL ;
    PORT
      LAYER M3 ;
        RECT  30.42 60.419 30.438 60.456 ;
    END
  END b[378]
  PIN b[379]
    DIRECTION OUTPUT ;
    USE SIGNAL ;
    PORT
      LAYER M3 ;
        RECT  30.492 60.419 30.51 60.456 ;
    END
  END b[379]
  PIN b[37]
    DIRECTION OUTPUT ;
    USE SIGNAL ;
    PORT
      LAYER M5 ;
        RECT  30 60.372 30.024 60.456 ;
    END
  END b[37]
  PIN b[380]
    DIRECTION OUTPUT ;
    USE SIGNAL ;
    PORT
      LAYER M3 ;
        RECT  30.564 60.419 30.582 60.456 ;
    END
  END b[380]
  PIN b[381]
    DIRECTION OUTPUT ;
    USE SIGNAL ;
    PORT
      LAYER M3 ;
        RECT  30.636 60.419 30.654 60.456 ;
    END
  END b[381]
  PIN b[382]
    DIRECTION OUTPUT ;
    USE SIGNAL ;
    PORT
      LAYER M3 ;
        RECT  30.708 60.419 30.726 60.456 ;
    END
  END b[382]
  PIN b[383]
    DIRECTION OUTPUT ;
    USE SIGNAL ;
    PORT
      LAYER M3 ;
        RECT  30.78 60.419 30.798 60.456 ;
    END
  END b[383]
  PIN b[384]
    DIRECTION OUTPUT ;
    USE SIGNAL ;
    PORT
      LAYER M3 ;
        RECT  40.644 60.419 40.662 60.456 ;
    END
  END b[384]
  PIN b[385]
    DIRECTION OUTPUT ;
    USE SIGNAL ;
    PORT
      LAYER M3 ;
        RECT  40.716 60.419 40.734 60.456 ;
    END
  END b[385]
  PIN b[386]
    DIRECTION OUTPUT ;
    USE SIGNAL ;
    PORT
      LAYER M3 ;
        RECT  40.788 60.419 40.806 60.456 ;
    END
  END b[386]
  PIN b[387]
    DIRECTION OUTPUT ;
    USE SIGNAL ;
    PORT
      LAYER M3 ;
        RECT  40.86 60.419 40.878 60.456 ;
    END
  END b[387]
  PIN b[388]
    DIRECTION OUTPUT ;
    USE SIGNAL ;
    PORT
      LAYER M3 ;
        RECT  40.932 60.419 40.95 60.456 ;
    END
  END b[388]
  PIN b[389]
    DIRECTION OUTPUT ;
    USE SIGNAL ;
    PORT
      LAYER M3 ;
        RECT  41.004 60.419 41.022 60.456 ;
    END
  END b[389]
  PIN b[38]
    DIRECTION OUTPUT ;
    USE SIGNAL ;
    PORT
      LAYER M5 ;
        RECT  30.096 60.372 30.12 60.456 ;
    END
  END b[38]
  PIN b[390]
    DIRECTION OUTPUT ;
    USE SIGNAL ;
    PORT
      LAYER M3 ;
        RECT  41.076 60.419 41.094 60.456 ;
    END
  END b[390]
  PIN b[391]
    DIRECTION OUTPUT ;
    USE SIGNAL ;
    PORT
      LAYER M3 ;
        RECT  41.148 60.419 41.166 60.456 ;
    END
  END b[391]
  PIN b[392]
    DIRECTION OUTPUT ;
    USE SIGNAL ;
    PORT
      LAYER M3 ;
        RECT  41.22 60.419 41.238 60.456 ;
    END
  END b[392]
  PIN b[393]
    DIRECTION OUTPUT ;
    USE SIGNAL ;
    PORT
      LAYER M3 ;
        RECT  41.292 60.419 41.31 60.456 ;
    END
  END b[393]
  PIN b[394]
    DIRECTION OUTPUT ;
    USE SIGNAL ;
    PORT
      LAYER M3 ;
        RECT  41.364 60.419 41.382 60.456 ;
    END
  END b[394]
  PIN b[395]
    DIRECTION OUTPUT ;
    USE SIGNAL ;
    PORT
      LAYER M3 ;
        RECT  41.436 60.419 41.454 60.456 ;
    END
  END b[395]
  PIN b[396]
    DIRECTION OUTPUT ;
    USE SIGNAL ;
    PORT
      LAYER M3 ;
        RECT  41.508 60.419 41.526 60.456 ;
    END
  END b[396]
  PIN b[397]
    DIRECTION OUTPUT ;
    USE SIGNAL ;
    PORT
      LAYER M3 ;
        RECT  41.58 60.419 41.598 60.456 ;
    END
  END b[397]
  PIN b[398]
    DIRECTION OUTPUT ;
    USE SIGNAL ;
    PORT
      LAYER M3 ;
        RECT  41.652 60.419 41.67 60.456 ;
    END
  END b[398]
  PIN b[399]
    DIRECTION OUTPUT ;
    USE SIGNAL ;
    PORT
      LAYER M3 ;
        RECT  41.724 60.419 41.742 60.456 ;
    END
  END b[399]
  PIN b[39]
    DIRECTION OUTPUT ;
    USE SIGNAL ;
    PORT
      LAYER M5 ;
        RECT  30.192 60.372 30.216 60.456 ;
    END
  END b[39]
  PIN b[3]
    DIRECTION OUTPUT ;
    USE SIGNAL ;
    PORT
      LAYER M3 ;
        RECT  21.852 60.419 21.87 60.456 ;
    END
  END b[3]
  PIN b[400]
    DIRECTION OUTPUT ;
    USE SIGNAL ;
    PORT
      LAYER M3 ;
        RECT  41.796 60.419 41.814 60.456 ;
    END
  END b[400]
  PIN b[401]
    DIRECTION OUTPUT ;
    USE SIGNAL ;
    PORT
      LAYER M3 ;
        RECT  41.868 60.419 41.886 60.456 ;
    END
  END b[401]
  PIN b[402]
    DIRECTION OUTPUT ;
    USE SIGNAL ;
    PORT
      LAYER M3 ;
        RECT  41.94 60.419 41.958 60.456 ;
    END
  END b[402]
  PIN b[403]
    DIRECTION OUTPUT ;
    USE SIGNAL ;
    PORT
      LAYER M3 ;
        RECT  42.012 60.419 42.03 60.456 ;
    END
  END b[403]
  PIN b[404]
    DIRECTION OUTPUT ;
    USE SIGNAL ;
    PORT
      LAYER M3 ;
        RECT  42.084 60.419 42.102 60.456 ;
    END
  END b[404]
  PIN b[405]
    DIRECTION OUTPUT ;
    USE SIGNAL ;
    PORT
      LAYER M3 ;
        RECT  42.156 60.419 42.174 60.456 ;
    END
  END b[405]
  PIN b[406]
    DIRECTION OUTPUT ;
    USE SIGNAL ;
    PORT
      LAYER M3 ;
        RECT  42.228 60.419 42.246 60.456 ;
    END
  END b[406]
  PIN b[407]
    DIRECTION OUTPUT ;
    USE SIGNAL ;
    PORT
      LAYER M3 ;
        RECT  42.3 60.419 42.318 60.456 ;
    END
  END b[407]
  PIN b[408]
    DIRECTION OUTPUT ;
    USE SIGNAL ;
    PORT
      LAYER M3 ;
        RECT  42.372 60.419 42.39 60.456 ;
    END
  END b[408]
  PIN b[409]
    DIRECTION OUTPUT ;
    USE SIGNAL ;
    PORT
      LAYER M3 ;
        RECT  42.444 60.419 42.462 60.456 ;
    END
  END b[409]
  PIN b[40]
    DIRECTION OUTPUT ;
    USE SIGNAL ;
    PORT
      LAYER M5 ;
        RECT  30.288 60.372 30.312 60.456 ;
    END
  END b[40]
  PIN b[410]
    DIRECTION OUTPUT ;
    USE SIGNAL ;
    PORT
      LAYER M3 ;
        RECT  42.516 60.419 42.534 60.456 ;
    END
  END b[410]
  PIN b[411]
    DIRECTION OUTPUT ;
    USE SIGNAL ;
    PORT
      LAYER M3 ;
        RECT  42.588 60.419 42.606 60.456 ;
    END
  END b[411]
  PIN b[412]
    DIRECTION OUTPUT ;
    USE SIGNAL ;
    PORT
      LAYER M3 ;
        RECT  42.66 60.419 42.678 60.456 ;
    END
  END b[412]
  PIN b[413]
    DIRECTION OUTPUT ;
    USE SIGNAL ;
    PORT
      LAYER M3 ;
        RECT  42.732 60.419 42.75 60.456 ;
    END
  END b[413]
  PIN b[414]
    DIRECTION OUTPUT ;
    USE SIGNAL ;
    PORT
      LAYER M3 ;
        RECT  42.804 60.419 42.822 60.456 ;
    END
  END b[414]
  PIN b[415]
    DIRECTION OUTPUT ;
    USE SIGNAL ;
    PORT
      LAYER M3 ;
        RECT  42.876 60.419 42.894 60.456 ;
    END
  END b[415]
  PIN b[416]
    DIRECTION OUTPUT ;
    USE SIGNAL ;
    PORT
      LAYER M3 ;
        RECT  42.948 60.419 42.966 60.456 ;
    END
  END b[416]
  PIN b[417]
    DIRECTION OUTPUT ;
    USE SIGNAL ;
    PORT
      LAYER M3 ;
        RECT  43.02 60.419 43.038 60.456 ;
    END
  END b[417]
  PIN b[418]
    DIRECTION OUTPUT ;
    USE SIGNAL ;
    PORT
      LAYER M3 ;
        RECT  43.092 60.419 43.11 60.456 ;
    END
  END b[418]
  PIN b[419]
    DIRECTION OUTPUT ;
    USE SIGNAL ;
    PORT
      LAYER M3 ;
        RECT  43.164 60.419 43.182 60.456 ;
    END
  END b[419]
  PIN b[41]
    DIRECTION OUTPUT ;
    USE SIGNAL ;
    PORT
      LAYER M5 ;
        RECT  30.384 60.372 30.408 60.456 ;
    END
  END b[41]
  PIN b[420]
    DIRECTION OUTPUT ;
    USE SIGNAL ;
    PORT
      LAYER M3 ;
        RECT  43.236 60.419 43.254 60.456 ;
    END
  END b[420]
  PIN b[421]
    DIRECTION OUTPUT ;
    USE SIGNAL ;
    PORT
      LAYER M3 ;
        RECT  43.308 60.419 43.326 60.456 ;
    END
  END b[421]
  PIN b[422]
    DIRECTION OUTPUT ;
    USE SIGNAL ;
    PORT
      LAYER M3 ;
        RECT  43.38 60.419 43.398 60.456 ;
    END
  END b[422]
  PIN b[423]
    DIRECTION OUTPUT ;
    USE SIGNAL ;
    PORT
      LAYER M3 ;
        RECT  43.452 60.419 43.47 60.456 ;
    END
  END b[423]
  PIN b[424]
    DIRECTION OUTPUT ;
    USE SIGNAL ;
    PORT
      LAYER M3 ;
        RECT  43.524 60.419 43.542 60.456 ;
    END
  END b[424]
  PIN b[425]
    DIRECTION OUTPUT ;
    USE SIGNAL ;
    PORT
      LAYER M3 ;
        RECT  43.596 60.419 43.614 60.456 ;
    END
  END b[425]
  PIN b[426]
    DIRECTION OUTPUT ;
    USE SIGNAL ;
    PORT
      LAYER M3 ;
        RECT  43.668 60.419 43.686 60.456 ;
    END
  END b[426]
  PIN b[427]
    DIRECTION OUTPUT ;
    USE SIGNAL ;
    PORT
      LAYER M3 ;
        RECT  43.74 60.419 43.758 60.456 ;
    END
  END b[427]
  PIN b[428]
    DIRECTION OUTPUT ;
    USE SIGNAL ;
    PORT
      LAYER M3 ;
        RECT  43.812 60.419 43.83 60.456 ;
    END
  END b[428]
  PIN b[429]
    DIRECTION OUTPUT ;
    USE SIGNAL ;
    PORT
      LAYER M3 ;
        RECT  43.884 60.419 43.902 60.456 ;
    END
  END b[429]
  PIN b[42]
    DIRECTION OUTPUT ;
    USE SIGNAL ;
    PORT
      LAYER M5 ;
        RECT  30.48 60.372 30.504 60.456 ;
    END
  END b[42]
  PIN b[430]
    DIRECTION OUTPUT ;
    USE SIGNAL ;
    PORT
      LAYER M3 ;
        RECT  43.956 60.419 43.974 60.456 ;
    END
  END b[430]
  PIN b[431]
    DIRECTION OUTPUT ;
    USE SIGNAL ;
    PORT
      LAYER M3 ;
        RECT  44.028 60.419 44.046 60.456 ;
    END
  END b[431]
  PIN b[432]
    DIRECTION OUTPUT ;
    USE SIGNAL ;
    PORT
      LAYER M3 ;
        RECT  44.1 60.419 44.118 60.456 ;
    END
  END b[432]
  PIN b[433]
    DIRECTION OUTPUT ;
    USE SIGNAL ;
    PORT
      LAYER M3 ;
        RECT  44.172 60.419 44.19 60.456 ;
    END
  END b[433]
  PIN b[434]
    DIRECTION OUTPUT ;
    USE SIGNAL ;
    PORT
      LAYER M3 ;
        RECT  44.244 60.419 44.262 60.456 ;
    END
  END b[434]
  PIN b[435]
    DIRECTION OUTPUT ;
    USE SIGNAL ;
    PORT
      LAYER M3 ;
        RECT  44.316 60.419 44.334 60.456 ;
    END
  END b[435]
  PIN b[436]
    DIRECTION OUTPUT ;
    USE SIGNAL ;
    PORT
      LAYER M3 ;
        RECT  44.388 60.419 44.406 60.456 ;
    END
  END b[436]
  PIN b[437]
    DIRECTION OUTPUT ;
    USE SIGNAL ;
    PORT
      LAYER M3 ;
        RECT  44.46 60.419 44.478 60.456 ;
    END
  END b[437]
  PIN b[438]
    DIRECTION OUTPUT ;
    USE SIGNAL ;
    PORT
      LAYER M3 ;
        RECT  44.532 60.419 44.55 60.456 ;
    END
  END b[438]
  PIN b[439]
    DIRECTION OUTPUT ;
    USE SIGNAL ;
    PORT
      LAYER M3 ;
        RECT  44.604 60.419 44.622 60.456 ;
    END
  END b[439]
  PIN b[43]
    DIRECTION OUTPUT ;
    USE SIGNAL ;
    PORT
      LAYER M5 ;
        RECT  30.576 60.372 30.6 60.456 ;
    END
  END b[43]
  PIN b[440]
    DIRECTION OUTPUT ;
    USE SIGNAL ;
    PORT
      LAYER M3 ;
        RECT  44.676 60.419 44.694 60.456 ;
    END
  END b[440]
  PIN b[441]
    DIRECTION OUTPUT ;
    USE SIGNAL ;
    PORT
      LAYER M3 ;
        RECT  44.748 60.419 44.766 60.456 ;
    END
  END b[441]
  PIN b[442]
    DIRECTION OUTPUT ;
    USE SIGNAL ;
    PORT
      LAYER M3 ;
        RECT  44.82 60.419 44.838 60.456 ;
    END
  END b[442]
  PIN b[443]
    DIRECTION OUTPUT ;
    USE SIGNAL ;
    PORT
      LAYER M3 ;
        RECT  44.892 60.419 44.91 60.456 ;
    END
  END b[443]
  PIN b[444]
    DIRECTION OUTPUT ;
    USE SIGNAL ;
    PORT
      LAYER M3 ;
        RECT  44.964 60.419 44.982 60.456 ;
    END
  END b[444]
  PIN b[445]
    DIRECTION OUTPUT ;
    USE SIGNAL ;
    PORT
      LAYER M3 ;
        RECT  45.036 60.419 45.054 60.456 ;
    END
  END b[445]
  PIN b[446]
    DIRECTION OUTPUT ;
    USE SIGNAL ;
    PORT
      LAYER M3 ;
        RECT  45.108 60.419 45.126 60.456 ;
    END
  END b[446]
  PIN b[447]
    DIRECTION OUTPUT ;
    USE SIGNAL ;
    PORT
      LAYER M3 ;
        RECT  45.18 60.419 45.198 60.456 ;
    END
  END b[447]
  PIN b[448]
    DIRECTION OUTPUT ;
    USE SIGNAL ;
    PORT
      LAYER M3 ;
        RECT  36.036 60.419 36.054 60.456 ;
    END
  END b[448]
  PIN b[449]
    DIRECTION OUTPUT ;
    USE SIGNAL ;
    PORT
      LAYER M3 ;
        RECT  36.108 60.419 36.126 60.456 ;
    END
  END b[449]
  PIN b[44]
    DIRECTION OUTPUT ;
    USE SIGNAL ;
    PORT
      LAYER M5 ;
        RECT  30.672 60.372 30.696 60.456 ;
    END
  END b[44]
  PIN b[450]
    DIRECTION OUTPUT ;
    USE SIGNAL ;
    PORT
      LAYER M3 ;
        RECT  36.18 60.419 36.198 60.456 ;
    END
  END b[450]
  PIN b[451]
    DIRECTION OUTPUT ;
    USE SIGNAL ;
    PORT
      LAYER M3 ;
        RECT  36.252 60.419 36.27 60.456 ;
    END
  END b[451]
  PIN b[452]
    DIRECTION OUTPUT ;
    USE SIGNAL ;
    PORT
      LAYER M3 ;
        RECT  36.324 60.419 36.342 60.456 ;
    END
  END b[452]
  PIN b[453]
    DIRECTION OUTPUT ;
    USE SIGNAL ;
    PORT
      LAYER M3 ;
        RECT  36.396 60.419 36.414 60.456 ;
    END
  END b[453]
  PIN b[454]
    DIRECTION OUTPUT ;
    USE SIGNAL ;
    PORT
      LAYER M3 ;
        RECT  36.468 60.419 36.486 60.456 ;
    END
  END b[454]
  PIN b[455]
    DIRECTION OUTPUT ;
    USE SIGNAL ;
    PORT
      LAYER M3 ;
        RECT  36.54 60.419 36.558 60.456 ;
    END
  END b[455]
  PIN b[456]
    DIRECTION OUTPUT ;
    USE SIGNAL ;
    PORT
      LAYER M3 ;
        RECT  36.612 60.419 36.63 60.456 ;
    END
  END b[456]
  PIN b[457]
    DIRECTION OUTPUT ;
    USE SIGNAL ;
    PORT
      LAYER M3 ;
        RECT  36.684 60.419 36.702 60.456 ;
    END
  END b[457]
  PIN b[458]
    DIRECTION OUTPUT ;
    USE SIGNAL ;
    PORT
      LAYER M3 ;
        RECT  36.756 60.419 36.774 60.456 ;
    END
  END b[458]
  PIN b[459]
    DIRECTION OUTPUT ;
    USE SIGNAL ;
    PORT
      LAYER M3 ;
        RECT  36.828 60.419 36.846 60.456 ;
    END
  END b[459]
  PIN b[45]
    DIRECTION OUTPUT ;
    USE SIGNAL ;
    PORT
      LAYER M5 ;
        RECT  30.768 60.372 30.792 60.456 ;
    END
  END b[45]
  PIN b[460]
    DIRECTION OUTPUT ;
    USE SIGNAL ;
    PORT
      LAYER M3 ;
        RECT  36.9 60.419 36.918 60.456 ;
    END
  END b[460]
  PIN b[461]
    DIRECTION OUTPUT ;
    USE SIGNAL ;
    PORT
      LAYER M3 ;
        RECT  36.972 60.419 36.99 60.456 ;
    END
  END b[461]
  PIN b[462]
    DIRECTION OUTPUT ;
    USE SIGNAL ;
    PORT
      LAYER M3 ;
        RECT  37.044 60.419 37.062 60.456 ;
    END
  END b[462]
  PIN b[463]
    DIRECTION OUTPUT ;
    USE SIGNAL ;
    PORT
      LAYER M3 ;
        RECT  37.116 60.419 37.134 60.456 ;
    END
  END b[463]
  PIN b[464]
    DIRECTION OUTPUT ;
    USE SIGNAL ;
    PORT
      LAYER M3 ;
        RECT  37.188 60.419 37.206 60.456 ;
    END
  END b[464]
  PIN b[465]
    DIRECTION OUTPUT ;
    USE SIGNAL ;
    PORT
      LAYER M3 ;
        RECT  37.26 60.419 37.278 60.456 ;
    END
  END b[465]
  PIN b[466]
    DIRECTION OUTPUT ;
    USE SIGNAL ;
    PORT
      LAYER M3 ;
        RECT  37.332 60.419 37.35 60.456 ;
    END
  END b[466]
  PIN b[467]
    DIRECTION OUTPUT ;
    USE SIGNAL ;
    PORT
      LAYER M3 ;
        RECT  37.404 60.419 37.422 60.456 ;
    END
  END b[467]
  PIN b[468]
    DIRECTION OUTPUT ;
    USE SIGNAL ;
    PORT
      LAYER M3 ;
        RECT  37.476 60.419 37.494 60.456 ;
    END
  END b[468]
  PIN b[469]
    DIRECTION OUTPUT ;
    USE SIGNAL ;
    PORT
      LAYER M3 ;
        RECT  37.548 60.419 37.566 60.456 ;
    END
  END b[469]
  PIN b[46]
    DIRECTION OUTPUT ;
    USE SIGNAL ;
    PORT
      LAYER M5 ;
        RECT  30.864 60.372 30.888 60.456 ;
    END
  END b[46]
  PIN b[470]
    DIRECTION OUTPUT ;
    USE SIGNAL ;
    PORT
      LAYER M3 ;
        RECT  37.62 60.419 37.638 60.456 ;
    END
  END b[470]
  PIN b[471]
    DIRECTION OUTPUT ;
    USE SIGNAL ;
    PORT
      LAYER M3 ;
        RECT  37.692 60.419 37.71 60.456 ;
    END
  END b[471]
  PIN b[472]
    DIRECTION OUTPUT ;
    USE SIGNAL ;
    PORT
      LAYER M3 ;
        RECT  37.764 60.419 37.782 60.456 ;
    END
  END b[472]
  PIN b[473]
    DIRECTION OUTPUT ;
    USE SIGNAL ;
    PORT
      LAYER M3 ;
        RECT  37.836 60.419 37.854 60.456 ;
    END
  END b[473]
  PIN b[474]
    DIRECTION OUTPUT ;
    USE SIGNAL ;
    PORT
      LAYER M3 ;
        RECT  37.908 60.419 37.926 60.456 ;
    END
  END b[474]
  PIN b[475]
    DIRECTION OUTPUT ;
    USE SIGNAL ;
    PORT
      LAYER M3 ;
        RECT  37.98 60.419 37.998 60.456 ;
    END
  END b[475]
  PIN b[476]
    DIRECTION OUTPUT ;
    USE SIGNAL ;
    PORT
      LAYER M3 ;
        RECT  38.052 60.419 38.07 60.456 ;
    END
  END b[476]
  PIN b[477]
    DIRECTION OUTPUT ;
    USE SIGNAL ;
    PORT
      LAYER M3 ;
        RECT  38.124 60.419 38.142 60.456 ;
    END
  END b[477]
  PIN b[478]
    DIRECTION OUTPUT ;
    USE SIGNAL ;
    PORT
      LAYER M3 ;
        RECT  38.196 60.419 38.214 60.456 ;
    END
  END b[478]
  PIN b[479]
    DIRECTION OUTPUT ;
    USE SIGNAL ;
    PORT
      LAYER M3 ;
        RECT  38.268 60.419 38.286 60.456 ;
    END
  END b[479]
  PIN b[47]
    DIRECTION OUTPUT ;
    USE SIGNAL ;
    PORT
      LAYER M5 ;
        RECT  30.96 60.372 30.984 60.456 ;
    END
  END b[47]
  PIN b[480]
    DIRECTION OUTPUT ;
    USE SIGNAL ;
    PORT
      LAYER M3 ;
        RECT  45.252 60.419 45.27 60.456 ;
    END
  END b[480]
  PIN b[481]
    DIRECTION OUTPUT ;
    USE SIGNAL ;
    PORT
      LAYER M3 ;
        RECT  45.324 60.419 45.342 60.456 ;
    END
  END b[481]
  PIN b[482]
    DIRECTION OUTPUT ;
    USE SIGNAL ;
    PORT
      LAYER M3 ;
        RECT  45.396 60.419 45.414 60.456 ;
    END
  END b[482]
  PIN b[483]
    DIRECTION OUTPUT ;
    USE SIGNAL ;
    PORT
      LAYER M3 ;
        RECT  45.468 60.419 45.486 60.456 ;
    END
  END b[483]
  PIN b[484]
    DIRECTION OUTPUT ;
    USE SIGNAL ;
    PORT
      LAYER M3 ;
        RECT  45.54 60.419 45.558 60.456 ;
    END
  END b[484]
  PIN b[485]
    DIRECTION OUTPUT ;
    USE SIGNAL ;
    PORT
      LAYER M3 ;
        RECT  45.612 60.419 45.63 60.456 ;
    END
  END b[485]
  PIN b[486]
    DIRECTION OUTPUT ;
    USE SIGNAL ;
    PORT
      LAYER M3 ;
        RECT  45.684 60.419 45.702 60.456 ;
    END
  END b[486]
  PIN b[487]
    DIRECTION OUTPUT ;
    USE SIGNAL ;
    PORT
      LAYER M3 ;
        RECT  45.756 60.419 45.774 60.456 ;
    END
  END b[487]
  PIN b[488]
    DIRECTION OUTPUT ;
    USE SIGNAL ;
    PORT
      LAYER M3 ;
        RECT  45.828 60.419 45.846 60.456 ;
    END
  END b[488]
  PIN b[489]
    DIRECTION OUTPUT ;
    USE SIGNAL ;
    PORT
      LAYER M3 ;
        RECT  45.9 60.419 45.918 60.456 ;
    END
  END b[489]
  PIN b[48]
    DIRECTION OUTPUT ;
    USE SIGNAL ;
    PORT
      LAYER M5 ;
        RECT  31.056 60.372 31.08 60.456 ;
    END
  END b[48]
  PIN b[490]
    DIRECTION OUTPUT ;
    USE SIGNAL ;
    PORT
      LAYER M3 ;
        RECT  45.972 60.419 45.99 60.456 ;
    END
  END b[490]
  PIN b[491]
    DIRECTION OUTPUT ;
    USE SIGNAL ;
    PORT
      LAYER M3 ;
        RECT  46.044 60.419 46.062 60.456 ;
    END
  END b[491]
  PIN b[492]
    DIRECTION OUTPUT ;
    USE SIGNAL ;
    PORT
      LAYER M3 ;
        RECT  46.116 60.419 46.134 60.456 ;
    END
  END b[492]
  PIN b[493]
    DIRECTION OUTPUT ;
    USE SIGNAL ;
    PORT
      LAYER M3 ;
        RECT  46.188 60.419 46.206 60.456 ;
    END
  END b[493]
  PIN b[494]
    DIRECTION OUTPUT ;
    USE SIGNAL ;
    PORT
      LAYER M3 ;
        RECT  46.26 60.419 46.278 60.456 ;
    END
  END b[494]
  PIN b[495]
    DIRECTION OUTPUT ;
    USE SIGNAL ;
    PORT
      LAYER M3 ;
        RECT  46.332 60.419 46.35 60.456 ;
    END
  END b[495]
  PIN b[496]
    DIRECTION OUTPUT ;
    USE SIGNAL ;
    PORT
      LAYER M3 ;
        RECT  46.404 60.419 46.422 60.456 ;
    END
  END b[496]
  PIN b[497]
    DIRECTION OUTPUT ;
    USE SIGNAL ;
    PORT
      LAYER M3 ;
        RECT  46.476 60.419 46.494 60.456 ;
    END
  END b[497]
  PIN b[498]
    DIRECTION OUTPUT ;
    USE SIGNAL ;
    PORT
      LAYER M3 ;
        RECT  46.548 60.419 46.566 60.456 ;
    END
  END b[498]
  PIN b[499]
    DIRECTION OUTPUT ;
    USE SIGNAL ;
    PORT
      LAYER M3 ;
        RECT  46.62 60.419 46.638 60.456 ;
    END
  END b[499]
  PIN b[49]
    DIRECTION OUTPUT ;
    USE SIGNAL ;
    PORT
      LAYER M5 ;
        RECT  31.152 60.372 31.176 60.456 ;
    END
  END b[49]
  PIN b[4]
    DIRECTION OUTPUT ;
    USE SIGNAL ;
    PORT
      LAYER M3 ;
        RECT  21.924 60.419 21.942 60.456 ;
    END
  END b[4]
  PIN b[500]
    DIRECTION OUTPUT ;
    USE SIGNAL ;
    PORT
      LAYER M3 ;
        RECT  46.692 60.419 46.71 60.456 ;
    END
  END b[500]
  PIN b[501]
    DIRECTION OUTPUT ;
    USE SIGNAL ;
    PORT
      LAYER M3 ;
        RECT  46.764 60.419 46.782 60.456 ;
    END
  END b[501]
  PIN b[502]
    DIRECTION OUTPUT ;
    USE SIGNAL ;
    PORT
      LAYER M3 ;
        RECT  46.836 60.419 46.854 60.456 ;
    END
  END b[502]
  PIN b[503]
    DIRECTION OUTPUT ;
    USE SIGNAL ;
    PORT
      LAYER M3 ;
        RECT  46.908 60.419 46.926 60.456 ;
    END
  END b[503]
  PIN b[504]
    DIRECTION OUTPUT ;
    USE SIGNAL ;
    PORT
      LAYER M3 ;
        RECT  46.98 60.419 46.998 60.456 ;
    END
  END b[504]
  PIN b[505]
    DIRECTION OUTPUT ;
    USE SIGNAL ;
    PORT
      LAYER M3 ;
        RECT  47.052 60.419 47.07 60.456 ;
    END
  END b[505]
  PIN b[506]
    DIRECTION OUTPUT ;
    USE SIGNAL ;
    PORT
      LAYER M3 ;
        RECT  47.124 60.419 47.142 60.456 ;
    END
  END b[506]
  PIN b[507]
    DIRECTION OUTPUT ;
    USE SIGNAL ;
    PORT
      LAYER M3 ;
        RECT  47.196 60.419 47.214 60.456 ;
    END
  END b[507]
  PIN b[508]
    DIRECTION OUTPUT ;
    USE SIGNAL ;
    PORT
      LAYER M3 ;
        RECT  47.268 60.419 47.286 60.456 ;
    END
  END b[508]
  PIN b[509]
    DIRECTION OUTPUT ;
    USE SIGNAL ;
    PORT
      LAYER M3 ;
        RECT  47.34 60.419 47.358 60.456 ;
    END
  END b[509]
  PIN b[50]
    DIRECTION OUTPUT ;
    USE SIGNAL ;
    PORT
      LAYER M5 ;
        RECT  31.248 60.372 31.272 60.456 ;
    END
  END b[50]
  PIN b[510]
    DIRECTION OUTPUT ;
    USE SIGNAL ;
    PORT
      LAYER M3 ;
        RECT  47.412 60.419 47.43 60.456 ;
    END
  END b[510]
  PIN b[511]
    DIRECTION OUTPUT ;
    USE SIGNAL ;
    PORT
      LAYER M3 ;
        RECT  47.484 60.419 47.502 60.456 ;
    END
  END b[511]
  PIN b[512]
    DIRECTION OUTPUT ;
    USE SIGNAL ;
    PORT
      LAYER M3 ;
        RECT  38.34 60.419 38.358 60.456 ;
    END
  END b[512]
  PIN b[513]
    DIRECTION OUTPUT ;
    USE SIGNAL ;
    PORT
      LAYER M3 ;
        RECT  38.412 60.419 38.43 60.456 ;
    END
  END b[513]
  PIN b[514]
    DIRECTION OUTPUT ;
    USE SIGNAL ;
    PORT
      LAYER M3 ;
        RECT  38.484 60.419 38.502 60.456 ;
    END
  END b[514]
  PIN b[515]
    DIRECTION OUTPUT ;
    USE SIGNAL ;
    PORT
      LAYER M3 ;
        RECT  38.556 60.419 38.574 60.456 ;
    END
  END b[515]
  PIN b[516]
    DIRECTION OUTPUT ;
    USE SIGNAL ;
    PORT
      LAYER M3 ;
        RECT  38.628 60.419 38.646 60.456 ;
    END
  END b[516]
  PIN b[517]
    DIRECTION OUTPUT ;
    USE SIGNAL ;
    PORT
      LAYER M3 ;
        RECT  38.7 60.419 38.718 60.456 ;
    END
  END b[517]
  PIN b[518]
    DIRECTION OUTPUT ;
    USE SIGNAL ;
    PORT
      LAYER M3 ;
        RECT  38.772 60.419 38.79 60.456 ;
    END
  END b[518]
  PIN b[519]
    DIRECTION OUTPUT ;
    USE SIGNAL ;
    PORT
      LAYER M3 ;
        RECT  38.844 60.419 38.862 60.456 ;
    END
  END b[519]
  PIN b[51]
    DIRECTION OUTPUT ;
    USE SIGNAL ;
    PORT
      LAYER M5 ;
        RECT  31.344 60.372 31.368 60.456 ;
    END
  END b[51]
  PIN b[520]
    DIRECTION OUTPUT ;
    USE SIGNAL ;
    PORT
      LAYER M3 ;
        RECT  38.916 60.419 38.934 60.456 ;
    END
  END b[520]
  PIN b[521]
    DIRECTION OUTPUT ;
    USE SIGNAL ;
    PORT
      LAYER M3 ;
        RECT  38.988 60.419 39.006 60.456 ;
    END
  END b[521]
  PIN b[522]
    DIRECTION OUTPUT ;
    USE SIGNAL ;
    PORT
      LAYER M3 ;
        RECT  39.06 60.419 39.078 60.456 ;
    END
  END b[522]
  PIN b[523]
    DIRECTION OUTPUT ;
    USE SIGNAL ;
    PORT
      LAYER M3 ;
        RECT  39.132 60.419 39.15 60.456 ;
    END
  END b[523]
  PIN b[524]
    DIRECTION OUTPUT ;
    USE SIGNAL ;
    PORT
      LAYER M3 ;
        RECT  39.204 60.419 39.222 60.456 ;
    END
  END b[524]
  PIN b[525]
    DIRECTION OUTPUT ;
    USE SIGNAL ;
    PORT
      LAYER M3 ;
        RECT  39.276 60.419 39.294 60.456 ;
    END
  END b[525]
  PIN b[526]
    DIRECTION OUTPUT ;
    USE SIGNAL ;
    PORT
      LAYER M3 ;
        RECT  39.348 60.419 39.366 60.456 ;
    END
  END b[526]
  PIN b[527]
    DIRECTION OUTPUT ;
    USE SIGNAL ;
    PORT
      LAYER M3 ;
        RECT  39.42 60.419 39.438 60.456 ;
    END
  END b[527]
  PIN b[528]
    DIRECTION OUTPUT ;
    USE SIGNAL ;
    PORT
      LAYER M3 ;
        RECT  39.492 60.419 39.51 60.456 ;
    END
  END b[528]
  PIN b[529]
    DIRECTION OUTPUT ;
    USE SIGNAL ;
    PORT
      LAYER M3 ;
        RECT  39.564 60.419 39.582 60.456 ;
    END
  END b[529]
  PIN b[52]
    DIRECTION OUTPUT ;
    USE SIGNAL ;
    PORT
      LAYER M5 ;
        RECT  31.44 60.372 31.464 60.456 ;
    END
  END b[52]
  PIN b[530]
    DIRECTION OUTPUT ;
    USE SIGNAL ;
    PORT
      LAYER M3 ;
        RECT  39.636 60.419 39.654 60.456 ;
    END
  END b[530]
  PIN b[531]
    DIRECTION OUTPUT ;
    USE SIGNAL ;
    PORT
      LAYER M3 ;
        RECT  39.708 60.419 39.726 60.456 ;
    END
  END b[531]
  PIN b[532]
    DIRECTION OUTPUT ;
    USE SIGNAL ;
    PORT
      LAYER M3 ;
        RECT  39.78 60.419 39.798 60.456 ;
    END
  END b[532]
  PIN b[533]
    DIRECTION OUTPUT ;
    USE SIGNAL ;
    PORT
      LAYER M3 ;
        RECT  39.852 60.419 39.87 60.456 ;
    END
  END b[533]
  PIN b[534]
    DIRECTION OUTPUT ;
    USE SIGNAL ;
    PORT
      LAYER M3 ;
        RECT  39.924 60.419 39.942 60.456 ;
    END
  END b[534]
  PIN b[535]
    DIRECTION OUTPUT ;
    USE SIGNAL ;
    PORT
      LAYER M3 ;
        RECT  39.996 60.419 40.014 60.456 ;
    END
  END b[535]
  PIN b[536]
    DIRECTION OUTPUT ;
    USE SIGNAL ;
    PORT
      LAYER M3 ;
        RECT  40.068 60.419 40.086 60.456 ;
    END
  END b[536]
  PIN b[537]
    DIRECTION OUTPUT ;
    USE SIGNAL ;
    PORT
      LAYER M3 ;
        RECT  40.14 60.419 40.158 60.456 ;
    END
  END b[537]
  PIN b[538]
    DIRECTION OUTPUT ;
    USE SIGNAL ;
    PORT
      LAYER M3 ;
        RECT  40.212 60.419 40.23 60.456 ;
    END
  END b[538]
  PIN b[539]
    DIRECTION OUTPUT ;
    USE SIGNAL ;
    PORT
      LAYER M3 ;
        RECT  40.284 60.419 40.302 60.456 ;
    END
  END b[539]
  PIN b[53]
    DIRECTION OUTPUT ;
    USE SIGNAL ;
    PORT
      LAYER M5 ;
        RECT  31.536 60.372 31.56 60.456 ;
    END
  END b[53]
  PIN b[540]
    DIRECTION OUTPUT ;
    USE SIGNAL ;
    PORT
      LAYER M3 ;
        RECT  40.356 60.419 40.374 60.456 ;
    END
  END b[540]
  PIN b[541]
    DIRECTION OUTPUT ;
    USE SIGNAL ;
    PORT
      LAYER M3 ;
        RECT  40.428 60.419 40.446 60.456 ;
    END
  END b[541]
  PIN b[542]
    DIRECTION OUTPUT ;
    USE SIGNAL ;
    PORT
      LAYER M3 ;
        RECT  40.5 60.419 40.518 60.456 ;
    END
  END b[542]
  PIN b[543]
    DIRECTION OUTPUT ;
    USE SIGNAL ;
    PORT
      LAYER M3 ;
        RECT  40.572 60.419 40.59 60.456 ;
    END
  END b[543]
  PIN b[544]
    DIRECTION OUTPUT ;
    USE SIGNAL ;
    PORT
      LAYER M5 ;
        RECT  25.968 60.372 25.992 60.456 ;
    END
  END b[544]
  PIN b[545]
    DIRECTION OUTPUT ;
    USE SIGNAL ;
    PORT
      LAYER M5 ;
        RECT  26.064 60.372 26.088 60.456 ;
    END
  END b[545]
  PIN b[546]
    DIRECTION OUTPUT ;
    USE SIGNAL ;
    PORT
      LAYER M5 ;
        RECT  26.16 60.372 26.184 60.456 ;
    END
  END b[546]
  PIN b[547]
    DIRECTION OUTPUT ;
    USE SIGNAL ;
    PORT
      LAYER M5 ;
        RECT  26.256 60.372 26.28 60.456 ;
    END
  END b[547]
  PIN b[54]
    DIRECTION OUTPUT ;
    USE SIGNAL ;
    PORT
      LAYER M5 ;
        RECT  31.632 60.372 31.656 60.456 ;
    END
  END b[54]
  PIN b[55]
    DIRECTION OUTPUT ;
    USE SIGNAL ;
    PORT
      LAYER M5 ;
        RECT  31.728 60.372 31.752 60.456 ;
    END
  END b[55]
  PIN b[56]
    DIRECTION OUTPUT ;
    USE SIGNAL ;
    PORT
      LAYER M5 ;
        RECT  31.824 60.372 31.848 60.456 ;
    END
  END b[56]
  PIN b[57]
    DIRECTION OUTPUT ;
    USE SIGNAL ;
    PORT
      LAYER M5 ;
        RECT  31.92 60.372 31.944 60.456 ;
    END
  END b[57]
  PIN b[58]
    DIRECTION OUTPUT ;
    USE SIGNAL ;
    PORT
      LAYER M5 ;
        RECT  32.016 60.372 32.04 60.456 ;
    END
  END b[58]
  PIN b[59]
    DIRECTION OUTPUT ;
    USE SIGNAL ;
    PORT
      LAYER M5 ;
        RECT  32.112 60.372 32.136 60.456 ;
    END
  END b[59]
  PIN b[5]
    DIRECTION OUTPUT ;
    USE SIGNAL ;
    PORT
      LAYER M3 ;
        RECT  21.996 60.419 22.014 60.456 ;
    END
  END b[5]
  PIN b[60]
    DIRECTION OUTPUT ;
    USE SIGNAL ;
    PORT
      LAYER M5 ;
        RECT  32.208 60.372 32.232 60.456 ;
    END
  END b[60]
  PIN b[61]
    DIRECTION OUTPUT ;
    USE SIGNAL ;
    PORT
      LAYER M5 ;
        RECT  32.304 60.372 32.328 60.456 ;
    END
  END b[61]
  PIN b[62]
    DIRECTION OUTPUT ;
    USE SIGNAL ;
    PORT
      LAYER M5 ;
        RECT  32.4 60.372 32.424 60.456 ;
    END
  END b[62]
  PIN b[63]
    DIRECTION OUTPUT ;
    USE SIGNAL ;
    PORT
      LAYER M5 ;
        RECT  32.496 60.372 32.52 60.456 ;
    END
  END b[63]
  PIN b[64]
    DIRECTION OUTPUT ;
    USE SIGNAL ;
    PORT
      LAYER M5 ;
        RECT  35.664 60.372 35.688 60.456 ;
    END
  END b[64]
  PIN b[65]
    DIRECTION OUTPUT ;
    USE SIGNAL ;
    PORT
      LAYER M5 ;
        RECT  35.76 60.372 35.784 60.456 ;
    END
  END b[65]
  PIN b[66]
    DIRECTION OUTPUT ;
    USE SIGNAL ;
    PORT
      LAYER M5 ;
        RECT  35.856 60.372 35.88 60.456 ;
    END
  END b[66]
  PIN b[67]
    DIRECTION OUTPUT ;
    USE SIGNAL ;
    PORT
      LAYER M5 ;
        RECT  35.952 60.372 35.976 60.456 ;
    END
  END b[67]
  PIN b[68]
    DIRECTION OUTPUT ;
    USE SIGNAL ;
    PORT
      LAYER M5 ;
        RECT  36.048 60.372 36.072 60.456 ;
    END
  END b[68]
  PIN b[69]
    DIRECTION OUTPUT ;
    USE SIGNAL ;
    PORT
      LAYER M5 ;
        RECT  36.144 60.372 36.168 60.456 ;
    END
  END b[69]
  PIN b[6]
    DIRECTION OUTPUT ;
    USE SIGNAL ;
    PORT
      LAYER M3 ;
        RECT  22.068 60.419 22.086 60.456 ;
    END
  END b[6]
  PIN b[70]
    DIRECTION OUTPUT ;
    USE SIGNAL ;
    PORT
      LAYER M5 ;
        RECT  36.24 60.372 36.264 60.456 ;
    END
  END b[70]
  PIN b[71]
    DIRECTION OUTPUT ;
    USE SIGNAL ;
    PORT
      LAYER M5 ;
        RECT  36.336 60.372 36.36 60.456 ;
    END
  END b[71]
  PIN b[72]
    DIRECTION OUTPUT ;
    USE SIGNAL ;
    PORT
      LAYER M5 ;
        RECT  36.432 60.372 36.456 60.456 ;
    END
  END b[72]
  PIN b[73]
    DIRECTION OUTPUT ;
    USE SIGNAL ;
    PORT
      LAYER M5 ;
        RECT  36.528 60.372 36.552 60.456 ;
    END
  END b[73]
  PIN b[74]
    DIRECTION OUTPUT ;
    USE SIGNAL ;
    PORT
      LAYER M5 ;
        RECT  36.624 60.372 36.648 60.456 ;
    END
  END b[74]
  PIN b[75]
    DIRECTION OUTPUT ;
    USE SIGNAL ;
    PORT
      LAYER M5 ;
        RECT  36.72 60.372 36.744 60.456 ;
    END
  END b[75]
  PIN b[76]
    DIRECTION OUTPUT ;
    USE SIGNAL ;
    PORT
      LAYER M5 ;
        RECT  36.816 60.372 36.84 60.456 ;
    END
  END b[76]
  PIN b[77]
    DIRECTION OUTPUT ;
    USE SIGNAL ;
    PORT
      LAYER M5 ;
        RECT  36.912 60.372 36.936 60.456 ;
    END
  END b[77]
  PIN b[78]
    DIRECTION OUTPUT ;
    USE SIGNAL ;
    PORT
      LAYER M5 ;
        RECT  37.008 60.372 37.032 60.456 ;
    END
  END b[78]
  PIN b[79]
    DIRECTION OUTPUT ;
    USE SIGNAL ;
    PORT
      LAYER M5 ;
        RECT  37.104 60.372 37.128 60.456 ;
    END
  END b[79]
  PIN b[7]
    DIRECTION OUTPUT ;
    USE SIGNAL ;
    PORT
      LAYER M3 ;
        RECT  22.14 60.419 22.158 60.456 ;
    END
  END b[7]
  PIN b[80]
    DIRECTION OUTPUT ;
    USE SIGNAL ;
    PORT
      LAYER M5 ;
        RECT  37.2 60.372 37.224 60.456 ;
    END
  END b[80]
  PIN b[81]
    DIRECTION OUTPUT ;
    USE SIGNAL ;
    PORT
      LAYER M5 ;
        RECT  37.296 60.372 37.32 60.456 ;
    END
  END b[81]
  PIN b[82]
    DIRECTION OUTPUT ;
    USE SIGNAL ;
    PORT
      LAYER M5 ;
        RECT  37.392 60.372 37.416 60.456 ;
    END
  END b[82]
  PIN b[83]
    DIRECTION OUTPUT ;
    USE SIGNAL ;
    PORT
      LAYER M5 ;
        RECT  37.488 60.372 37.512 60.456 ;
    END
  END b[83]
  PIN b[84]
    DIRECTION OUTPUT ;
    USE SIGNAL ;
    PORT
      LAYER M5 ;
        RECT  37.584 60.372 37.608 60.456 ;
    END
  END b[84]
  PIN b[85]
    DIRECTION OUTPUT ;
    USE SIGNAL ;
    PORT
      LAYER M5 ;
        RECT  37.68 60.372 37.704 60.456 ;
    END
  END b[85]
  PIN b[86]
    DIRECTION OUTPUT ;
    USE SIGNAL ;
    PORT
      LAYER M5 ;
        RECT  37.776 60.372 37.8 60.456 ;
    END
  END b[86]
  PIN b[87]
    DIRECTION OUTPUT ;
    USE SIGNAL ;
    PORT
      LAYER M5 ;
        RECT  37.872 60.372 37.896 60.456 ;
    END
  END b[87]
  PIN b[88]
    DIRECTION OUTPUT ;
    USE SIGNAL ;
    PORT
      LAYER M5 ;
        RECT  37.968 60.372 37.992 60.456 ;
    END
  END b[88]
  PIN b[89]
    DIRECTION OUTPUT ;
    USE SIGNAL ;
    PORT
      LAYER M5 ;
        RECT  38.064 60.372 38.088 60.456 ;
    END
  END b[89]
  PIN b[8]
    DIRECTION OUTPUT ;
    USE SIGNAL ;
    PORT
      LAYER M3 ;
        RECT  22.212 60.419 22.23 60.456 ;
    END
  END b[8]
  PIN b[90]
    DIRECTION OUTPUT ;
    USE SIGNAL ;
    PORT
      LAYER M5 ;
        RECT  38.16 60.372 38.184 60.456 ;
    END
  END b[90]
  PIN b[91]
    DIRECTION OUTPUT ;
    USE SIGNAL ;
    PORT
      LAYER M5 ;
        RECT  38.256 60.372 38.28 60.456 ;
    END
  END b[91]
  PIN b[92]
    DIRECTION OUTPUT ;
    USE SIGNAL ;
    PORT
      LAYER M5 ;
        RECT  38.352 60.372 38.376 60.456 ;
    END
  END b[92]
  PIN b[93]
    DIRECTION OUTPUT ;
    USE SIGNAL ;
    PORT
      LAYER M5 ;
        RECT  38.448 60.372 38.472 60.456 ;
    END
  END b[93]
  PIN b[94]
    DIRECTION OUTPUT ;
    USE SIGNAL ;
    PORT
      LAYER M5 ;
        RECT  38.544 60.372 38.568 60.456 ;
    END
  END b[94]
  PIN b[95]
    DIRECTION OUTPUT ;
    USE SIGNAL ;
    PORT
      LAYER M5 ;
        RECT  38.64 60.372 38.664 60.456 ;
    END
  END b[95]
  PIN b[96]
    DIRECTION OUTPUT ;
    USE SIGNAL ;
    PORT
      LAYER M5 ;
        RECT  41.808 60.372 41.832 60.456 ;
    END
  END b[96]
  PIN b[97]
    DIRECTION OUTPUT ;
    USE SIGNAL ;
    PORT
      LAYER M5 ;
        RECT  41.904 60.372 41.928 60.456 ;
    END
  END b[97]
  PIN b[98]
    DIRECTION OUTPUT ;
    USE SIGNAL ;
    PORT
      LAYER M5 ;
        RECT  42 60.372 42.024 60.456 ;
    END
  END b[98]
  PIN b[99]
    DIRECTION OUTPUT ;
    USE SIGNAL ;
    PORT
      LAYER M5 ;
        RECT  42.096 60.372 42.12 60.456 ;
    END
  END b[99]
  PIN b[9]
    DIRECTION OUTPUT ;
    USE SIGNAL ;
    PORT
      LAYER M3 ;
        RECT  22.284 60.419 22.302 60.456 ;
    END
  END b[9]
  PIN ck
    DIRECTION INPUT ;
    USE SIGNAL ;
    PORT
      LAYER M4 ;
        RECT  0 29.616 0.084 29.64 ;
    END
  END ck
  PIN ck_o
    DIRECTION OUTPUT ;
    USE SIGNAL ;
    PORT
      LAYER M4 ;
        RECT  0 29.712 0.084 29.736 ;
    END
  END ck_o
  PIN eb
    DIRECTION OUTPUT ;
    USE SIGNAL ;
    PORT
      LAYER M5 ;
        RECT  26.352 60.372 26.376 60.456 ;
    END
  END eb
  PIN en
    DIRECTION INPUT ;
    USE SIGNAL ;
    PORT
      LAYER M4 ;
        RECT  0 29.808 0.084 29.832 ;
    END
  END en
  PIN VDD
    DIRECTION INOUT ;
    USE POWER ;
    PORT
      LAYER M5 ;
        RECT  61.992 2.151 62.112 58.073 ;
        RECT  59.292 2.151 59.412 58.073 ;
        RECT  56.592 2.151 56.712 58.073 ;
        RECT  53.892 2.151 54.012 58.073 ;
        RECT  51.192 2.151 51.312 58.073 ;
        RECT  48.492 2.151 48.612 58.073 ;
        RECT  45.792 2.151 45.912 58.073 ;
        RECT  43.092 2.151 43.212 58.073 ;
        RECT  40.392 2.151 40.512 58.073 ;
        RECT  37.692 2.151 37.812 58.073 ;
        RECT  34.992 2.151 35.112 58.073 ;
        RECT  32.292 2.151 32.412 58.073 ;
        RECT  29.592 2.151 29.712 58.073 ;
        RECT  26.892 2.151 27.012 58.073 ;
        RECT  24.192 2.151 24.312 58.073 ;
        RECT  21.492 2.151 21.612 58.073 ;
        RECT  18.792 2.151 18.912 58.073 ;
        RECT  16.092 2.151 16.212 58.073 ;
        RECT  13.392 2.151 13.512 58.073 ;
        RECT  10.692 2.151 10.812 58.073 ;
        RECT  7.992 2.151 8.112 58.073 ;
        RECT  5.292 2.151 5.412 58.073 ;
        RECT  2.592 2.151 2.712 58.073 ;
    END
  END VDD
  PIN VSS
    DIRECTION INOUT ;
    USE GROUND ;
    PORT
      LAYER M5 ;
        RECT  61.8 2.137 61.92 58.059 ;
        RECT  59.1 2.137 59.22 58.059 ;
        RECT  56.4 2.137 56.52 58.059 ;
        RECT  53.7 2.137 53.82 58.059 ;
        RECT  51 2.137 51.12 58.059 ;
        RECT  48.3 2.137 48.42 58.059 ;
        RECT  45.6 2.137 45.72 58.059 ;
        RECT  42.9 2.137 43.02 58.059 ;
        RECT  40.2 2.137 40.32 58.059 ;
        RECT  37.5 2.137 37.62 58.059 ;
        RECT  34.8 2.137 34.92 58.059 ;
        RECT  32.1 2.137 32.22 58.059 ;
        RECT  29.4 2.137 29.52 58.059 ;
        RECT  26.7 2.137 26.82 58.059 ;
        RECT  24 2.137 24.12 58.059 ;
        RECT  21.3 2.137 21.42 58.059 ;
        RECT  18.6 2.137 18.72 58.059 ;
        RECT  15.9 2.137 16.02 58.059 ;
        RECT  13.2 2.137 13.32 58.059 ;
        RECT  10.5 2.137 10.62 58.059 ;
        RECT  7.8 2.137 7.92 58.059 ;
        RECT  5.1 2.137 5.22 58.059 ;
        RECT  2.4 2.137 2.52 58.059 ;
    END
  END VSS
  OBS
    LAYER RVTN ;
     RECT  2.16 2.16 62.586 2.295 ;
     RECT  2.16 2.565 62.586 2.835 ;
     RECT  2.16 3.105 62.586 3.375 ;
     RECT  2.16 3.645 62.586 3.915 ;
     RECT  2.16 4.185 62.586 4.455 ;
     RECT  2.16 4.725 62.586 4.995 ;
     RECT  2.16 5.265 62.586 5.535 ;
     RECT  2.16 5.805 62.586 6.075 ;
     RECT  2.16 6.345 62.586 6.615 ;
     RECT  2.16 6.885 62.586 7.155 ;
     RECT  2.16 7.425 62.586 7.695 ;
     RECT  2.16 7.965 62.586 8.235 ;
     RECT  2.16 8.505 62.586 8.775 ;
     RECT  2.16 9.045 62.586 9.315 ;
     RECT  2.16 9.585 62.586 9.855 ;
     RECT  2.16 10.125 62.586 10.395 ;
     RECT  2.16 10.665 62.586 10.935 ;
     RECT  2.16 11.205 62.586 11.475 ;
     RECT  2.16 11.745 62.586 12.015 ;
     RECT  2.16 12.285 62.586 12.555 ;
     RECT  2.16 12.825 62.586 13.095 ;
     RECT  2.16 13.365 62.586 13.635 ;
     RECT  2.16 13.905 62.586 14.175 ;
     RECT  2.16 14.445 62.586 14.715 ;
     RECT  2.16 14.985 62.586 15.255 ;
     RECT  2.16 15.525 62.586 15.795 ;
     RECT  2.16 16.065 62.586 16.335 ;
     RECT  2.16 16.605 62.586 16.875 ;
     RECT  2.16 17.145 62.586 17.415 ;
     RECT  2.16 17.685 62.586 17.955 ;
     RECT  2.16 18.225 62.586 18.495 ;
     RECT  2.16 18.765 62.586 19.035 ;
     RECT  2.16 19.305 62.586 19.575 ;
     RECT  2.16 19.845 62.586 20.115 ;
     RECT  2.16 20.385 62.586 20.655 ;
     RECT  2.16 20.925 62.586 21.195 ;
     RECT  2.16 21.465 62.586 21.735 ;
     RECT  2.16 22.005 62.586 22.275 ;
     RECT  2.16 22.545 62.586 22.815 ;
     RECT  2.16 23.085 62.586 23.355 ;
     RECT  2.16 23.625 62.586 23.895 ;
     RECT  2.16 24.165 62.586 24.435 ;
     RECT  2.16 24.705 62.586 24.975 ;
     RECT  2.16 25.245 62.586 25.515 ;
     RECT  2.16 25.785 62.586 26.055 ;
     RECT  2.16 26.325 62.586 26.595 ;
     RECT  2.16 26.865 62.586 27.135 ;
     RECT  2.16 27.405 62.586 27.675 ;
     RECT  2.16 27.945 62.586 28.215 ;
     RECT  2.16 28.485 62.586 28.755 ;
     RECT  2.16 29.025 62.586 29.295 ;
     RECT  2.16 29.565 62.586 29.835 ;
     RECT  2.16 30.105 62.586 30.375 ;
     RECT  2.16 30.645 62.586 30.915 ;
     RECT  2.16 31.185 62.586 31.455 ;
     RECT  2.16 31.725 62.586 31.995 ;
     RECT  2.16 32.265 62.586 32.535 ;
     RECT  2.16 32.805 62.586 33.075 ;
     RECT  2.16 33.345 62.586 33.615 ;
     RECT  2.16 33.885 62.586 34.155 ;
     RECT  2.16 34.425 62.586 34.695 ;
     RECT  2.16 34.965 62.586 35.235 ;
     RECT  2.16 35.505 62.586 35.775 ;
     RECT  2.16 36.045 62.586 36.315 ;
     RECT  2.16 36.585 62.586 36.855 ;
     RECT  2.16 37.125 62.586 37.395 ;
     RECT  2.16 37.665 62.586 37.935 ;
     RECT  2.16 38.205 62.586 38.475 ;
     RECT  2.16 38.745 62.586 39.015 ;
     RECT  2.16 39.285 62.586 39.555 ;
     RECT  2.16 39.825 62.586 40.095 ;
     RECT  2.16 40.365 62.586 40.635 ;
     RECT  2.16 40.905 62.586 41.175 ;
     RECT  2.16 41.445 62.586 41.715 ;
     RECT  2.16 41.985 62.586 42.255 ;
     RECT  2.16 42.525 62.586 42.795 ;
     RECT  2.16 43.065 62.586 43.335 ;
     RECT  2.16 43.605 62.586 43.875 ;
     RECT  2.16 44.145 62.586 44.415 ;
     RECT  2.16 44.685 62.586 44.955 ;
     RECT  2.16 45.225 62.586 45.495 ;
     RECT  2.16 45.765 62.586 46.035 ;
     RECT  2.16 46.305 62.586 46.575 ;
     RECT  2.16 46.845 62.586 47.115 ;
     RECT  2.16 47.385 62.586 47.655 ;
     RECT  2.16 47.925 62.586 48.195 ;
     RECT  2.16 48.465 62.586 48.735 ;
     RECT  2.16 49.005 62.586 49.275 ;
     RECT  2.16 49.545 62.586 49.815 ;
     RECT  2.16 50.085 62.586 50.355 ;
     RECT  2.16 50.625 62.586 50.895 ;
     RECT  2.16 51.165 62.586 51.435 ;
     RECT  2.16 51.705 62.586 51.975 ;
     RECT  2.16 52.245 62.586 52.515 ;
     RECT  2.16 52.785 62.586 53.055 ;
     RECT  2.16 53.325 62.586 53.595 ;
     RECT  2.16 53.865 62.586 54.135 ;
     RECT  2.16 54.405 62.586 54.675 ;
     RECT  2.16 54.945 62.586 55.215 ;
     RECT  2.16 55.485 62.586 55.755 ;
     RECT  2.16 56.025 62.586 56.295 ;
     RECT  2.16 56.565 62.586 56.835 ;
     RECT  2.16 57.105 62.586 57.375 ;
     RECT  2.16 57.645 62.586 57.915 ;
    LAYER RVTP ;
     RECT  2.16 2.295 62.586 2.565 ;
     RECT  2.16 2.835 62.586 3.105 ;
     RECT  2.16 3.375 62.586 3.645 ;
     RECT  2.16 3.915 62.586 4.185 ;
     RECT  2.16 4.455 62.586 4.725 ;
     RECT  2.16 4.995 62.586 5.265 ;
     RECT  2.16 5.535 62.586 5.805 ;
     RECT  2.16 6.075 62.586 6.345 ;
     RECT  2.16 6.615 62.586 6.885 ;
     RECT  2.16 7.155 62.586 7.425 ;
     RECT  2.16 7.695 62.586 7.965 ;
     RECT  2.16 8.235 62.586 8.505 ;
     RECT  2.16 8.775 62.586 9.045 ;
     RECT  2.16 9.315 62.586 9.585 ;
     RECT  2.16 9.855 62.586 10.125 ;
     RECT  2.16 10.395 62.586 10.665 ;
     RECT  2.16 10.935 62.586 11.205 ;
     RECT  2.16 11.475 62.586 11.745 ;
     RECT  2.16 12.015 62.586 12.285 ;
     RECT  2.16 12.555 62.586 12.825 ;
     RECT  2.16 13.095 62.586 13.365 ;
     RECT  2.16 13.635 62.586 13.905 ;
     RECT  2.16 14.175 62.586 14.445 ;
     RECT  2.16 14.715 62.586 14.985 ;
     RECT  2.16 15.255 62.586 15.525 ;
     RECT  2.16 15.795 62.586 16.065 ;
     RECT  2.16 16.335 62.586 16.605 ;
     RECT  2.16 16.875 62.586 17.145 ;
     RECT  2.16 17.415 62.586 17.685 ;
     RECT  2.16 17.955 62.586 18.225 ;
     RECT  2.16 18.495 62.586 18.765 ;
     RECT  2.16 19.035 62.586 19.305 ;
     RECT  2.16 19.575 62.586 19.845 ;
     RECT  2.16 20.115 62.586 20.385 ;
     RECT  2.16 20.655 62.586 20.925 ;
     RECT  2.16 21.195 62.586 21.465 ;
     RECT  2.16 21.735 62.586 22.005 ;
     RECT  2.16 22.275 62.586 22.545 ;
     RECT  2.16 22.815 62.586 23.085 ;
     RECT  2.16 23.355 62.586 23.625 ;
     RECT  2.16 23.895 62.586 24.165 ;
     RECT  2.16 24.435 62.586 24.705 ;
     RECT  2.16 24.975 62.586 25.245 ;
     RECT  2.16 25.515 62.586 25.785 ;
     RECT  2.16 26.055 62.586 26.325 ;
     RECT  2.16 26.595 62.586 26.865 ;
     RECT  2.16 27.135 62.586 27.405 ;
     RECT  2.16 27.675 62.586 27.945 ;
     RECT  2.16 28.215 62.586 28.485 ;
     RECT  2.16 28.755 62.586 29.025 ;
     RECT  2.16 29.295 62.586 29.565 ;
     RECT  2.16 29.835 62.586 30.105 ;
     RECT  2.16 30.375 62.586 30.645 ;
     RECT  2.16 30.915 62.586 31.185 ;
     RECT  2.16 31.455 62.586 31.725 ;
     RECT  2.16 31.995 62.586 32.265 ;
     RECT  2.16 32.535 62.586 32.805 ;
     RECT  2.16 33.075 62.586 33.345 ;
     RECT  2.16 33.615 62.586 33.885 ;
     RECT  2.16 34.155 62.586 34.425 ;
     RECT  2.16 34.695 62.586 34.965 ;
     RECT  2.16 35.235 62.586 35.505 ;
     RECT  2.16 35.775 62.586 36.045 ;
     RECT  2.16 36.315 62.586 36.585 ;
     RECT  2.16 36.855 62.586 37.125 ;
     RECT  2.16 37.395 62.586 37.665 ;
     RECT  2.16 37.935 62.586 38.205 ;
     RECT  2.16 38.475 62.586 38.745 ;
     RECT  2.16 39.015 62.586 39.285 ;
     RECT  2.16 39.555 62.586 39.825 ;
     RECT  2.16 40.095 62.586 40.365 ;
     RECT  2.16 40.635 62.586 40.905 ;
     RECT  2.16 41.175 62.586 41.445 ;
     RECT  2.16 41.715 62.586 41.985 ;
     RECT  2.16 42.255 62.586 42.525 ;
     RECT  2.16 42.795 62.586 43.065 ;
     RECT  2.16 43.335 62.586 43.605 ;
     RECT  2.16 43.875 62.586 44.145 ;
     RECT  2.16 44.415 62.586 44.685 ;
     RECT  2.16 44.955 62.586 45.225 ;
     RECT  2.16 45.495 62.586 45.765 ;
     RECT  2.16 46.035 62.586 46.305 ;
     RECT  2.16 46.575 62.586 46.845 ;
     RECT  2.16 47.115 62.586 47.385 ;
     RECT  2.16 47.655 62.586 47.925 ;
     RECT  2.16 48.195 62.586 48.465 ;
     RECT  2.16 48.735 62.586 49.005 ;
     RECT  2.16 49.275 62.586 49.545 ;
     RECT  2.16 49.815 62.586 50.085 ;
     RECT  2.16 50.355 62.586 50.625 ;
     RECT  2.16 50.895 62.586 51.165 ;
     RECT  2.16 51.435 62.586 51.705 ;
     RECT  2.16 51.975 62.586 52.245 ;
     RECT  2.16 52.515 62.586 52.785 ;
     RECT  2.16 53.055 62.586 53.325 ;
     RECT  2.16 53.595 62.586 53.865 ;
     RECT  2.16 54.135 62.586 54.405 ;
     RECT  2.16 54.675 62.586 54.945 ;
     RECT  2.16 55.215 62.586 55.485 ;
     RECT  2.16 55.755 62.586 56.025 ;
     RECT  2.16 56.295 62.586 56.565 ;
     RECT  2.16 56.835 62.586 57.105 ;
     RECT  2.16 57.375 62.586 57.645 ;
     RECT  2.16 57.915 62.586 58.05 ;
    LAYER M1 ;
     RECT  2.16 2.151 62.586 58.059 ;
    LAYER M2 ;
     RECT  21.631 60.39 21.847 60.408 ;
     RECT  21.847 60.201 23.207 60.408 ;
     RECT  23.207 60.201 24.007 60.336 ;
     RECT  24.007 60.201 24.791 60.408 ;
     RECT  2.16 2.151 25.807 58.059 ;
     RECT  25.807 2.151 25.879 58.104 ;
     RECT  24.791 60.246 25.951 60.408 ;
     RECT  25.951 59.58 26.095 60.408 ;
     RECT  25.879 2.151 26.167 58.14 ;
     RECT  26.167 2.151 26.267 58.212 ;
     RECT  26.267 2.151 27.031 58.104 ;
     RECT  27.031 2.151 27.103 58.644 ;
     RECT  27.103 2.151 27.815 58.716 ;
     RECT  26.095 59.544 27.887 60.408 ;
     RECT  27.887 59.544 29.119 59.598 ;
     RECT  28.651 60.39 29.119 60.408 ;
     RECT  27.815 2.151 29.299 58.176 ;
     RECT  29.119 59.544 29.299 60.408 ;
     RECT  29.299 2.151 30.083 60.408 ;
     RECT  30.083 58.968 32.495 60.408 ;
     RECT  32.495 58.968 33.223 59.598 ;
     RECT  32.495 60.39 33.223 60.408 ;
     RECT  33.223 58.968 34.799 60.408 ;
     RECT  34.799 59.742 35.159 60.408 ;
     RECT  35.159 60.012 35.231 60.408 ;
     RECT  35.231 60.201 35.447 60.408 ;
     RECT  35.447 60.246 36.175 60.264 ;
     RECT  30.083 2.151 36.607 58.176 ;
     RECT  36.175 60.246 36.607 60.408 ;
     RECT  36.607 60.201 36.923 60.408 ;
     RECT  36.923 60.282 36.995 60.408 ;
     RECT  36.607 2.151 37.615 58.212 ;
     RECT  34.799 58.968 37.615 58.986 ;
     RECT  37.615 2.151 37.831 58.986 ;
     RECT  37.831 2.151 38.011 59.598 ;
     RECT  36.995 60.39 38.011 60.408 ;
     RECT  38.011 2.151 38.507 60.408 ;
     RECT  38.507 2.151 40.315 58.176 ;
     RECT  38.507 58.968 40.315 60.408 ;
     RECT  40.315 2.151 40.451 60.408 ;
     RECT  40.451 2.151 40.595 59.598 ;
     RECT  40.595 2.151 40.811 59.562 ;
     RECT  40.451 60.39 41.323 60.408 ;
     RECT  40.811 58.968 41.719 59.562 ;
     RECT  41.323 60.318 41.719 60.408 ;
     RECT  41.719 58.968 42.143 60.408 ;
     RECT  40.811 2.151 42.151 58.176 ;
     RECT  42.143 58.968 42.151 59.562 ;
     RECT  42.151 2.151 42.871 59.562 ;
     RECT  42.143 60.354 42.871 60.408 ;
     RECT  42.871 2.151 45.311 60.408 ;
     RECT  45.311 58.968 45.859 60.408 ;
     RECT  45.311 2.151 46.399 58.176 ;
     RECT  45.859 58.968 46.399 60.444 ;
     RECT  46.399 2.151 47.399 60.444 ;
     RECT  47.399 58.968 47.615 60.444 ;
     RECT  47.615 60.39 47.723 60.444 ;
     RECT  47.723 60.426 49.631 60.444 ;
     RECT  47.615 58.968 50.099 59.562 ;
     RECT  50.099 59.544 50.279 59.562 ;
     RECT  47.399 2.151 60.107 58.176 ;
     RECT  60.107 2.151 62.586 58.059 ;
     RECT  62.586 20.088 62.735 57.87 ;
     RECT  62.586 3.816 62.771 19.26 ;
     RECT  62.735 28.188 62.771 57.87 ;
     RECT  62.735 20.286 62.807 27.324 ;
     RECT  62.771 4.626 63.311 18.288 ;
     RECT  62.807 20.358 63.311 27.324 ;
     RECT  62.771 28.188 63.311 28.818 ;
     RECT  62.771 29.574 63.311 36.108 ;
     RECT  62.771 36.864 63.311 57.87 ;
     RECT  63.311 6.12 63.347 9.27 ;
     RECT  63.311 10.026 63.347 17.406 ;
     RECT  63.311 20.358 63.347 25.236 ;
     RECT  63.311 28.26 63.347 28.746 ;
     RECT  63.311 30.384 63.347 34.794 ;
     RECT  63.311 35.55 63.347 36.108 ;
     RECT  63.311 37.368 63.347 42.786 ;
     RECT  63.311 43.686 63.347 47.988 ;
     RECT  63.311 51.444 63.347 53.01 ;
     RECT  63.311 4.626 63.383 5.292 ;
     RECT  63.347 10.026 63.383 14.706 ;
     RECT  63.347 22.671 63.383 25.2 ;
     RECT  63.347 37.368 63.383 37.926 ;
     RECT  63.347 43.812 63.383 47.718 ;
     RECT  63.347 38.682 63.779 42.786 ;
     RECT  63.347 6.12 63.815 7.254 ;
     RECT  63.383 43.812 63.851 44.136 ;
     RECT  62.771 3.816 63.887 3.834 ;
     RECT  63.383 5.274 63.887 5.292 ;
     RECT  63.815 6.12 63.887 7.182 ;
     RECT  63.347 8.208 63.887 9 ;
     RECT  63.383 10.026 63.887 11.502 ;
     RECT  63.383 12.366 63.887 14.706 ;
     RECT  63.347 15.696 63.887 17.406 ;
     RECT  63.311 18.198 63.887 18.216 ;
     RECT  62.771 19.044 63.887 19.26 ;
     RECT  63.347 20.358 63.887 21.924 ;
     RECT  63.383 22.788 63.887 23.184 ;
     RECT  63.383 24.102 63.887 25.2 ;
     RECT  63.311 25.992 63.887 27.324 ;
     RECT  63.347 28.296 63.887 28.746 ;
     RECT  63.311 29.574 63.887 29.592 ;
     RECT  63.347 30.384 63.887 34.758 ;
     RECT  63.347 36.054 63.887 36.108 ;
     RECT  63.383 37.368 63.887 37.89 ;
     RECT  63.779 38.682 63.887 39.384 ;
     RECT  63.779 40.41 63.887 42.786 ;
     RECT  63.851 43.812 63.887 44.1 ;
     RECT  63.383 44.928 63.887 47.718 ;
     RECT  63.311 48.744 63.887 50.346 ;
     RECT  63.347 51.606 63.887 53.01 ;
     RECT  63.311 53.874 63.887 57.708 ;
     RECT  63.887 6.822 63.923 6.984 ;
     RECT  63.887 10.026 63.923 10.044 ;
     RECT  63.887 11.376 63.923 11.394 ;
     RECT  63.887 12.366 63.923 12.888 ;
     RECT  63.887 14.382 63.923 14.4 ;
     RECT  63.887 16.731 63.923 16.83 ;
     RECT  63.887 19.08 63.923 19.26 ;
     RECT  63.887 20.466 63.923 20.754 ;
     RECT  63.887 21.906 63.923 21.924 ;
     RECT  63.887 24.102 63.923 25.002 ;
     RECT  63.887 26.64 63.923 27.09 ;
     RECT  63.887 28.422 63.923 28.548 ;
     RECT  63.887 31.356 63.923 31.374 ;
     RECT  63.887 32.472 63.923 32.49 ;
     RECT  63.887 33.696 63.923 34.146 ;
     RECT  63.887 37.368 63.923 37.494 ;
     RECT  63.887 38.826 63.923 39.006 ;
     RECT  63.887 40.536 63.923 40.932 ;
     RECT  63.887 41.724 63.923 41.742 ;
     RECT  63.887 45.036 63.923 45.45 ;
     RECT  63.887 47.16 63.923 47.718 ;
     RECT  63.887 49.788 63.923 50.04 ;
     RECT  63.887 51.606 63.923 52.704 ;
     RECT  63.887 53.874 63.923 54.009 ;
     RECT  63.887 55.764 63.923 55.782 ;
     RECT  63.887 56.808 63.923 57.672 ;
     RECT  63.923 6.966 63.959 6.984 ;
     RECT  63.923 12.528 63.959 12.78 ;
     RECT  63.923 16.812 63.959 16.83 ;
     RECT  63.923 19.08 63.959 19.134 ;
     RECT  63.923 20.736 63.959 20.754 ;
     RECT  63.923 24.102 63.959 24.39 ;
     RECT  63.923 26.838 63.959 26.856 ;
     RECT  63.923 28.53 63.959 28.548 ;
     RECT  63.923 33.822 63.959 34.146 ;
     RECT  63.887 36.054 63.959 36.072 ;
     RECT  63.923 37.476 63.959 37.494 ;
     RECT  63.923 38.826 63.959 38.844 ;
     RECT  63.923 40.536 63.959 40.554 ;
     RECT  63.887 42.732 63.959 42.75 ;
     RECT  63.923 45.306 63.959 45.324 ;
     RECT  63.923 47.466 63.959 47.484 ;
     RECT  63.923 51.948 63.959 51.966 ;
     RECT  63.923 53.874 63.959 53.892 ;
     RECT  63.923 57.348 63.959 57.672 ;
     RECT  63.959 33.822 63.995 34.074 ;
     RECT  63.959 57.654 63.995 57.672 ;
     RECT  63.959 19.116 64.031 19.134 ;
     RECT  64.651 18.126 64.751 18.144 ;
     RECT  64.651 21.402 64.751 21.42 ;
     RECT  64.651 29.736 64.751 29.754 ;
     RECT  63.995 34.056 64.751 34.074 ;
     RECT  64.651 41.346 64.751 41.364 ;
     RECT  64.651 44.352 64.751 44.37 ;
     RECT  64.651 49.356 64.751 49.374 ;
    LAYER M3 ;
     RECT  2.415 2.143 2.505 2.413 ;
     RECT  5.115 2.143 5.205 2.413 ;
     RECT  7.815 2.143 7.905 2.413 ;
     RECT  10.515 2.143 10.605 2.413 ;
     RECT  13.215 2.143 13.305 2.413 ;
     RECT  15.915 2.143 16.005 2.413 ;
     RECT  18.615 2.143 18.705 2.413 ;
     RECT  21.315 2.143 21.405 2.413 ;
     RECT  24.015 2.143 24.105 2.413 ;
     RECT  26.715 2.143 26.805 2.413 ;
     RECT  29.415 2.143 29.505 2.413 ;
     RECT  32.115 2.143 32.205 2.413 ;
     RECT  34.815 2.143 34.905 2.413 ;
     RECT  37.515 2.143 37.605 2.413 ;
     RECT  40.215 2.143 40.305 2.413 ;
     RECT  42.915 2.143 43.005 2.413 ;
     RECT  45.615 2.143 45.705 2.413 ;
     RECT  48.315 2.143 48.405 2.413 ;
     RECT  51.015 2.143 51.105 2.413 ;
     RECT  53.715 2.143 53.805 2.413 ;
     RECT  56.415 2.143 56.505 2.413 ;
     RECT  59.115 2.143 59.205 2.413 ;
     RECT  61.815 2.143 61.905 2.413 ;
     RECT  56.415 2.413 56.697 3.649 ;
     RECT  59.115 2.413 59.397 3.649 ;
     RECT  61.815 2.413 62.097 3.721 ;
     RECT  57.96 3.721 58.05 3.811 ;
     RECT  58.788 3.649 59.397 3.811 ;
     RECT  61.56 3.721 62.097 3.811 ;
     RECT  63.864 3.787 63.882 3.839 ;
     RECT  57.96 3.811 59.85 3.875 ;
     RECT  61.02 3.811 62.694 3.955 ;
     RECT  58.608 3.875 59.85 3.991 ;
     RECT  61.02 3.955 62.73 3.991 ;
     RECT  58.608 3.991 62.73 4.171 ;
     RECT  56.415 3.649 57.186 4.189 ;
     RECT  56.415 4.189 57.762 4.379 ;
     RECT  55.512 4.507 55.53 4.621 ;
     RECT  57.456 4.379 57.762 4.621 ;
     RECT  58.608 4.171 63.378 4.621 ;
     RECT  52.704 4.423 52.722 4.801 ;
     RECT  53.715 2.413 53.997 4.801 ;
     RECT  55.512 4.621 55.674 4.891 ;
     RECT  55.476 4.891 55.674 4.919 ;
     RECT  52.704 4.801 53.997 5.071 ;
     RECT  52.704 5.071 54.162 5.269 ;
     RECT  55.476 4.919 55.494 5.269 ;
     RECT  57.456 4.621 63.378 5.269 ;
     RECT  52.704 5.269 55.494 5.611 ;
     RECT  52.128 5.611 55.494 5.639 ;
     RECT  56.415 4.379 56.697 5.701 ;
     RECT  57.456 5.269 63.882 5.701 ;
     RECT  54.972 5.639 55.494 5.845 ;
     RECT  56.415 5.701 63.882 5.845 ;
     RECT  54.972 5.845 63.882 5.873 ;
     RECT  32.115 2.413 32.397 5.971 ;
     RECT  48.315 2.413 48.597 6.007 ;
     RECT  52.128 5.639 54.162 6.035 ;
     RECT  51.015 2.413 51.297 6.043 ;
     RECT  50.472 6.043 51.297 6.313 ;
     RECT  52.128 6.035 54.054 6.313 ;
     RECT  36.18 4.225 36.198 6.421 ;
     RECT  32.115 5.971 32.85 6.511 ;
     RECT  34.815 2.413 35.097 6.511 ;
     RECT  36.18 6.421 36.558 6.539 ;
     RECT  45.615 2.413 45.897 6.583 ;
     RECT  47.016 4.765 47.034 6.583 ;
     RECT  34.776 6.511 35.097 6.719 ;
     RECT  54.972 5.873 62.37 6.763 ;
     RECT  63.252 5.873 63.882 6.817 ;
     RECT  54.972 6.763 62.406 6.853 ;
     RECT  63.252 6.817 63.918 6.853 ;
     RECT  39.024 3.721 39.042 6.889 ;
     RECT  40.215 2.413 40.497 6.889 ;
     RECT  50.472 6.313 54.054 6.889 ;
     RECT  54.972 6.853 63.918 6.889 ;
     RECT  50.472 6.889 63.918 6.961 ;
     RECT  42.915 2.413 43.197 7.465 ;
     RECT  44.136 7.159 44.154 7.465 ;
     RECT  50.472 6.961 63.954 7.469 ;
     RECT  41.292 7.231 41.31 7.501 ;
     RECT  41.292 7.501 41.886 7.627 ;
     RECT  42.915 7.465 44.154 7.627 ;
     RECT  45.615 6.583 47.034 7.663 ;
     RECT  45.615 7.663 47.574 7.969 ;
     RECT  48.315 6.007 49.194 8.005 ;
     RECT  50.472 7.469 63.342 8.005 ;
     RECT  48.315 8.005 63.342 8.197 ;
     RECT  41.292 7.627 44.154 8.311 ;
     RECT  45.288 7.969 47.574 8.311 ;
     RECT  48.315 8.197 63.882 8.771 ;
     RECT  48.315 8.771 55.062 9.499 ;
     RECT  55.872 8.771 63.882 9.499 ;
     RECT  48.315 9.499 63.882 9.545 ;
     RECT  55.872 9.545 63.882 9.739 ;
     RECT  48.315 9.545 55.062 9.779 ;
     RECT  41.292 8.311 47.574 10.327 ;
     RECT  48.315 9.779 54.99 10.327 ;
     RECT  41.292 10.327 54.99 10.651 ;
     RECT  55.872 9.739 63.918 10.651 ;
     RECT  39.024 6.889 40.497 11.209 ;
     RECT  37.515 2.413 37.797 11.515 ;
     RECT  38.592 11.209 40.497 11.515 ;
     RECT  37.515 11.515 40.497 11.749 ;
     RECT  41.292 10.651 63.918 11.749 ;
     RECT  34.815 6.719 35.097 11.821 ;
     RECT  36.18 6.539 36.198 11.821 ;
     RECT  37.515 11.749 63.918 12.331 ;
     RECT  37.515 12.331 63.954 12.659 ;
     RECT  63.288 12.659 63.954 13.037 ;
     RECT  63.288 13.037 63.882 13.133 ;
     RECT  37.515 12.659 62.097 13.387 ;
     RECT  34.815 11.821 36.198 13.405 ;
     RECT  37.515 13.387 62.766 13.405 ;
     RECT  34.815 13.405 62.766 13.909 ;
     RECT  34.815 13.909 62.802 14.251 ;
     RECT  63.864 13.133 63.882 14.251 ;
     RECT  34.815 14.251 63.882 14.377 ;
     RECT  34.815 14.377 63.918 14.573 ;
     RECT  34.815 14.573 63.882 15.323 ;
     RECT  34.815 15.323 62.766 16.075 ;
     RECT  63.864 15.323 63.882 16.075 ;
     RECT  34.815 16.075 63.882 16.363 ;
     RECT  34.815 16.363 63.918 16.459 ;
     RECT  31.392 6.511 32.85 16.501 ;
     RECT  26.715 2.413 26.997 16.645 ;
     RECT  31.392 16.501 33.39 16.771 ;
     RECT  34.815 16.459 63.954 16.807 ;
     RECT  31.392 16.771 34.038 16.829 ;
     RECT  34.776 16.807 63.954 16.835 ;
     RECT  34.776 16.835 63.882 16.943 ;
     RECT  28.368 17.383 28.386 17.959 ;
     RECT  64.656 18.091 64.674 18.121 ;
     RECT  64.656 18.121 64.746 18.149 ;
     RECT  31.392 16.829 33.966 18.157 ;
     RECT  34.815 16.943 63.882 18.157 ;
     RECT  64.728 18.149 64.746 18.173 ;
     RECT  31.392 18.157 63.882 18.317 ;
     RECT  26.715 16.645 27.414 18.499 ;
     RECT  28.368 17.959 28.674 18.499 ;
     RECT  31.392 18.317 62.766 18.563 ;
     RECT  26.715 18.499 28.674 18.697 ;
     RECT  29.415 2.413 29.697 18.697 ;
     RECT  63.864 18.317 63.882 18.763 ;
     RECT  63.864 18.763 63.918 18.859 ;
     RECT  63.864 18.859 63.954 18.955 ;
     RECT  63.864 18.955 64.026 19.067 ;
     RECT  31.392 18.563 62.73 19.085 ;
     RECT  63.9 19.067 64.026 19.139 ;
     RECT  63.9 19.139 63.918 19.265 ;
     RECT  30.528 9.931 30.546 19.885 ;
     RECT  31.392 19.085 62.097 19.885 ;
     RECT  30.528 19.885 62.097 19.915 ;
     RECT  30.528 19.915 62.73 20.011 ;
     RECT  30.528 20.011 63.306 20.107 ;
     RECT  26.715 18.697 29.697 20.191 ;
     RECT  30.528 20.107 63.882 20.191 ;
     RECT  26.715 20.191 63.882 20.203 ;
     RECT  26.715 20.203 63.918 20.395 ;
     RECT  26.715 20.395 63.954 20.417 ;
     RECT  63.864 20.417 63.954 20.759 ;
     RECT  26.715 20.417 62.802 21.259 ;
     RECT  63.864 20.759 63.882 21.259 ;
     RECT  64.656 21.355 64.674 21.397 ;
     RECT  64.656 21.397 64.746 21.425 ;
     RECT  64.728 21.425 64.746 21.437 ;
     RECT  26.715 21.259 63.882 21.901 ;
     RECT  26.715 21.901 63.918 22.349 ;
     RECT  26.715 22.349 63.882 23.213 ;
     RECT  26.715 23.213 63.378 23.947 ;
     RECT  26.715 23.947 63.882 24.043 ;
     RECT  26.715 24.043 63.918 24.097 ;
     RECT  26.715 24.097 63.954 24.395 ;
     RECT  24.015 2.413 24.297 24.943 ;
     RECT  25.416 24.871 25.434 24.943 ;
     RECT  22.5 24.601 22.518 24.979 ;
     RECT  26.715 24.395 63.918 25.007 ;
     RECT  26.715 25.007 63.882 25.205 ;
     RECT  22.5 24.979 22.59 25.483 ;
     RECT  24.015 24.943 25.434 25.789 ;
     RECT  26.715 25.205 63.342 25.963 ;
     RECT  24.015 25.789 25.866 26.131 ;
     RECT  26.715 25.963 63.882 26.347 ;
     RECT  26.715 26.347 63.918 26.443 ;
     RECT  24.015 26.131 25.974 26.491 ;
     RECT  22.5 25.483 23.094 26.671 ;
     RECT  23.868 26.491 25.974 26.671 ;
     RECT  22.5 26.671 25.974 26.761 ;
     RECT  26.715 26.443 63.954 26.761 ;
     RECT  22.5 26.761 63.954 26.861 ;
     RECT  22.5 26.861 63.918 27.095 ;
     RECT  22.5 27.095 63.882 27.245 ;
     RECT  63.864 27.245 63.882 27.979 ;
     RECT  21.315 2.413 21.597 28.183 ;
     RECT  22.5 27.245 62.766 28.183 ;
     RECT  63.864 27.979 63.918 28.183 ;
     RECT  2.415 2.413 2.697 28.255 ;
     RECT  21.315 28.183 63.918 28.525 ;
     RECT  21.315 28.525 63.954 28.781 ;
     RECT  2.415 28.255 2.79 28.921 ;
     RECT  2.304 28.921 2.79 28.939 ;
     RECT  2.304 28.939 3.438 29.069 ;
     RECT  2.415 29.069 3.438 29.335 ;
     RECT  2.415 29.335 3.978 29.461 ;
     RECT  5.115 2.413 5.397 29.461 ;
     RECT  7.815 2.413 8.097 29.467 ;
     RECT  2.415 29.461 5.397 29.549 ;
     RECT  2.415 29.549 4.302 29.597 ;
     RECT  7.815 29.467 8.19 29.597 ;
     RECT  14.832 29.467 14.85 29.597 ;
     RECT  64.656 29.707 64.674 29.731 ;
     RECT  64.656 29.731 64.746 29.759 ;
     RECT  64.728 29.759 64.746 29.789 ;
     RECT  2.415 29.597 3.726 29.803 ;
     RECT  15.915 2.413 16.197 30.001 ;
     RECT  2.232 29.803 3.726 30.029 ;
     RECT  2.232 30.029 3.438 30.209 ;
     RECT  2.304 30.209 3.438 30.569 ;
     RECT  2.304 30.569 2.97 31.109 ;
     RECT  2.304 31.109 2.697 31.145 ;
     RECT  21.315 28.781 63.882 31.351 ;
     RECT  21.315 31.351 63.918 31.565 ;
     RECT  21.315 31.565 63.882 32.099 ;
     RECT  61.704 32.099 63.882 32.395 ;
     RECT  21.315 32.099 60.966 33.151 ;
     RECT  61.704 32.395 63.918 33.151 ;
     RECT  21.315 33.151 63.918 33.355 ;
     RECT  21.315 33.355 63.954 33.547 ;
     RECT  21.315 33.547 63.99 34.027 ;
     RECT  21.315 34.027 64.674 34.051 ;
     RECT  21.315 34.051 64.746 34.079 ;
     RECT  64.728 34.079 64.746 34.109 ;
     RECT  21.315 34.079 63.954 34.151 ;
     RECT  21.315 34.151 63.882 34.763 ;
     RECT  21.315 34.763 63.342 35.741 ;
     RECT  56.415 35.741 63.342 35.947 ;
     RECT  56.415 35.947 63.882 36.049 ;
     RECT  21.315 35.741 55.674 36.149 ;
     RECT  56.415 36.049 63.954 36.239 ;
     RECT  61.128 36.239 63.954 36.269 ;
     RECT  61.128 36.269 63.306 37.037 ;
     RECT  51.015 36.149 55.674 37.129 ;
     RECT  56.415 36.239 60.282 37.129 ;
     RECT  61.128 37.037 62.226 37.129 ;
     RECT  63.288 37.037 63.306 37.195 ;
     RECT  63.288 37.195 63.882 37.291 ;
     RECT  51.015 37.129 60.282 37.363 ;
     RECT  61.056 37.129 62.226 37.363 ;
     RECT  21.315 36.149 50.202 37.435 ;
     RECT  51.015 37.363 62.226 37.435 ;
     RECT  63.288 37.291 63.954 37.499 ;
     RECT  21.315 37.435 62.226 37.589 ;
     RECT  63.288 37.499 63.882 37.963 ;
     RECT  51.015 37.589 62.226 38.059 ;
     RECT  63.216 37.963 63.882 38.059 ;
     RECT  51.015 38.059 63.882 38.309 ;
     RECT  63.864 38.309 63.882 38.443 ;
     RECT  63.864 38.443 63.918 38.539 ;
     RECT  51.015 38.309 62.73 38.543 ;
     RECT  51.015 38.543 62.19 38.741 ;
     RECT  63.864 38.539 63.954 38.849 ;
     RECT  63.864 38.849 63.918 39.011 ;
     RECT  63.864 39.011 63.882 39.055 ;
     RECT  51.015 38.741 62.097 39.523 ;
     RECT  63.18 39.055 63.882 39.523 ;
     RECT  51.015 39.523 63.882 40.363 ;
     RECT  51.015 40.363 63.918 40.459 ;
     RECT  21.315 37.589 50.202 40.531 ;
     RECT  51.015 40.459 63.954 40.531 ;
     RECT  21.315 40.531 63.954 40.559 ;
     RECT  21.315 40.559 63.918 40.937 ;
     RECT  21.315 40.937 63.882 40.973 ;
     RECT  21.315 40.973 62.766 41.009 ;
     RECT  21.315 41.009 61.002 41.207 ;
     RECT  64.656 41.323 64.674 41.341 ;
     RECT  64.656 41.341 64.746 41.369 ;
     RECT  64.728 41.369 64.746 41.405 ;
     RECT  63.864 40.973 63.882 41.719 ;
     RECT  51.015 41.207 61.002 41.917 ;
     RECT  61.815 41.009 62.766 41.917 ;
     RECT  21.315 41.207 50.202 41.953 ;
     RECT  51.015 41.917 62.766 41.953 ;
     RECT  21.315 41.953 62.766 42.089 ;
     RECT  51.015 42.089 62.766 42.187 ;
     RECT  63.864 41.719 63.918 42.187 ;
     RECT  51.015 42.187 63.918 42.379 ;
     RECT  51.015 42.379 63.954 42.755 ;
     RECT  21.315 42.089 50.202 42.835 ;
     RECT  51.015 42.755 63.882 42.835 ;
     RECT  21.315 42.835 63.882 42.989 ;
     RECT  51.015 42.989 63.882 43.097 ;
     RECT  61.236 43.097 63.882 43.259 ;
     RECT  21.315 42.989 50.202 43.915 ;
     RECT  51.015 43.097 60.39 43.915 ;
     RECT  61.272 43.259 63.882 44.041 ;
     RECT  21.315 43.915 60.39 44.141 ;
     RECT  51.015 44.141 60.39 44.185 ;
     RECT  61.164 44.041 63.882 44.185 ;
     RECT  64.656 44.299 64.674 44.347 ;
     RECT  64.656 44.347 64.746 44.375 ;
     RECT  64.728 44.375 64.746 44.384 ;
     RECT  51.015 44.185 63.882 44.477 ;
     RECT  51.015 44.477 60.966 44.789 ;
     RECT  61.776 44.477 63.882 44.971 ;
     RECT  61.776 44.971 63.918 45.058 ;
     RECT  61.776 45.058 63.954 45.329 ;
     RECT  53.715 44.789 60.966 45.499 ;
     RECT  61.776 45.329 63.918 45.499 ;
     RECT  53.715 45.499 63.918 45.731 ;
     RECT  53.715 45.731 61.002 46.843 ;
     RECT  61.815 45.731 63.918 46.843 ;
     RECT  53.715 46.843 63.918 47.461 ;
     RECT  53.715 47.461 63.954 48.269 ;
     RECT  21.315 44.141 50.202 48.859 ;
     RECT  51.015 44.789 52.758 48.859 ;
     RECT  21.315 48.859 52.758 49.199 ;
     RECT  64.728 49.339 64.746 49.351 ;
     RECT  64.656 49.351 64.746 49.379 ;
     RECT  64.656 49.379 64.674 49.421 ;
     RECT  53.715 48.269 63.882 49.675 ;
     RECT  53.715 49.675 63.918 50.045 ;
     RECT  53.715 50.045 63.882 50.381 ;
     RECT  53.715 50.381 63.306 51.439 ;
     RECT  53.715 51.439 63.342 51.595 ;
     RECT  53.715 51.595 63.882 51.601 ;
     RECT  53.715 51.601 63.918 51.809 ;
     RECT  63.288 51.809 63.918 51.943 ;
     RECT  21.315 49.199 50.202 52.015 ;
     RECT  51.015 49.199 52.758 52.015 ;
     RECT  63.288 51.943 63.954 52.109 ;
     RECT  21.315 52.015 52.758 52.169 ;
     RECT  51.015 52.169 52.758 52.313 ;
     RECT  53.715 51.809 62.19 52.448 ;
     RECT  61.344 52.448 62.19 52.555 ;
     RECT  63.288 52.109 63.918 52.555 ;
     RECT  61.344 52.555 63.918 53.069 ;
     RECT  53.715 52.448 60.57 53.515 ;
     RECT  53.715 53.515 60.606 53.755 ;
     RECT  61.344 53.069 63.882 53.755 ;
     RECT  53.715 53.755 63.882 53.869 ;
     RECT  53.715 53.869 63.954 54.125 ;
     RECT  15.48 30.001 16.197 54.329 ;
     RECT  53.715 54.125 63.882 54.635 ;
     RECT  21.315 52.169 50.202 54.715 ;
     RECT  51.015 52.313 52.722 54.715 ;
     RECT  53.715 54.635 61.038 54.869 ;
     RECT  21.315 54.715 52.722 55.013 ;
     RECT  61.815 54.635 63.882 55.339 ;
     RECT  53.715 54.869 61.002 55.651 ;
     RECT  61.815 55.339 63.918 55.651 ;
     RECT  53.715 55.651 63.918 56.141 ;
     RECT  63.864 56.141 63.918 56.779 ;
     RECT  53.715 56.141 62.766 56.875 ;
     RECT  63.864 56.779 63.954 56.875 ;
     RECT  21.315 55.013 50.274 57.037 ;
     RECT  51.015 55.013 52.722 57.037 ;
     RECT  21.315 57.037 52.722 57.209 ;
     RECT  53.715 56.875 63.954 57.259 ;
     RECT  53.715 57.259 63.99 57.299 ;
     RECT  61.596 57.299 63.99 57.407 ;
     RECT  53.715 57.299 60.534 57.479 ;
     RECT  61.596 57.407 62.097 57.479 ;
     RECT  56.16 57.479 60.534 57.569 ;
     RECT  21.315 57.209 52.146 57.605 ;
     RECT  63.288 57.407 63.99 57.677 ;
     RECT  53.715 57.479 55.314 57.713 ;
     RECT  63.288 57.677 63.882 57.713 ;
     RECT  58.428 57.569 60.534 57.749 ;
     RECT  2.415 31.145 2.697 57.797 ;
     RECT  5.115 29.549 5.397 57.797 ;
     RECT  7.815 29.597 8.097 57.797 ;
     RECT  10.515 2.413 10.797 57.797 ;
     RECT  13.215 2.413 13.497 57.797 ;
     RECT  15.915 54.329 16.197 57.797 ;
     RECT  18.615 2.413 18.897 57.797 ;
     RECT  21.315 57.605 51.297 57.797 ;
     RECT  53.715 57.713 53.997 57.797 ;
     RECT  58.428 57.749 60.354 57.797 ;
     RECT  61.815 57.479 62.097 57.797 ;
     RECT  52.128 57.605 52.146 57.839 ;
     RECT  54.972 57.713 55.314 57.839 ;
     RECT  21.507 57.797 51.297 57.875 ;
     RECT  63.288 57.713 63.306 57.875 ;
     RECT  54.972 57.839 54.99 57.911 ;
     RECT  56.16 57.569 57.114 57.983 ;
     RECT  59.307 57.797 60.354 58.019 ;
     RECT  2.607 57.797 2.697 58.067 ;
     RECT  5.307 57.797 5.397 58.067 ;
     RECT  8.007 57.797 8.097 58.067 ;
     RECT  10.707 57.797 10.797 58.067 ;
     RECT  13.407 57.797 13.497 58.067 ;
     RECT  16.107 57.797 16.197 58.067 ;
     RECT  18.807 57.797 18.897 58.067 ;
     RECT  21.507 57.875 50.274 58.067 ;
     RECT  51.207 57.875 51.297 58.067 ;
     RECT  53.907 57.797 53.997 58.067 ;
     RECT  56.607 57.983 57.114 58.067 ;
     RECT  59.307 58.019 60.102 58.067 ;
     RECT  62.007 57.797 62.097 58.067 ;
     RECT  58.428 57.797 58.446 58.145 ;
     RECT  57.06 58.067 57.114 58.157 ;
     RECT  60.084 58.067 60.102 58.181 ;
     RECT  21.708 58.067 48.006 58.973 ;
     RECT  57.096 58.157 57.114 59.549 ;
     RECT  49.104 58.067 50.274 59.567 ;
     RECT  49.104 59.567 49.626 59.645 ;
     RECT  21.708 58.973 47.97 59.789 ;
     RECT  21.708 59.789 47.718 60.385 ;
     RECT  21.636 60.385 47.718 60.413 ;
     RECT  21.636 60.413 47.502 60.444 ;
     RECT  45.864 60.444 45.882 60.449 ;
     RECT  49.608 59.645 49.626 60.449 ;
    LAYER M4 ;
     RECT  0.06 29.616 0.133 29.832 ;
     RECT  0.133 29.52 0.517 29.832 ;
     RECT  0.517 29.52 2.293 30.072 ;
     RECT  2.293 29.04 2.408 30.408 ;
     RECT  2.408 2.148 2.512 57.792 ;
     RECT  2.512 2.418 2.6 57.792 ;
     RECT  2.6 2.418 2.704 58.062 ;
     RECT  2.704 28.8 2.915 31.032 ;
     RECT  2.915 28.944 2.953 31.032 ;
     RECT  2.953 28.944 3.347 30.888 ;
     RECT  3.347 28.944 3.443 30.408 ;
     RECT  3.443 28.944 3.449 30.264 ;
     RECT  3.449 29.04 3.539 30.264 ;
     RECT  3.539 29.52 5.108 30.072 ;
     RECT  4.213 32.016 5.108 32.04 ;
     RECT  5.108 2.148 5.212 57.792 ;
     RECT  5.212 2.418 5.3 57.792 ;
     RECT  5.3 2.418 5.404 58.062 ;
     RECT  5.404 29.568 7.808 29.592 ;
     RECT  5.404 32.016 7.808 32.04 ;
     RECT  7.808 2.148 7.912 57.792 ;
     RECT  7.912 2.418 8 57.792 ;
     RECT  8 2.418 8.104 58.062 ;
     RECT  8.104 29.472 8.201 29.592 ;
     RECT  8.201 29.472 10.508 29.496 ;
     RECT  8.104 32.016 10.508 32.04 ;
     RECT  10.508 2.148 10.612 57.792 ;
     RECT  10.612 2.418 10.7 57.792 ;
     RECT  10.7 2.418 10.804 58.062 ;
     RECT  10.804 29.472 13.208 29.496 ;
     RECT  10.804 32.016 13.208 32.04 ;
     RECT  13.208 2.148 13.312 57.792 ;
     RECT  13.312 2.418 13.4 57.792 ;
     RECT  13.4 2.418 13.504 58.062 ;
     RECT  13.504 29.472 14.821 29.496 ;
     RECT  14.821 29.472 14.861 29.592 ;
     RECT  14.861 29.568 15.908 29.592 ;
     RECT  13.504 32.016 15.908 32.04 ;
     RECT  15.908 2.148 16.012 57.792 ;
     RECT  16.012 2.418 16.1 57.792 ;
     RECT  16.1 2.418 16.204 58.062 ;
     RECT  16.204 29.568 18.608 29.592 ;
     RECT  16.204 32.016 18.608 32.04 ;
     RECT  18.608 2.148 18.712 57.792 ;
     RECT  18.712 2.418 18.8 57.792 ;
     RECT  18.8 2.418 18.904 58.062 ;
     RECT  18.904 29.568 21.308 29.592 ;
     RECT  18.904 32.016 21.308 32.04 ;
     RECT  21.308 2.148 21.412 57.792 ;
     RECT  21.412 2.418 21.5 57.792 ;
     RECT  21.5 2.418 21.604 58.062 ;
     RECT  21.604 29.472 21.701 29.592 ;
     RECT  21.701 29.472 22.813 29.496 ;
     RECT  22.813 29.472 22.853 29.592 ;
     RECT  22.853 29.568 24.008 29.592 ;
     RECT  21.604 32.016 24.008 32.04 ;
     RECT  24.008 2.148 24.112 57.792 ;
     RECT  24.112 2.418 24.2 57.792 ;
     RECT  24.2 2.418 24.304 58.062 ;
     RECT  25.117 60.384 25.265 60.408 ;
     RECT  26.053 40.128 26.149 40.152 ;
     RECT  26.089 58.176 26.245 58.2 ;
     RECT  25.981 59.28 26.245 59.304 ;
     RECT  26.269 56.496 26.305 56.52 ;
     RECT  26.305 56.496 26.341 56.616 ;
     RECT  26.245 58.176 26.341 59.304 ;
     RECT  26.341 56.496 26.449 59.304 ;
     RECT  24.304 32.016 26.581 32.04 ;
     RECT  26.449 56.448 26.581 59.304 ;
     RECT  26.581 56.448 26.629 60.168 ;
     RECT  24.304 29.568 26.708 29.592 ;
     RECT  26.581 32.016 26.708 32.328 ;
     RECT  26.437 37.584 26.708 37.608 ;
     RECT  25.957 39.024 26.708 39.048 ;
     RECT  26.149 40.128 26.708 40.872 ;
     RECT  26.485 50.832 26.708 50.856 ;
     RECT  26.629 56.448 26.708 60.36 ;
     RECT  26.708 2.148 26.812 60.36 ;
     RECT  26.812 2.418 27.004 60.36 ;
     RECT  27.004 50.832 27.065 52.728 ;
     RECT  27.004 56.496 27.203 60.36 ;
     RECT  27.004 31.296 27.281 32.472 ;
     RECT  27.004 33.648 27.353 34.2 ;
     RECT  27.203 56.496 27.353 59.304 ;
     RECT  27.353 58.656 27.443 59.304 ;
     RECT  27.203 60.288 27.676 60.36 ;
     RECT  27.353 56.496 27.857 57.432 ;
     RECT  27.676 60.288 27.929 60.408 ;
     RECT  27.857 56.592 27.965 56.616 ;
     RECT  27.281 32.016 27.973 32.472 ;
     RECT  27.004 29.568 28.145 30.216 ;
     RECT  27.443 58.656 28.325 58.68 ;
     RECT  28.145 29.568 28.357 30.12 ;
     RECT  27.973 32.016 28.429 32.568 ;
     RECT  28.261 35.856 28.453 35.88 ;
     RECT  27.929 60.288 28.549 60.36 ;
     RECT  28.429 31.776 28.645 32.568 ;
     RECT  27.065 50.832 28.681 52.2 ;
     RECT  28.549 59.808 28.757 60.36 ;
     RECT  28.757 60.144 28.829 60.36 ;
     RECT  28.645 31.2 28.997 32.568 ;
     RECT  28.165 27.888 29.408 27.912 ;
     RECT  28.357 29.04 29.408 30.12 ;
     RECT  28.997 31.2 29.408 33.048 ;
     RECT  27.353 34.176 29.408 34.2 ;
     RECT  28.453 35.808 29.408 35.88 ;
     RECT  27.004 39.024 29.408 39.048 ;
     RECT  27.004 40.128 29.408 40.872 ;
     RECT  28.837 42 29.408 42.024 ;
     RECT  28.681 50.832 29.408 52.824 ;
     RECT  28.069 55.2 29.408 55.224 ;
     RECT  29.365 58.176 29.408 58.2 ;
     RECT  29.408 2.148 29.512 58.2 ;
     RECT  29.512 2.418 29.704 58.2 ;
     RECT  28.829 60.144 29.797 60.312 ;
     RECT  29.797 59.952 29.842 60.312 ;
     RECT  29.704 55.2 29.873 55.224 ;
     RECT  29.704 57.648 29.941 58.2 ;
     RECT  29.842 59.952 29.989 60.36 ;
     RECT  29.704 31.776 30.197 37.032 ;
     RECT  30.197 33.264 30.233 37.032 ;
     RECT  29.989 59.52 30.241 60.36 ;
     RECT  29.704 42 30.305 42.024 ;
     RECT  30.233 36.24 30.629 37.032 ;
     RECT  30.233 33.264 30.665 35.064 ;
     RECT  30.629 36.24 30.701 36.984 ;
     RECT  29.941 57.648 30.757 58.248 ;
     RECT  30.701 36.24 30.773 36.408 ;
     RECT  29.704 29.472 30.809 30.12 ;
     RECT  30.757 57.552 30.877 58.248 ;
     RECT  29.704 50.832 30.949 52.92 ;
     RECT  30.949 50.736 30.985 52.92 ;
     RECT  30.985 50.736 31.097 53.064 ;
     RECT  30.665 34.656 31.237 35.064 ;
     RECT  30.773 36.24 31.237 36.36 ;
     RECT  29.704 38.448 31.621 39.048 ;
     RECT  30.241 59.52 31.705 59.544 ;
     RECT  31.097 50.832 31.765 53.064 ;
     RECT  31.765 50.832 31.921 53.256 ;
     RECT  30.877 56.976 31.957 58.248 ;
     RECT  31.705 59.52 31.957 60.264 ;
     RECT  31.621 38.448 32.065 39.336 ;
     RECT  31.705 23.856 32.108 23.88 ;
     RECT  30.809 29.568 32.108 30.12 ;
     RECT  30.197 31.776 32.108 32.04 ;
     RECT  30.665 33.264 32.108 33.288 ;
     RECT  31.237 34.656 32.108 36.36 ;
     RECT  32.065 38.16 32.108 39.336 ;
     RECT  31.045 42.72 32.108 42.744 ;
     RECT  31.921 50.832 32.108 53.4 ;
     RECT  31.957 56.592 32.108 58.248 ;
     RECT  32.108 2.148 32.212 58.248 ;
     RECT  32.212 2.418 32.339 58.248 ;
     RECT  32.339 2.418 32.404 58.2 ;
     RECT  32.404 33.264 32.465 33.288 ;
     RECT  32.404 55.968 32.537 58.2 ;
     RECT  32.404 42.72 32.753 42.744 ;
     RECT  32.537 55.968 32.933 58.152 ;
     RECT  32.404 34.656 33.077 39.336 ;
     RECT  32.404 40.416 33.113 41.016 ;
     RECT  31.957 59.52 33.181 60.312 ;
     RECT  32.933 56.736 33.257 58.152 ;
     RECT  33.257 57.024 33.545 58.152 ;
     RECT  33.181 59.52 33.545 60.408 ;
     RECT  33.545 57.12 33.581 58.152 ;
     RECT  32.404 16.992 33.613 17.016 ;
     RECT  33.077 34.656 33.617 38.76 ;
     RECT  33.617 35.232 33.653 38.76 ;
     RECT  33.113 40.992 33.689 41.016 ;
     RECT  33.613 16.992 34.009 17.112 ;
     RECT  33.581 57.168 34.213 58.152 ;
     RECT  33.545 59.52 34.213 59.544 ;
     RECT  33.637 39.888 34.309 39.912 ;
     RECT  33.653 35.76 34.405 38.76 ;
     RECT  34.309 39.888 34.405 40.44 ;
     RECT  32.404 50.832 34.405 52.824 ;
     RECT  34.213 57.168 34.549 59.544 ;
     RECT  34.549 56.976 34.789 59.544 ;
     RECT  34.009 16.8 34.808 17.112 ;
     RECT  32.404 23.856 34.808 23.88 ;
     RECT  34.765 26.784 34.808 26.808 ;
     RECT  32.404 29.568 34.808 30.12 ;
     RECT  32.404 31.776 34.808 32.04 ;
     RECT  34.405 35.76 34.808 40.44 ;
     RECT  34.801 48.768 34.808 48.792 ;
     RECT  34.405 50.304 34.808 52.824 ;
     RECT  33.733 55.248 34.808 55.272 ;
     RECT  34.789 56.976 34.808 60.072 ;
     RECT  34.808 2.148 34.837 60.072 ;
     RECT  34.837 2.148 34.912 60.312 ;
     RECT  34.912 2.418 35.104 60.312 ;
     RECT  35.104 57.84 35.125 60.312 ;
     RECT  35.104 35.472 35.237 39.336 ;
     RECT  35.104 40.416 35.273 40.968 ;
     RECT  35.237 35.472 35.345 39.144 ;
     RECT  35.104 50.832 35.345 53.16 ;
     RECT  35.104 46.752 35.363 48.792 ;
     RECT  35.345 37.392 35.417 39.144 ;
     RECT  35.125 57.84 35.633 60.36 ;
     RECT  35.633 59.52 35.917 60.36 ;
     RECT  35.417 37.392 36.029 39.096 ;
     RECT  35.104 29.04 36.085 30.792 ;
     RECT  35.104 31.776 36.085 32.04 ;
     RECT  36.029 37.392 36.101 39.048 ;
     RECT  35.363 46.752 36.137 47.112 ;
     RECT  36.085 29.04 36.209 32.04 ;
     RECT  35.345 35.472 36.229 36.168 ;
     RECT  36.209 29.04 36.245 30.216 ;
     RECT  35.104 42.768 36.245 42.792 ;
     RECT  36.101 37.632 36.353 39.048 ;
     RECT  35.917 59.52 36.353 60.408 ;
     RECT  36.245 29.568 36.389 30.216 ;
     RECT  36.353 38.64 36.425 39.048 ;
     RECT  35.363 48.144 36.461 48.792 ;
     RECT  35.104 34.128 36.517 34.152 ;
     RECT  36.229 35.328 36.517 36.168 ;
     RECT  35.104 23.856 36.817 23.88 ;
     RECT  36.805 33.072 36.949 33.096 ;
     RECT  36.209 31.776 37.093 32.04 ;
     RECT  36.949 33.072 37.093 33.144 ;
     RECT  36.517 34.128 37.237 36.168 ;
     RECT  37.237 34.128 37.333 36.312 ;
     RECT  36.353 59.52 37.334 60.36 ;
     RECT  35.104 16.8 37.508 17.112 ;
     RECT  36.853 22.176 37.508 22.2 ;
     RECT  36.817 23.856 37.508 24.648 ;
     RECT  36.389 29.568 37.508 30.12 ;
     RECT  37.093 31.776 37.508 33.144 ;
     RECT  37.333 34.128 37.508 36.36 ;
     RECT  36.353 37.632 37.508 37.656 ;
     RECT  36.425 39.024 37.508 39.048 ;
     RECT  35.273 40.944 37.508 40.968 ;
     RECT  36.137 46.752 37.508 46.776 ;
     RECT  36.461 48.144 37.508 48.168 ;
     RECT  35.345 50.832 37.508 52.824 ;
     RECT  36.709 56.4 37.508 56.424 ;
     RECT  35.633 57.84 37.508 58.152 ;
     RECT  37.508 2.148 37.612 58.152 ;
     RECT  37.612 2.418 37.804 58.152 ;
     RECT  37.804 29.472 37.865 36.888 ;
     RECT  37.804 40.944 37.865 40.968 ;
     RECT  37.804 16.8 37.901 17.112 ;
     RECT  37.865 35.904 38.099 36.888 ;
     RECT  37.804 43.296 38.117 43.32 ;
     RECT  37.804 49.584 38.147 49.608 ;
     RECT  37.865 29.472 38.153 34.776 ;
     RECT  37.804 39.024 38.225 39.048 ;
     RECT  37.804 57.84 38.329 58.152 ;
     RECT  37.334 59.52 38.329 60.312 ;
     RECT  37.804 46.752 38.477 46.776 ;
     RECT  38.329 57.84 38.545 60.312 ;
     RECT  38.153 29.472 38.549 34.68 ;
     RECT  38.099 36.288 38.549 36.888 ;
     RECT  38.549 29.472 38.657 34.632 ;
     RECT  38.657 29.472 38.693 34.44 ;
     RECT  38.549 36.336 38.765 36.84 ;
     RECT  38.545 57.84 38.765 60.408 ;
     RECT  37.901 16.8 38.801 16.968 ;
     RECT  38.693 29.472 38.801 30.12 ;
     RECT  38.693 31.296 38.801 34.44 ;
     RECT  38.801 31.296 38.837 34.2 ;
     RECT  37.804 23.856 38.861 23.88 ;
     RECT  38.765 36.432 38.873 36.84 ;
     RECT  38.861 23.856 38.945 24.504 ;
     RECT  37.804 26.88 39.161 27.864 ;
     RECT  39.161 26.88 39.265 26.904 ;
     RECT  39.265 26.736 39.805 26.904 ;
     RECT  38.837 31.776 39.913 34.2 ;
     RECT  39.049 11.712 40.208 11.736 ;
     RECT  38.801 16.8 40.208 16.872 ;
     RECT  38.945 23.856 40.208 23.88 ;
     RECT  39.805 26.64 40.208 26.904 ;
     RECT  39.637 27.936 40.208 27.96 ;
     RECT  38.801 29.568 40.208 30.12 ;
     RECT  39.913 31.776 40.208 34.92 ;
     RECT  38.873 36.528 40.208 36.84 ;
     RECT  39.085 38.544 40.208 38.568 ;
     RECT  39.685 39.84 40.208 39.864 ;
     RECT  37.804 50.832 40.208 52.824 ;
     RECT  38.765 57.84 40.208 60.36 ;
     RECT  40.208 2.148 40.312 60.36 ;
     RECT  40.312 2.418 40.504 60.36 ;
     RECT  40.504 39.84 40.637 39.864 ;
     RECT  40.504 55.248 40.889 55.272 ;
     RECT  40.504 26.64 41.641 28.104 ;
     RECT  40.504 29.328 41.641 34.92 ;
     RECT  40.504 45.552 41.677 45.576 ;
     RECT  41.641 26.64 41.717 34.92 ;
     RECT  40.504 42.144 41.717 42.168 ;
     RECT  40.504 57.84 41.785 60.36 ;
     RECT  40.504 43.872 41.861 43.896 ;
     RECT  41.677 44.976 42.253 45.576 ;
     RECT  41.785 57.84 42.277 60.408 ;
     RECT  40.504 50.832 42.572 52.824 ;
     RECT  42.572 50.832 42.613 52.968 ;
     RECT  42.277 56.976 42.721 60.408 ;
     RECT  42.613 41.904 42.757 41.928 ;
     RECT  41.717 26.64 42.793 26.664 ;
     RECT  40.504 11.712 42.908 11.736 ;
     RECT  40.504 16.8 42.908 16.872 ;
     RECT  40.504 23.856 42.908 23.88 ;
     RECT  42.793 26.64 42.908 26.904 ;
     RECT  41.717 28.08 42.908 34.92 ;
     RECT  40.504 36.528 42.908 36.84 ;
     RECT  42.757 41.904 42.908 42.792 ;
     RECT  42.253 44.688 42.908 45.576 ;
     RECT  42.613 50.832 42.908 53.064 ;
     RECT  42.721 56.88 42.908 60.408 ;
     RECT  42.908 2.148 43.012 60.408 ;
     RECT  43.012 2.418 43.204 60.408 ;
     RECT  43.204 41.04 43.301 42.936 ;
     RECT  43.204 56.88 43.331 60.408 ;
     RECT  43.301 42.672 43.337 42.936 ;
     RECT  43.331 56.928 43.337 60.408 ;
     RECT  43.204 26.544 43.379 26.664 ;
     RECT  43.301 41.04 43.427 41.064 ;
     RECT  43.204 50.832 43.475 53.064 ;
     RECT  43.337 56.928 43.517 60.312 ;
     RECT  43.517 56.928 43.589 60.168 ;
     RECT  43.204 39.312 44.057 39.336 ;
     RECT  43.379 26.544 44.093 26.616 ;
     RECT  43.337 42.912 44.449 42.936 ;
     RECT  43.204 44.688 44.449 45.576 ;
     RECT  43.204 28.176 44.453 34.92 ;
     RECT  44.453 28.464 44.633 30.408 ;
     RECT  43.589 57.84 44.677 60.168 ;
     RECT  44.677 57.552 44.732 60.168 ;
     RECT  44.732 57.024 45.313 60.168 ;
     RECT  44.093 26.592 45.385 26.616 ;
     RECT  44.633 28.512 45.445 30.408 ;
     RECT  44.453 31.392 45.445 34.92 ;
     RECT  43.204 11.712 45.608 11.736 ;
     RECT  43.204 16.8 45.608 16.872 ;
     RECT  43.204 23.856 45.608 23.88 ;
     RECT  45.385 26.208 45.608 26.616 ;
     RECT  45.445 28.512 45.608 34.92 ;
     RECT  43.204 36.528 45.608 36.84 ;
     RECT  43.204 38.16 45.608 38.184 ;
     RECT  44.449 41.952 45.608 42.936 ;
     RECT  44.449 44.112 45.608 45.576 ;
     RECT  43.475 50.832 45.608 52.824 ;
     RECT  45.313 57.024 45.608 60.408 ;
     RECT  45.608 2.148 45.712 60.408 ;
     RECT  45.712 2.418 45.904 60.408 ;
     RECT  45.904 10.608 46.115 11.976 ;
     RECT  45.904 16.8 46.115 16.968 ;
     RECT  45.904 44.112 46.145 45.576 ;
     RECT  45.904 28.128 46.181 33.048 ;
     RECT  46.145 44.592 46.253 45.576 ;
     RECT  45.904 57.84 46.325 60.408 ;
     RECT  46.181 28.128 46.541 32.808 ;
     RECT  46.541 28.128 46.613 32.52 ;
     RECT  46.115 16.848 46.793 16.968 ;
     RECT  46.253 44.592 46.829 45 ;
     RECT  46.613 28.128 46.937 32.136 ;
     RECT  45.904 42.768 46.937 42.792 ;
     RECT  46.937 28.128 47.117 32.04 ;
     RECT  45.904 26.352 47.153 27.144 ;
     RECT  46.115 10.608 47.228 11.736 ;
     RECT  46.933 6.816 47.269 6.84 ;
     RECT  47.228 10.608 47.315 11.88 ;
     RECT  47.117 29.328 47.315 32.04 ;
     RECT  46.325 57.84 47.981 59.784 ;
     RECT  47.981 57.84 48.017 59.64 ;
     RECT  45.904 34.08 48.049 34.488 ;
     RECT  47.269 6 48.308 6.84 ;
     RECT  47.315 10.608 48.308 11.736 ;
     RECT  46.793 16.848 48.308 16.872 ;
     RECT  45.904 23.856 48.308 23.88 ;
     RECT  47.153 26.352 48.308 26.616 ;
     RECT  47.117 28.128 48.308 28.152 ;
     RECT  47.315 30.096 48.308 32.04 ;
     RECT  48.049 33.648 48.308 34.488 ;
     RECT  45.904 36.528 48.308 36.84 ;
     RECT  46.829 44.688 48.308 45 ;
     RECT  47.257 46.704 48.308 46.728 ;
     RECT  45.904 50.832 48.308 52.824 ;
     RECT  48.017 57.84 48.308 58.152 ;
     RECT  48.308 2.148 48.412 58.152 ;
     RECT  48.412 2.418 48.604 58.152 ;
     RECT  48.604 27.888 48.737 27.912 ;
     RECT  48.604 30.096 48.953 32.04 ;
     RECT  48.017 59.52 49.133 59.64 ;
     RECT  48.604 44.688 49.283 45 ;
     RECT  48.604 34.08 49.313 34.488 ;
     RECT  48.604 16.848 49.475 16.92 ;
     RECT  49.283 44.688 49.475 44.856 ;
     RECT  48.953 30.096 49.501 30.744 ;
     RECT  49.669 46.752 49.781 46.776 ;
     RECT  50.309 49.008 50.348 49.032 ;
     RECT  48.604 6 51.008 6.84 ;
     RECT  48.604 9.36 51.008 9.384 ;
     RECT  48.604 10.608 51.008 11.736 ;
     RECT  49.475 16.896 51.008 16.92 ;
     RECT  48.604 21.504 51.008 21.528 ;
     RECT  48.604 23.856 51.008 23.88 ;
     RECT  48.604 26.592 51.008 26.616 ;
     RECT  49.501 30.096 51.008 30.6 ;
     RECT  48.953 31.728 51.008 32.04 ;
     RECT  49.313 34.464 51.008 34.488 ;
     RECT  48.604 36.528 51.008 36.84 ;
     RECT  48.604 39.456 51.008 39.576 ;
     RECT  50.348 40.56 51.008 40.584 ;
     RECT  49.475 44.688 51.008 44.712 ;
     RECT  50.348 48.864 51.008 49.032 ;
     RECT  48.604 50.64 51.008 52.824 ;
     RECT  48.604 57.84 51.008 58.152 ;
     RECT  51.008 2.148 51.112 58.152 ;
     RECT  51.112 2.418 51.304 58.152 ;
     RECT  51.304 34.464 52.193 34.488 ;
     RECT  51.304 26.592 52.981 27.192 ;
     RECT  51.304 39.552 53.017 39.576 ;
     RECT  51.304 40.56 53.017 40.584 ;
     RECT  51.304 21.504 53.089 21.528 ;
     RECT  51.304 23.856 53.305 23.88 ;
     RECT  53.305 23.856 53.557 24.408 ;
     RECT  51.304 6 53.708 6.84 ;
     RECT  51.304 9.36 53.708 9.384 ;
     RECT  51.304 10.608 53.708 11.736 ;
     RECT  51.304 16.896 53.708 16.92 ;
     RECT  53.089 21.408 53.708 21.528 ;
     RECT  53.557 23.856 53.708 24.504 ;
     RECT  52.981 26.256 53.708 27.192 ;
     RECT  51.304 30.096 53.708 30.6 ;
     RECT  51.304 31.728 53.708 32.04 ;
     RECT  51.304 36.528 53.708 36.84 ;
     RECT  53.017 38.256 53.708 38.28 ;
     RECT  53.017 39.552 53.708 41.544 ;
     RECT  51.304 48.96 53.708 48.984 ;
     RECT  51.304 50.64 53.708 52.824 ;
     RECT  51.304 58.128 53.708 58.152 ;
     RECT  53.708 2.148 53.812 58.152 ;
     RECT  53.812 2.418 54.004 58.152 ;
     RECT  54.004 23.856 54.137 24.504 ;
     RECT  54.137 23.856 54.755 24.408 ;
     RECT  54.004 48.096 54.929 48.984 ;
     RECT  54.004 9.36 55.001 11.736 ;
     RECT  54.004 40.56 55.213 40.584 ;
     RECT  54.004 46.752 55.213 46.872 ;
     RECT  54.004 50.64 55.357 52.824 ;
     RECT  54.004 36 55.381 36.84 ;
     RECT  54.004 39.552 55.381 39.576 ;
     RECT  54.004 21.408 55.393 21.432 ;
     RECT  55.381 38.688 55.427 39.576 ;
     RECT  54.004 56.928 55.429 56.952 ;
     RECT  55.429 56.448 55.436 56.952 ;
     RECT  54.004 6 55.465 6.84 ;
     RECT  55.436 55.824 55.465 56.952 ;
     RECT  55.357 34.416 55.477 34.824 ;
     RECT  55.465 5.28 55.501 6.84 ;
     RECT  55.477 34.32 55.501 34.824 ;
     RECT  55.381 36 55.501 37.464 ;
     RECT  55.501 4.512 55.525 6.84 ;
     RECT  55.393 21.408 55.537 21.672 ;
     RECT  55.501 34.32 55.573 37.464 ;
     RECT  55.427 38.688 55.573 39.528 ;
     RECT  55.357 50.352 55.609 52.824 ;
     RECT  55.213 46.752 55.681 47.88 ;
     RECT  54.004 26.112 55.717 28.296 ;
     RECT  55.573 34.32 55.724 39.528 ;
     RECT  54.755 23.856 55.753 23.88 ;
     RECT  55.753 23.28 55.789 23.88 ;
     RECT  55.681 46.608 55.789 47.88 ;
     RECT  55.001 10.608 55.825 11.736 ;
     RECT  54.004 18.96 55.825 18.984 ;
     RECT  55.789 23.28 55.825 23.976 ;
     RECT  55.717 26.112 55.825 28.44 ;
     RECT  55.825 22.8 55.897 23.976 ;
     RECT  55.501 43.92 55.897 43.944 ;
     RECT  55.573 14.208 55.933 14.232 ;
     RECT  55.825 18.96 55.933 19.56 ;
     RECT  55.609 50.352 55.933 53.064 ;
     RECT  55.525 42.72 56.041 42.744 ;
     RECT  55.825 25.824 56.077 28.44 ;
     RECT  54.004 29.808 56.077 32.856 ;
     RECT  55.789 46.08 56.157 47.88 ;
     RECT  54.929 48.912 56.157 48.984 ;
     RECT  55.897 43.824 56.185 43.944 ;
     RECT  56.157 46.08 56.185 48.984 ;
     RECT  55.001 9.36 56.204 9.528 ;
     RECT  55.525 4.512 56.221 6.888 ;
     RECT  55.501 7.872 56.221 7.896 ;
     RECT  56.204 9.024 56.221 9.528 ;
     RECT  55.933 14.208 56.221 15 ;
     RECT  56.041 42.432 56.221 42.744 ;
     RECT  56.185 43.824 56.221 44.664 ;
     RECT  56.185 45.744 56.221 48.984 ;
     RECT  56.221 4.512 56.245 9.528 ;
     RECT  55.825 10.608 56.245 12.84 ;
     RECT  56.245 4.512 56.293 12.84 ;
     RECT  54.004 16.896 56.293 16.92 ;
     RECT  55.897 22.752 56.293 23.976 ;
     RECT  55.933 50.352 56.293 53.256 ;
     RECT  55.465 55.824 56.293 57.048 ;
     RECT  56.221 14.208 56.329 15.24 ;
     RECT  56.293 16.896 56.329 17.64 ;
     RECT  56.077 25.824 56.329 32.856 ;
     RECT  55.724 33.84 56.329 39.528 ;
     RECT  56.221 45.744 56.329 49.176 ;
     RECT  56.293 50.352 56.329 54.12 ;
     RECT  55.537 20.592 56.365 21.672 ;
     RECT  56.293 22.752 56.365 24.648 ;
     RECT  56.329 25.824 56.365 39.528 ;
     RECT  56.329 14.208 56.401 17.64 ;
     RECT  55.933 18.72 56.401 19.56 ;
     RECT  56.293 4.512 56.408 12.888 ;
     RECT  56.401 14.208 56.408 19.56 ;
     RECT  56.365 20.592 56.408 21.768 ;
     RECT  56.365 22.752 56.408 39.528 ;
     RECT  55.213 40.56 56.408 41.4 ;
     RECT  56.221 42.432 56.408 44.664 ;
     RECT  56.329 45.744 56.408 54.12 ;
     RECT  56.293 55.296 56.408 57.048 ;
     RECT  54.004 58.128 56.408 58.152 ;
     RECT  56.408 2.148 56.512 58.152 ;
     RECT  56.512 2.418 56.704 58.152 ;
     RECT  56.704 8.496 56.819 50.712 ;
     RECT  56.819 8.496 56.917 38.808 ;
     RECT  56.917 20.592 56.981 38.808 ;
     RECT  56.819 39.792 57.011 50.712 ;
     RECT  56.917 8.496 57.053 19.56 ;
     RECT  56.981 20.688 57.053 38.808 ;
     RECT  56.704 58.128 57.089 58.152 ;
     RECT  56.704 3.936 57.097 7.176 ;
     RECT  57.053 8.496 57.125 17.064 ;
     RECT  49.133 59.52 57.125 59.544 ;
     RECT  57.053 20.688 57.233 24.648 ;
     RECT  57.011 39.792 57.377 48.456 ;
     RECT  56.704 54.72 57.491 55.32 ;
     RECT  57.097 4.512 57.733 7.176 ;
     RECT  57.053 25.824 57.781 38.808 ;
     RECT  57.377 39.792 57.781 41.688 ;
     RECT  56.704 56.544 57.805 56.616 ;
     RECT  57.805 56.544 58.061 57.48 ;
     RECT  57.125 8.496 58.093 13.848 ;
     RECT  57.125 14.928 58.093 17.064 ;
     RECT  57.781 25.824 58.097 41.688 ;
     RECT  58.093 8.496 58.165 17.064 ;
     RECT  57.053 18.144 58.165 19.56 ;
     RECT  57.733 4.512 58.273 7.224 ;
     RECT  58.165 8.496 58.273 19.56 ;
     RECT  57.011 49.488 58.309 50.712 ;
     RECT  56.704 51.696 58.309 53.112 ;
     RECT  57.491 54.72 58.381 54.984 ;
     RECT  58.309 49.488 58.489 53.112 ;
     RECT  58.381 54.192 58.489 54.984 ;
     RECT  57.233 20.688 58.604 24.552 ;
     RECT  58.097 25.824 58.604 39.48 ;
     RECT  58.097 40.56 58.633 41.688 ;
     RECT  57.377 42.72 58.633 48.456 ;
     RECT  58.633 40.56 58.705 48.456 ;
     RECT  58.489 49.488 58.705 54.984 ;
     RECT  58.273 4.512 58.741 19.56 ;
     RECT  58.741 4.512 58.789 19.608 ;
     RECT  58.604 20.688 58.789 39.48 ;
     RECT  58.705 40.56 58.921 55.56 ;
     RECT  58.921 40.56 59.101 55.8 ;
     RECT  58.061 57.024 59.101 57.48 ;
     RECT  58.789 4.512 59.108 39.48 ;
     RECT  59.101 40.56 59.108 57.48 ;
     RECT  59.108 2.148 59.212 57.792 ;
     RECT  59.212 2.418 59.3 57.792 ;
     RECT  59.3 2.418 59.404 58.062 ;
     RECT  59.404 4.464 59.555 50.664 ;
     RECT  59.555 4.464 59.596 18.504 ;
     RECT  59.555 19.536 59.789 50.664 ;
     RECT  59.789 19.536 59.861 50.568 ;
     RECT  59.861 19.536 60.005 39 ;
     RECT  60.005 19.536 60.179 38.808 ;
     RECT  59.596 10.608 60.293 18.504 ;
     RECT  59.861 39.984 60.293 50.568 ;
     RECT  60.179 19.536 60.419 38.76 ;
     RECT  60.293 10.608 60.437 17.016 ;
     RECT  60.293 44.352 60.437 50.568 ;
     RECT  59.404 51.696 60.437 57.624 ;
     RECT  60.437 51.696 60.467 56.52 ;
     RECT  60.419 19.536 60.473 37.656 ;
     RECT  60.293 39.984 60.473 43.368 ;
     RECT  60.473 22.464 60.545 34.968 ;
     RECT  60.419 38.736 60.545 38.76 ;
     RECT  60.437 57.6 60.545 57.624 ;
     RECT  60.473 20.16 60.581 21.432 ;
     RECT  60.293 18.336 60.617 18.504 ;
     RECT  60.437 10.992 60.653 17.016 ;
     RECT  60.545 26.544 60.653 34.968 ;
     RECT  60.617 18.336 60.689 18.36 ;
     RECT  60.473 36 60.689 37.656 ;
     RECT  60.467 51.696 60.755 55.944 ;
     RECT  60.653 33.12 60.797 34.968 ;
     RECT  59.596 4.464 60.833 9.384 ;
     RECT  60.473 40.896 61.261 43.368 ;
     RECT  60.437 44.352 61.261 50.28 ;
     RECT  60.833 4.464 61.549 8.472 ;
     RECT  60.581 21.12 61.549 21.432 ;
     RECT  60.545 22.464 61.549 25.512 ;
     RECT  60.797 33.216 61.549 34.968 ;
     RECT  60.689 36 61.549 37.608 ;
     RECT  60.755 55.92 61.549 55.944 ;
     RECT  61.549 55.92 61.585 56.328 ;
     RECT  61.261 40.896 61.729 50.28 ;
     RECT  61.549 4.224 61.808 8.472 ;
     RECT  60.653 10.992 61.808 16.632 ;
     RECT  61.477 18.144 61.808 18.168 ;
     RECT  61.549 21.12 61.808 25.512 ;
     RECT  60.653 26.544 61.808 31.944 ;
     RECT  61.549 33.216 61.808 37.608 ;
     RECT  61.729 40.896 61.808 50.568 ;
     RECT  60.755 51.696 61.808 54.696 ;
     RECT  61.585 55.92 61.808 56.856 ;
     RECT  61.808 2.148 61.912 57.792 ;
     RECT  61.912 2.418 62 57.792 ;
     RECT  62 2.418 62.104 58.062 ;
     RECT  62.104 3.888 63.205 51.432 ;
     RECT  62.104 52.464 63.205 57.384 ;
     RECT  63.205 3.888 63.277 57.384 ;
     RECT  63.277 3.888 63.853 57.48 ;
     RECT  63.853 3.792 64.716 57.48 ;
     RECT  64.716 18.144 64.757 18.168 ;
     RECT  64.716 21.408 64.757 21.432 ;
     RECT  64.716 29.76 64.757 29.784 ;
     RECT  64.716 34.08 64.757 34.104 ;
     RECT  64.716 41.376 64.757 41.4 ;
     RECT  64.716 44.352 64.757 44.376 ;
     RECT  64.716 49.344 64.757 49.368 ;
    LAYER M5 ;
     RECT  2.4 2.137 2.52 2.151 ;
     RECT  5.1 2.137 5.22 2.151 ;
     RECT  7.8 2.137 7.92 2.151 ;
     RECT  10.5 2.137 10.62 2.151 ;
     RECT  13.2 2.137 13.32 2.151 ;
     RECT  15.9 2.137 16.02 2.151 ;
     RECT  18.6 2.137 18.72 2.151 ;
     RECT  21.3 2.137 21.42 2.151 ;
     RECT  24 2.137 24.12 2.151 ;
     RECT  26.7 2.137 26.82 2.151 ;
     RECT  29.4 2.137 29.52 2.151 ;
     RECT  32.1 2.137 32.22 2.151 ;
     RECT  34.8 2.137 34.92 2.151 ;
     RECT  37.5 2.137 37.62 2.151 ;
     RECT  40.2 2.137 40.32 2.151 ;
     RECT  42.9 2.137 43.02 2.151 ;
     RECT  45.6 2.137 45.72 2.151 ;
     RECT  48.3 2.137 48.42 2.151 ;
     RECT  51 2.137 51.12 2.151 ;
     RECT  53.7 2.137 53.82 2.151 ;
     RECT  56.4 2.137 56.52 2.151 ;
     RECT  59.1 2.137 59.22 2.151 ;
     RECT  61.8 2.137 61.92 2.151 ;
     RECT  56.4 2.151 56.712 3.925 ;
     RECT  56.4 3.925 57.048 5.029 ;
     RECT  56.4 5.029 57.624 5.077 ;
     RECT  59.1 2.151 59.412 5.221 ;
     RECT  56.4 5.077 57.912 5.269 ;
     RECT  60.624 4.453 60.648 5.893 ;
     RECT  58.992 5.221 59.412 5.989 ;
     RECT  55.536 5.269 57.912 6.035 ;
     RECT  55.536 6.035 57.864 6.083 ;
     RECT  60.624 5.893 60.744 6.323 ;
     RECT  55.536 6.083 56.808 6.563 ;
     RECT  47.28 5.989 47.304 6.805 ;
     RECT  58.944 5.989 59.412 6.899 ;
     RECT  60.72 6.323 60.744 6.899 ;
     RECT  57.84 6.083 57.864 7.189 ;
     RECT  57.744 7.189 57.864 7.235 ;
     RECT  59.1 6.899 59.412 7.957 ;
     RECT  57.744 7.235 57.768 9.061 ;
     RECT  48.3 2.151 48.612 9.349 ;
     RECT  57.744 9.061 58.008 9.779 ;
     RECT  59.1 7.957 59.544 10.019 ;
     RECT  57.744 9.779 57.768 10.643 ;
     RECT  46.944 6.805 47.304 10.835 ;
     RECT  55.536 6.563 56.712 11.171 ;
     RECT  59.1 10.019 59.412 11.797 ;
     RECT  45.6 2.151 45.912 11.941 ;
     RECT  58.848 11.797 59.412 12.517 ;
     RECT  56.304 11.171 56.712 12.899 ;
     RECT  58.56 12.517 59.412 13.571 ;
     RECT  56.4 12.899 56.712 14.197 ;
     RECT  56.4 14.197 56.856 14.917 ;
     RECT  58.848 13.571 59.412 14.917 ;
     RECT  60.384 14.869 60.408 14.917 ;
     RECT  58.848 14.917 60.408 15.491 ;
     RECT  56.4 14.917 57.816 15.589 ;
     RECT  58.848 15.491 59.832 15.589 ;
     RECT  56.4 15.589 59.832 16.019 ;
     RECT  58.704 16.019 59.832 16.595 ;
     RECT  45.6 11.941 46.104 16.835 ;
     RECT  48.3 9.349 49.272 16.837 ;
     RECT  58.848 16.595 59.832 17.699 ;
     RECT  56.4 16.019 56.712 18.181 ;
     RECT  58.848 17.699 59.412 18.851 ;
     RECT  53.7 2.151 54.012 18.949 ;
     RECT  59.1 18.851 59.412 19.237 ;
     RECT  59.1 19.237 59.544 19.909 ;
     RECT  56.4 18.181 56.904 20.003 ;
     RECT  58.8 19.909 59.544 20.003 ;
     RECT  56.4 20.003 56.712 21.637 ;
     RECT  58.8 20.003 59.412 21.683 ;
     RECT  37.5 2.151 37.812 22.165 ;
     RECT  58.944 21.683 59.412 22.307 ;
     RECT  56.4 21.637 56.904 22.837 ;
     RECT  56.4 22.837 57.096 23.123 ;
     RECT  59.1 22.307 59.412 23.509 ;
     RECT  58.656 23.509 59.412 23.797 ;
     RECT  53.7 18.949 54.12 24.373 ;
     RECT  53.7 24.373 54.744 24.469 ;
     RECT  58.656 23.797 59.544 24.659 ;
     RECT  58.656 24.659 59.412 25.909 ;
     RECT  45.6 16.835 45.912 26.197 ;
     RECT  42.9 2.151 43.212 26.629 ;
     RECT  38.88 24.469 38.904 26.725 ;
     RECT  40.2 2.151 40.512 26.725 ;
     RECT  56.4 23.123 56.712 27.589 ;
     RECT  58.464 25.909 59.412 27.733 ;
     RECT  56.4 27.589 56.808 27.829 ;
     RECT  58.464 27.733 60.264 27.829 ;
     RECT  38.88 26.725 40.512 27.877 ;
     RECT  56.4 27.829 60.264 27.877 ;
     RECT  61.8 2.151 62.112 27.877 ;
     RECT  38.88 27.877 41.496 28.453 ;
     RECT  42.9 26.629 43.368 28.453 ;
     RECT  56.4 27.877 62.112 28.691 ;
     RECT  2.4 2.151 2.712 28.789 ;
     RECT  2.4 28.789 2.904 28.933 ;
     RECT  2.4 28.933 3.336 29.029 ;
     RECT  28.176 27.877 28.2 29.029 ;
     RECT  34.8 2.151 35.112 29.029 ;
     RECT  56.4 28.691 60.264 29.123 ;
     RECT  47.28 10.835 47.304 29.363 ;
     RECT  58.464 29.123 60.264 29.507 ;
     RECT  0.144 29.509 0.168 29.605 ;
     RECT  28.176 29.029 28.392 29.605 ;
     RECT  29.4 2.151 29.712 29.605 ;
     RECT  34.8 29.029 35.88 29.605 ;
     RECT  36.864 22.165 37.812 29.605 ;
     RECT  26.7 2.151 27.012 29.653 ;
     RECT  28.176 29.605 29.712 29.653 ;
     RECT  0.144 29.605 0.552 29.747 ;
     RECT  2.4 29.029 3.528 30.037 ;
     RECT  5.1 2.151 5.412 30.037 ;
     RECT  0.528 29.747 0.552 30.083 ;
     RECT  45.408 26.197 45.912 30.181 ;
     RECT  56.4 29.123 56.808 30.275 ;
     RECT  53.568 24.469 54.744 30.611 ;
     RECT  61.8 28.691 62.112 30.757 ;
     RECT  58.992 29.507 60.264 30.851 ;
     RECT  2.4 30.037 5.412 30.899 ;
     RECT  61.8 30.757 62.76 30.947 ;
     RECT  64.608 30.757 64.632 30.947 ;
     RECT  2.4 30.899 2.904 31.043 ;
     RECT  34.8 29.605 37.812 31.285 ;
     RECT  38.88 28.453 43.368 31.285 ;
     RECT  34.8 31.285 43.368 31.765 ;
     RECT  44.88 30.181 45.912 31.765 ;
     RECT  53.7 30.611 54.744 31.861 ;
     RECT  56.4 30.275 56.712 31.861 ;
     RECT  4.224 30.899 5.412 32.051 ;
     RECT  26.7 29.653 29.712 32.293 ;
     RECT  59.1 30.851 60.168 32.293 ;
     RECT  57.696 31.285 57.72 32.437 ;
     RECT  59.1 32.293 60.504 32.437 ;
     RECT  57.696 32.437 60.504 33.107 ;
     RECT  26.592 32.293 29.712 33.253 ;
     RECT  57.84 33.107 60.504 33.493 ;
     RECT  53.7 31.861 56.712 33.541 ;
     RECT  57.84 33.493 60.6 33.683 ;
     RECT  57.84 33.683 60.456 34.067 ;
     RECT  53.7 33.541 56.808 34.355 ;
     RECT  26.592 33.253 30.12 34.645 ;
     RECT  26.592 34.645 30.888 34.693 ;
     RECT  32.1 2.151 32.412 34.693 ;
     RECT  58.032 34.067 60.456 34.835 ;
     RECT  53.7 34.355 54.744 35.317 ;
     RECT  55.776 34.355 56.808 35.317 ;
     RECT  58.032 34.835 58.104 35.317 ;
     RECT  26.592 34.693 32.412 35.749 ;
     RECT  53.7 35.317 58.104 36.035 ;
     RECT  59.1 34.835 60.456 36.035 ;
     RECT  26.592 35.749 32.52 36.469 ;
     RECT  26.592 36.469 33.096 36.853 ;
     RECT  34.8 31.765 45.912 36.853 ;
     RECT  55.632 36.035 58.104 37.091 ;
     RECT  55.632 37.091 58.056 37.429 ;
     RECT  26.592 36.853 45.912 37.573 ;
     RECT  59.1 36.035 60.168 38.149 ;
     RECT  59.1 38.149 60.408 38.819 ;
     RECT  26.448 37.573 45.912 39.013 ;
     RECT  48.3 16.837 49.464 39.445 ;
     RECT  51 2.151 51.312 39.445 ;
     RECT  55.392 37.429 58.056 39.587 ;
     RECT  59.1 38.819 59.412 39.973 ;
     RECT  60.384 38.819 60.408 39.973 ;
     RECT  59.1 39.973 60.408 40.019 ;
     RECT  55.632 39.587 58.056 41.411 ;
     RECT  56.304 41.411 58.056 41.651 ;
     RECT  59.1 40.019 60.12 42.085 ;
     RECT  56.304 41.651 56.808 42.709 ;
     RECT  59.1 42.085 60.408 43.379 ;
     RECT  55.536 42.709 56.808 43.955 ;
     RECT  61.8 30.947 62.112 44.437 ;
     RECT  25.968 39.013 45.912 44.581 ;
     RECT  25.968 44.581 46.008 44.723 ;
     RECT  48.3 39.445 51.312 44.867 ;
     RECT  60.96 44.437 62.112 44.867 ;
     RECT  58.032 41.651 58.056 45.541 ;
     RECT  59.1 43.379 59.544 45.541 ;
     RECT  56.4 43.955 56.808 45.733 ;
     RECT  58.032 45.541 59.544 45.733 ;
     RECT  57.792 45.733 59.544 45.973 ;
     RECT  57.792 45.973 60.36 46.259 ;
     RECT  57.792 46.259 58.056 46.835 ;
     RECT  57.792 46.835 57.816 47.219 ;
     RECT  56.304 45.733 56.808 47.269 ;
     RECT  56.304 47.269 57.576 47.845 ;
     RECT  55.536 47.845 57.576 48.421 ;
     RECT  55.536 48.421 57.624 48.947 ;
     RECT  59.1 46.259 60.36 48.995 ;
     RECT  50.4 44.867 51.312 48.997 ;
     RECT  56.208 48.947 57.624 49.715 ;
     RECT  48.3 44.867 49.272 50.675 ;
     RECT  56.208 49.715 57.528 50.677 ;
     RECT  50.352 48.997 51.312 50.771 ;
     RECT  55.536 50.677 57.528 50.821 ;
     RECT  59.1 48.995 59.832 51.109 ;
     RECT  55.296 50.821 57.528 51.827 ;
     RECT  55.296 51.827 57.48 51.923 ;
     RECT  58.992 51.109 59.832 51.923 ;
     RECT  59.1 51.923 59.832 52.405 ;
     RECT  59.1 52.405 60.648 54.227 ;
     RECT  60.432 54.227 60.648 54.517 ;
     RECT  55.536 51.923 57.48 55.331 ;
     RECT  60.432 54.517 60.744 55.379 ;
     RECT  55.536 55.331 56.712 55.813 ;
     RECT  60.432 55.379 60.456 56.531 ;
     RECT  55.488 55.813 56.712 57.059 ;
     RECT  2.4 31.043 2.712 58.059 ;
     RECT  5.1 32.051 5.412 58.059 ;
     RECT  7.8 2.151 8.112 58.059 ;
     RECT  10.5 2.151 10.812 58.059 ;
     RECT  13.2 2.151 13.512 58.059 ;
     RECT  15.9 2.151 16.212 58.059 ;
     RECT  18.6 2.151 18.912 58.059 ;
     RECT  21.3 2.151 21.612 58.059 ;
     RECT  24 2.151 24.312 58.059 ;
     RECT  48.3 50.675 48.612 58.059 ;
     RECT  51 50.771 51.312 58.059 ;
     RECT  53.7 36.035 54.012 58.059 ;
     RECT  56.4 57.059 56.712 58.059 ;
     RECT  59.1 54.227 59.412 58.059 ;
     RECT  61.8 44.867 62.112 58.059 ;
     RECT  2.592 58.059 2.712 58.073 ;
     RECT  5.292 58.059 5.412 58.073 ;
     RECT  7.992 58.059 8.112 58.073 ;
     RECT  10.692 58.059 10.812 58.073 ;
     RECT  13.392 58.059 13.512 58.073 ;
     RECT  16.092 58.059 16.212 58.073 ;
     RECT  18.792 58.059 18.912 58.073 ;
     RECT  21.492 58.059 21.612 58.073 ;
     RECT  24.192 58.059 24.312 58.073 ;
     RECT  25.968 44.723 45.912 58.073 ;
     RECT  48.492 58.059 48.612 58.073 ;
     RECT  51.192 58.059 51.312 58.073 ;
     RECT  53.892 58.059 54.012 58.073 ;
     RECT  56.592 58.059 56.712 58.073 ;
     RECT  59.292 58.059 59.412 58.073 ;
     RECT  61.992 58.059 62.112 58.073 ;
     RECT  25.968 58.073 45.432 60.419 ;
     RECT  25.968 60.419 44.808 60.432 ;
  END
END qfd_rlyh0_548_EN_65x60
END LIBRARY
